VERSION 5.7 ;
BUSBITCHARS "[]" ;
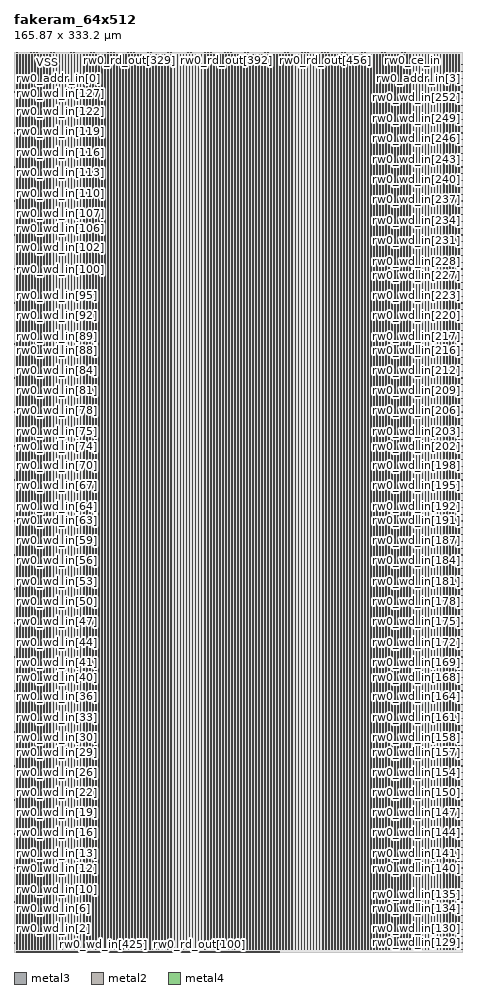
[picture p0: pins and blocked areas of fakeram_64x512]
MACRO fakeram_64x512
  FOREIGN fakeram_64x512 0 0 ;
  SYMMETRY X Y R90 ;
  SIZE 165.870 BY 333.200 ;
  CLASS BLOCK ;
  PIN rw0_wd_in[0]
    DIRECTION INPUT ;
    USE SIGNAL ;
    SHAPE ABUTMENT ;
    PORT
      LAYER metal3 ;
      RECT 0.000 0.805 0.210 0.875 ;
    END
  END rw0_wd_in[0]
  PIN rw0_wd_in[1]
    DIRECTION INPUT ;
    USE SIGNAL ;
    SHAPE ABUTMENT ;
    PORT
      LAYER metal3 ;
      RECT 0.000 3.325 0.210 3.395 ;
    END
  END rw0_wd_in[1]
  PIN rw0_wd_in[2]
    DIRECTION INPUT ;
    USE SIGNAL ;
    SHAPE ABUTMENT ;
    PORT
      LAYER metal3 ;
      RECT 0.000 5.845 0.210 5.915 ;
    END
  END rw0_wd_in[2]
  PIN rw0_wd_in[3]
    DIRECTION INPUT ;
    USE SIGNAL ;
    SHAPE ABUTMENT ;
    PORT
      LAYER metal3 ;
      RECT 0.000 8.365 0.210 8.435 ;
    END
  END rw0_wd_in[3]
  PIN rw0_wd_in[4]
    DIRECTION INPUT ;
    USE SIGNAL ;
    SHAPE ABUTMENT ;
    PORT
      LAYER metal3 ;
      RECT 0.000 10.885 0.210 10.955 ;
    END
  END rw0_wd_in[4]
  PIN rw0_wd_in[5]
    DIRECTION INPUT ;
    USE SIGNAL ;
    SHAPE ABUTMENT ;
    PORT
      LAYER metal3 ;
      RECT 0.000 13.405 0.210 13.475 ;
    END
  END rw0_wd_in[5]
  PIN rw0_wd_in[6]
    DIRECTION INPUT ;
    USE SIGNAL ;
    SHAPE ABUTMENT ;
    PORT
      LAYER metal3 ;
      RECT 0.000 15.925 0.210 15.995 ;
    END
  END rw0_wd_in[6]
  PIN rw0_wd_in[7]
    DIRECTION INPUT ;
    USE SIGNAL ;
    SHAPE ABUTMENT ;
    PORT
      LAYER metal3 ;
      RECT 0.000 18.445 0.210 18.515 ;
    END
  END rw0_wd_in[7]
  PIN rw0_wd_in[8]
    DIRECTION INPUT ;
    USE SIGNAL ;
    SHAPE ABUTMENT ;
    PORT
      LAYER metal3 ;
      RECT 0.000 20.965 0.210 21.035 ;
    END
  END rw0_wd_in[8]
  PIN rw0_wd_in[9]
    DIRECTION INPUT ;
    USE SIGNAL ;
    SHAPE ABUTMENT ;
    PORT
      LAYER metal3 ;
      RECT 0.000 23.485 0.210 23.555 ;
    END
  END rw0_wd_in[9]
  PIN rw0_wd_in[10]
    DIRECTION INPUT ;
    USE SIGNAL ;
    SHAPE ABUTMENT ;
    PORT
      LAYER metal3 ;
      RECT 0.000 26.005 0.210 26.075 ;
    END
  END rw0_wd_in[10]
  PIN rw0_wd_in[11]
    DIRECTION INPUT ;
    USE SIGNAL ;
    SHAPE ABUTMENT ;
    PORT
      LAYER metal3 ;
      RECT 0.000 28.525 0.210 28.595 ;
    END
  END rw0_wd_in[11]
  PIN rw0_wd_in[12]
    DIRECTION INPUT ;
    USE SIGNAL ;
    SHAPE ABUTMENT ;
    PORT
      LAYER metal3 ;
      RECT 0.000 31.045 0.210 31.115 ;
    END
  END rw0_wd_in[12]
  PIN rw0_wd_in[13]
    DIRECTION INPUT ;
    USE SIGNAL ;
    SHAPE ABUTMENT ;
    PORT
      LAYER metal3 ;
      RECT 0.000 33.565 0.210 33.635 ;
    END
  END rw0_wd_in[13]
  PIN rw0_wd_in[14]
    DIRECTION INPUT ;
    USE SIGNAL ;
    SHAPE ABUTMENT ;
    PORT
      LAYER metal3 ;
      RECT 0.000 36.085 0.210 36.155 ;
    END
  END rw0_wd_in[14]
  PIN rw0_wd_in[15]
    DIRECTION INPUT ;
    USE SIGNAL ;
    SHAPE ABUTMENT ;
    PORT
      LAYER metal3 ;
      RECT 0.000 38.605 0.210 38.675 ;
    END
  END rw0_wd_in[15]
  PIN rw0_wd_in[16]
    DIRECTION INPUT ;
    USE SIGNAL ;
    SHAPE ABUTMENT ;
    PORT
      LAYER metal3 ;
      RECT 0.000 41.125 0.210 41.195 ;
    END
  END rw0_wd_in[16]
  PIN rw0_wd_in[17]
    DIRECTION INPUT ;
    USE SIGNAL ;
    SHAPE ABUTMENT ;
    PORT
      LAYER metal3 ;
      RECT 0.000 43.645 0.210 43.715 ;
    END
  END rw0_wd_in[17]
  PIN rw0_wd_in[18]
    DIRECTION INPUT ;
    USE SIGNAL ;
    SHAPE ABUTMENT ;
    PORT
      LAYER metal3 ;
      RECT 0.000 46.165 0.210 46.235 ;
    END
  END rw0_wd_in[18]
  PIN rw0_wd_in[19]
    DIRECTION INPUT ;
    USE SIGNAL ;
    SHAPE ABUTMENT ;
    PORT
      LAYER metal3 ;
      RECT 0.000 48.685 0.210 48.755 ;
    END
  END rw0_wd_in[19]
  PIN rw0_wd_in[20]
    DIRECTION INPUT ;
    USE SIGNAL ;
    SHAPE ABUTMENT ;
    PORT
      LAYER metal3 ;
      RECT 0.000 51.205 0.210 51.275 ;
    END
  END rw0_wd_in[20]
  PIN rw0_wd_in[21]
    DIRECTION INPUT ;
    USE SIGNAL ;
    SHAPE ABUTMENT ;
    PORT
      LAYER metal3 ;
      RECT 0.000 53.725 0.210 53.795 ;
    END
  END rw0_wd_in[21]
  PIN rw0_wd_in[22]
    DIRECTION INPUT ;
    USE SIGNAL ;
    SHAPE ABUTMENT ;
    PORT
      LAYER metal3 ;
      RECT 0.000 56.245 0.210 56.315 ;
    END
  END rw0_wd_in[22]
  PIN rw0_wd_in[23]
    DIRECTION INPUT ;
    USE SIGNAL ;
    SHAPE ABUTMENT ;
    PORT
      LAYER metal3 ;
      RECT 0.000 58.765 0.210 58.835 ;
    END
  END rw0_wd_in[23]
  PIN rw0_wd_in[24]
    DIRECTION INPUT ;
    USE SIGNAL ;
    SHAPE ABUTMENT ;
    PORT
      LAYER metal3 ;
      RECT 0.000 61.285 0.210 61.355 ;
    END
  END rw0_wd_in[24]
  PIN rw0_wd_in[25]
    DIRECTION INPUT ;
    USE SIGNAL ;
    SHAPE ABUTMENT ;
    PORT
      LAYER metal3 ;
      RECT 0.000 63.805 0.210 63.875 ;
    END
  END rw0_wd_in[25]
  PIN rw0_wd_in[26]
    DIRECTION INPUT ;
    USE SIGNAL ;
    SHAPE ABUTMENT ;
    PORT
      LAYER metal3 ;
      RECT 0.000 66.325 0.210 66.395 ;
    END
  END rw0_wd_in[26]
  PIN rw0_wd_in[27]
    DIRECTION INPUT ;
    USE SIGNAL ;
    SHAPE ABUTMENT ;
    PORT
      LAYER metal3 ;
      RECT 0.000 68.845 0.210 68.915 ;
    END
  END rw0_wd_in[27]
  PIN rw0_wd_in[28]
    DIRECTION INPUT ;
    USE SIGNAL ;
    SHAPE ABUTMENT ;
    PORT
      LAYER metal3 ;
      RECT 0.000 71.365 0.210 71.435 ;
    END
  END rw0_wd_in[28]
  PIN rw0_wd_in[29]
    DIRECTION INPUT ;
    USE SIGNAL ;
    SHAPE ABUTMENT ;
    PORT
      LAYER metal3 ;
      RECT 0.000 73.885 0.210 73.955 ;
    END
  END rw0_wd_in[29]
  PIN rw0_wd_in[30]
    DIRECTION INPUT ;
    USE SIGNAL ;
    SHAPE ABUTMENT ;
    PORT
      LAYER metal3 ;
      RECT 0.000 76.405 0.210 76.475 ;
    END
  END rw0_wd_in[30]
  PIN rw0_wd_in[31]
    DIRECTION INPUT ;
    USE SIGNAL ;
    SHAPE ABUTMENT ;
    PORT
      LAYER metal3 ;
      RECT 0.000 78.925 0.210 78.995 ;
    END
  END rw0_wd_in[31]
  PIN rw0_wd_in[32]
    DIRECTION INPUT ;
    USE SIGNAL ;
    SHAPE ABUTMENT ;
    PORT
      LAYER metal3 ;
      RECT 0.000 81.445 0.210 81.515 ;
    END
  END rw0_wd_in[32]
  PIN rw0_wd_in[33]
    DIRECTION INPUT ;
    USE SIGNAL ;
    SHAPE ABUTMENT ;
    PORT
      LAYER metal3 ;
      RECT 0.000 83.965 0.210 84.035 ;
    END
  END rw0_wd_in[33]
  PIN rw0_wd_in[34]
    DIRECTION INPUT ;
    USE SIGNAL ;
    SHAPE ABUTMENT ;
    PORT
      LAYER metal3 ;
      RECT 0.000 86.485 0.210 86.555 ;
    END
  END rw0_wd_in[34]
  PIN rw0_wd_in[35]
    DIRECTION INPUT ;
    USE SIGNAL ;
    SHAPE ABUTMENT ;
    PORT
      LAYER metal3 ;
      RECT 0.000 89.005 0.210 89.075 ;
    END
  END rw0_wd_in[35]
  PIN rw0_wd_in[36]
    DIRECTION INPUT ;
    USE SIGNAL ;
    SHAPE ABUTMENT ;
    PORT
      LAYER metal3 ;
      RECT 0.000 91.525 0.210 91.595 ;
    END
  END rw0_wd_in[36]
  PIN rw0_wd_in[37]
    DIRECTION INPUT ;
    USE SIGNAL ;
    SHAPE ABUTMENT ;
    PORT
      LAYER metal3 ;
      RECT 0.000 94.045 0.210 94.115 ;
    END
  END rw0_wd_in[37]
  PIN rw0_wd_in[38]
    DIRECTION INPUT ;
    USE SIGNAL ;
    SHAPE ABUTMENT ;
    PORT
      LAYER metal3 ;
      RECT 0.000 96.565 0.210 96.635 ;
    END
  END rw0_wd_in[38]
  PIN rw0_wd_in[39]
    DIRECTION INPUT ;
    USE SIGNAL ;
    SHAPE ABUTMENT ;
    PORT
      LAYER metal3 ;
      RECT 0.000 99.085 0.210 99.155 ;
    END
  END rw0_wd_in[39]
  PIN rw0_wd_in[40]
    DIRECTION INPUT ;
    USE SIGNAL ;
    SHAPE ABUTMENT ;
    PORT
      LAYER metal3 ;
      RECT 0.000 101.605 0.210 101.675 ;
    END
  END rw0_wd_in[40]
  PIN rw0_wd_in[41]
    DIRECTION INPUT ;
    USE SIGNAL ;
    SHAPE ABUTMENT ;
    PORT
      LAYER metal3 ;
      RECT 0.000 104.125 0.210 104.195 ;
    END
  END rw0_wd_in[41]
  PIN rw0_wd_in[42]
    DIRECTION INPUT ;
    USE SIGNAL ;
    SHAPE ABUTMENT ;
    PORT
      LAYER metal3 ;
      RECT 0.000 106.645 0.210 106.715 ;
    END
  END rw0_wd_in[42]
  PIN rw0_wd_in[43]
    DIRECTION INPUT ;
    USE SIGNAL ;
    SHAPE ABUTMENT ;
    PORT
      LAYER metal3 ;
      RECT 0.000 109.165 0.210 109.235 ;
    END
  END rw0_wd_in[43]
  PIN rw0_wd_in[44]
    DIRECTION INPUT ;
    USE SIGNAL ;
    SHAPE ABUTMENT ;
    PORT
      LAYER metal3 ;
      RECT 0.000 111.685 0.210 111.755 ;
    END
  END rw0_wd_in[44]
  PIN rw0_wd_in[45]
    DIRECTION INPUT ;
    USE SIGNAL ;
    SHAPE ABUTMENT ;
    PORT
      LAYER metal3 ;
      RECT 0.000 114.205 0.210 114.275 ;
    END
  END rw0_wd_in[45]
  PIN rw0_wd_in[46]
    DIRECTION INPUT ;
    USE SIGNAL ;
    SHAPE ABUTMENT ;
    PORT
      LAYER metal3 ;
      RECT 0.000 116.725 0.210 116.795 ;
    END
  END rw0_wd_in[46]
  PIN rw0_wd_in[47]
    DIRECTION INPUT ;
    USE SIGNAL ;
    SHAPE ABUTMENT ;
    PORT
      LAYER metal3 ;
      RECT 0.000 119.245 0.210 119.315 ;
    END
  END rw0_wd_in[47]
  PIN rw0_wd_in[48]
    DIRECTION INPUT ;
    USE SIGNAL ;
    SHAPE ABUTMENT ;
    PORT
      LAYER metal3 ;
      RECT 0.000 121.765 0.210 121.835 ;
    END
  END rw0_wd_in[48]
  PIN rw0_wd_in[49]
    DIRECTION INPUT ;
    USE SIGNAL ;
    SHAPE ABUTMENT ;
    PORT
      LAYER metal3 ;
      RECT 0.000 124.285 0.210 124.355 ;
    END
  END rw0_wd_in[49]
  PIN rw0_wd_in[50]
    DIRECTION INPUT ;
    USE SIGNAL ;
    SHAPE ABUTMENT ;
    PORT
      LAYER metal3 ;
      RECT 0.000 126.805 0.210 126.875 ;
    END
  END rw0_wd_in[50]
  PIN rw0_wd_in[51]
    DIRECTION INPUT ;
    USE SIGNAL ;
    SHAPE ABUTMENT ;
    PORT
      LAYER metal3 ;
      RECT 0.000 129.325 0.210 129.395 ;
    END
  END rw0_wd_in[51]
  PIN rw0_wd_in[52]
    DIRECTION INPUT ;
    USE SIGNAL ;
    SHAPE ABUTMENT ;
    PORT
      LAYER metal3 ;
      RECT 0.000 131.845 0.210 131.915 ;
    END
  END rw0_wd_in[52]
  PIN rw0_wd_in[53]
    DIRECTION INPUT ;
    USE SIGNAL ;
    SHAPE ABUTMENT ;
    PORT
      LAYER metal3 ;
      RECT 0.000 134.365 0.210 134.435 ;
    END
  END rw0_wd_in[53]
  PIN rw0_wd_in[54]
    DIRECTION INPUT ;
    USE SIGNAL ;
    SHAPE ABUTMENT ;
    PORT
      LAYER metal3 ;
      RECT 0.000 136.885 0.210 136.955 ;
    END
  END rw0_wd_in[54]
  PIN rw0_wd_in[55]
    DIRECTION INPUT ;
    USE SIGNAL ;
    SHAPE ABUTMENT ;
    PORT
      LAYER metal3 ;
      RECT 0.000 139.405 0.210 139.475 ;
    END
  END rw0_wd_in[55]
  PIN rw0_wd_in[56]
    DIRECTION INPUT ;
    USE SIGNAL ;
    SHAPE ABUTMENT ;
    PORT
      LAYER metal3 ;
      RECT 0.000 141.925 0.210 141.995 ;
    END
  END rw0_wd_in[56]
  PIN rw0_wd_in[57]
    DIRECTION INPUT ;
    USE SIGNAL ;
    SHAPE ABUTMENT ;
    PORT
      LAYER metal3 ;
      RECT 0.000 144.445 0.210 144.515 ;
    END
  END rw0_wd_in[57]
  PIN rw0_wd_in[58]
    DIRECTION INPUT ;
    USE SIGNAL ;
    SHAPE ABUTMENT ;
    PORT
      LAYER metal3 ;
      RECT 0.000 146.965 0.210 147.035 ;
    END
  END rw0_wd_in[58]
  PIN rw0_wd_in[59]
    DIRECTION INPUT ;
    USE SIGNAL ;
    SHAPE ABUTMENT ;
    PORT
      LAYER metal3 ;
      RECT 0.000 149.485 0.210 149.555 ;
    END
  END rw0_wd_in[59]
  PIN rw0_wd_in[60]
    DIRECTION INPUT ;
    USE SIGNAL ;
    SHAPE ABUTMENT ;
    PORT
      LAYER metal3 ;
      RECT 0.000 152.005 0.210 152.075 ;
    END
  END rw0_wd_in[60]
  PIN rw0_wd_in[61]
    DIRECTION INPUT ;
    USE SIGNAL ;
    SHAPE ABUTMENT ;
    PORT
      LAYER metal3 ;
      RECT 0.000 154.525 0.210 154.595 ;
    END
  END rw0_wd_in[61]
  PIN rw0_wd_in[62]
    DIRECTION INPUT ;
    USE SIGNAL ;
    SHAPE ABUTMENT ;
    PORT
      LAYER metal3 ;
      RECT 0.000 157.045 0.210 157.115 ;
    END
  END rw0_wd_in[62]
  PIN rw0_wd_in[63]
    DIRECTION INPUT ;
    USE SIGNAL ;
    SHAPE ABUTMENT ;
    PORT
      LAYER metal3 ;
      RECT 0.000 159.565 0.210 159.635 ;
    END
  END rw0_wd_in[63]
  PIN rw0_wd_in[64]
    DIRECTION INPUT ;
    USE SIGNAL ;
    SHAPE ABUTMENT ;
    PORT
      LAYER metal3 ;
      RECT 0.000 162.085 0.210 162.155 ;
    END
  END rw0_wd_in[64]
  PIN rw0_wd_in[65]
    DIRECTION INPUT ;
    USE SIGNAL ;
    SHAPE ABUTMENT ;
    PORT
      LAYER metal3 ;
      RECT 0.000 164.605 0.210 164.675 ;
    END
  END rw0_wd_in[65]
  PIN rw0_wd_in[66]
    DIRECTION INPUT ;
    USE SIGNAL ;
    SHAPE ABUTMENT ;
    PORT
      LAYER metal3 ;
      RECT 0.000 167.125 0.210 167.195 ;
    END
  END rw0_wd_in[66]
  PIN rw0_wd_in[67]
    DIRECTION INPUT ;
    USE SIGNAL ;
    SHAPE ABUTMENT ;
    PORT
      LAYER metal3 ;
      RECT 0.000 169.645 0.210 169.715 ;
    END
  END rw0_wd_in[67]
  PIN rw0_wd_in[68]
    DIRECTION INPUT ;
    USE SIGNAL ;
    SHAPE ABUTMENT ;
    PORT
      LAYER metal3 ;
      RECT 0.000 172.165 0.210 172.235 ;
    END
  END rw0_wd_in[68]
  PIN rw0_wd_in[69]
    DIRECTION INPUT ;
    USE SIGNAL ;
    SHAPE ABUTMENT ;
    PORT
      LAYER metal3 ;
      RECT 0.000 174.685 0.210 174.755 ;
    END
  END rw0_wd_in[69]
  PIN rw0_wd_in[70]
    DIRECTION INPUT ;
    USE SIGNAL ;
    SHAPE ABUTMENT ;
    PORT
      LAYER metal3 ;
      RECT 0.000 177.205 0.210 177.275 ;
    END
  END rw0_wd_in[70]
  PIN rw0_wd_in[71]
    DIRECTION INPUT ;
    USE SIGNAL ;
    SHAPE ABUTMENT ;
    PORT
      LAYER metal3 ;
      RECT 0.000 179.725 0.210 179.795 ;
    END
  END rw0_wd_in[71]
  PIN rw0_wd_in[72]
    DIRECTION INPUT ;
    USE SIGNAL ;
    SHAPE ABUTMENT ;
    PORT
      LAYER metal3 ;
      RECT 0.000 182.245 0.210 182.315 ;
    END
  END rw0_wd_in[72]
  PIN rw0_wd_in[73]
    DIRECTION INPUT ;
    USE SIGNAL ;
    SHAPE ABUTMENT ;
    PORT
      LAYER metal3 ;
      RECT 0.000 184.765 0.210 184.835 ;
    END
  END rw0_wd_in[73]
  PIN rw0_wd_in[74]
    DIRECTION INPUT ;
    USE SIGNAL ;
    SHAPE ABUTMENT ;
    PORT
      LAYER metal3 ;
      RECT 0.000 187.285 0.210 187.355 ;
    END
  END rw0_wd_in[74]
  PIN rw0_wd_in[75]
    DIRECTION INPUT ;
    USE SIGNAL ;
    SHAPE ABUTMENT ;
    PORT
      LAYER metal3 ;
      RECT 0.000 189.805 0.210 189.875 ;
    END
  END rw0_wd_in[75]
  PIN rw0_wd_in[76]
    DIRECTION INPUT ;
    USE SIGNAL ;
    SHAPE ABUTMENT ;
    PORT
      LAYER metal3 ;
      RECT 0.000 192.325 0.210 192.395 ;
    END
  END rw0_wd_in[76]
  PIN rw0_wd_in[77]
    DIRECTION INPUT ;
    USE SIGNAL ;
    SHAPE ABUTMENT ;
    PORT
      LAYER metal3 ;
      RECT 0.000 194.845 0.210 194.915 ;
    END
  END rw0_wd_in[77]
  PIN rw0_wd_in[78]
    DIRECTION INPUT ;
    USE SIGNAL ;
    SHAPE ABUTMENT ;
    PORT
      LAYER metal3 ;
      RECT 0.000 197.365 0.210 197.435 ;
    END
  END rw0_wd_in[78]
  PIN rw0_wd_in[79]
    DIRECTION INPUT ;
    USE SIGNAL ;
    SHAPE ABUTMENT ;
    PORT
      LAYER metal3 ;
      RECT 0.000 199.885 0.210 199.955 ;
    END
  END rw0_wd_in[79]
  PIN rw0_wd_in[80]
    DIRECTION INPUT ;
    USE SIGNAL ;
    SHAPE ABUTMENT ;
    PORT
      LAYER metal3 ;
      RECT 0.000 202.405 0.210 202.475 ;
    END
  END rw0_wd_in[80]
  PIN rw0_wd_in[81]
    DIRECTION INPUT ;
    USE SIGNAL ;
    SHAPE ABUTMENT ;
    PORT
      LAYER metal3 ;
      RECT 0.000 204.925 0.210 204.995 ;
    END
  END rw0_wd_in[81]
  PIN rw0_wd_in[82]
    DIRECTION INPUT ;
    USE SIGNAL ;
    SHAPE ABUTMENT ;
    PORT
      LAYER metal3 ;
      RECT 0.000 207.445 0.210 207.515 ;
    END
  END rw0_wd_in[82]
  PIN rw0_wd_in[83]
    DIRECTION INPUT ;
    USE SIGNAL ;
    SHAPE ABUTMENT ;
    PORT
      LAYER metal3 ;
      RECT 0.000 209.965 0.210 210.035 ;
    END
  END rw0_wd_in[83]
  PIN rw0_wd_in[84]
    DIRECTION INPUT ;
    USE SIGNAL ;
    SHAPE ABUTMENT ;
    PORT
      LAYER metal3 ;
      RECT 0.000 212.485 0.210 212.555 ;
    END
  END rw0_wd_in[84]
  PIN rw0_wd_in[85]
    DIRECTION INPUT ;
    USE SIGNAL ;
    SHAPE ABUTMENT ;
    PORT
      LAYER metal3 ;
      RECT 0.000 215.005 0.210 215.075 ;
    END
  END rw0_wd_in[85]
  PIN rw0_wd_in[86]
    DIRECTION INPUT ;
    USE SIGNAL ;
    SHAPE ABUTMENT ;
    PORT
      LAYER metal3 ;
      RECT 0.000 217.525 0.210 217.595 ;
    END
  END rw0_wd_in[86]
  PIN rw0_wd_in[87]
    DIRECTION INPUT ;
    USE SIGNAL ;
    SHAPE ABUTMENT ;
    PORT
      LAYER metal3 ;
      RECT 0.000 220.045 0.210 220.115 ;
    END
  END rw0_wd_in[87]
  PIN rw0_wd_in[88]
    DIRECTION INPUT ;
    USE SIGNAL ;
    SHAPE ABUTMENT ;
    PORT
      LAYER metal3 ;
      RECT 0.000 222.565 0.210 222.635 ;
    END
  END rw0_wd_in[88]
  PIN rw0_wd_in[89]
    DIRECTION INPUT ;
    USE SIGNAL ;
    SHAPE ABUTMENT ;
    PORT
      LAYER metal3 ;
      RECT 0.000 225.085 0.210 225.155 ;
    END
  END rw0_wd_in[89]
  PIN rw0_wd_in[90]
    DIRECTION INPUT ;
    USE SIGNAL ;
    SHAPE ABUTMENT ;
    PORT
      LAYER metal3 ;
      RECT 0.000 227.605 0.210 227.675 ;
    END
  END rw0_wd_in[90]
  PIN rw0_wd_in[91]
    DIRECTION INPUT ;
    USE SIGNAL ;
    SHAPE ABUTMENT ;
    PORT
      LAYER metal3 ;
      RECT 0.000 230.125 0.210 230.195 ;
    END
  END rw0_wd_in[91]
  PIN rw0_wd_in[92]
    DIRECTION INPUT ;
    USE SIGNAL ;
    SHAPE ABUTMENT ;
    PORT
      LAYER metal3 ;
      RECT 0.000 232.645 0.210 232.715 ;
    END
  END rw0_wd_in[92]
  PIN rw0_wd_in[93]
    DIRECTION INPUT ;
    USE SIGNAL ;
    SHAPE ABUTMENT ;
    PORT
      LAYER metal3 ;
      RECT 0.000 235.165 0.210 235.235 ;
    END
  END rw0_wd_in[93]
  PIN rw0_wd_in[94]
    DIRECTION INPUT ;
    USE SIGNAL ;
    SHAPE ABUTMENT ;
    PORT
      LAYER metal3 ;
      RECT 0.000 237.685 0.210 237.755 ;
    END
  END rw0_wd_in[94]
  PIN rw0_wd_in[95]
    DIRECTION INPUT ;
    USE SIGNAL ;
    SHAPE ABUTMENT ;
    PORT
      LAYER metal3 ;
      RECT 0.000 240.205 0.210 240.275 ;
    END
  END rw0_wd_in[95]
  PIN rw0_wd_in[96]
    DIRECTION INPUT ;
    USE SIGNAL ;
    SHAPE ABUTMENT ;
    PORT
      LAYER metal3 ;
      RECT 0.000 242.725 0.210 242.795 ;
    END
  END rw0_wd_in[96]
  PIN rw0_wd_in[97]
    DIRECTION INPUT ;
    USE SIGNAL ;
    SHAPE ABUTMENT ;
    PORT
      LAYER metal3 ;
      RECT 0.000 245.245 0.210 245.315 ;
    END
  END rw0_wd_in[97]
  PIN rw0_wd_in[98]
    DIRECTION INPUT ;
    USE SIGNAL ;
    SHAPE ABUTMENT ;
    PORT
      LAYER metal3 ;
      RECT 0.000 247.765 0.210 247.835 ;
    END
  END rw0_wd_in[98]
  PIN rw0_wd_in[99]
    DIRECTION INPUT ;
    USE SIGNAL ;
    SHAPE ABUTMENT ;
    PORT
      LAYER metal3 ;
      RECT 0.000 250.285 0.210 250.355 ;
    END
  END rw0_wd_in[99]
  PIN rw0_wd_in[100]
    DIRECTION INPUT ;
    USE SIGNAL ;
    SHAPE ABUTMENT ;
    PORT
      LAYER metal3 ;
      RECT 0.000 252.805 0.210 252.875 ;
    END
  END rw0_wd_in[100]
  PIN rw0_wd_in[101]
    DIRECTION INPUT ;
    USE SIGNAL ;
    SHAPE ABUTMENT ;
    PORT
      LAYER metal3 ;
      RECT 0.000 255.325 0.210 255.395 ;
    END
  END rw0_wd_in[101]
  PIN rw0_wd_in[102]
    DIRECTION INPUT ;
    USE SIGNAL ;
    SHAPE ABUTMENT ;
    PORT
      LAYER metal3 ;
      RECT 0.000 257.845 0.210 257.915 ;
    END
  END rw0_wd_in[102]
  PIN rw0_wd_in[103]
    DIRECTION INPUT ;
    USE SIGNAL ;
    SHAPE ABUTMENT ;
    PORT
      LAYER metal3 ;
      RECT 0.000 260.365 0.210 260.435 ;
    END
  END rw0_wd_in[103]
  PIN rw0_wd_in[104]
    DIRECTION INPUT ;
    USE SIGNAL ;
    SHAPE ABUTMENT ;
    PORT
      LAYER metal3 ;
      RECT 0.000 262.885 0.210 262.955 ;
    END
  END rw0_wd_in[104]
  PIN rw0_wd_in[105]
    DIRECTION INPUT ;
    USE SIGNAL ;
    SHAPE ABUTMENT ;
    PORT
      LAYER metal3 ;
      RECT 0.000 265.405 0.210 265.475 ;
    END
  END rw0_wd_in[105]
  PIN rw0_wd_in[106]
    DIRECTION INPUT ;
    USE SIGNAL ;
    SHAPE ABUTMENT ;
    PORT
      LAYER metal3 ;
      RECT 0.000 267.925 0.210 267.995 ;
    END
  END rw0_wd_in[106]
  PIN rw0_wd_in[107]
    DIRECTION INPUT ;
    USE SIGNAL ;
    SHAPE ABUTMENT ;
    PORT
      LAYER metal3 ;
      RECT 0.000 270.445 0.210 270.515 ;
    END
  END rw0_wd_in[107]
  PIN rw0_wd_in[108]
    DIRECTION INPUT ;
    USE SIGNAL ;
    SHAPE ABUTMENT ;
    PORT
      LAYER metal3 ;
      RECT 0.000 272.965 0.210 273.035 ;
    END
  END rw0_wd_in[108]
  PIN rw0_wd_in[109]
    DIRECTION INPUT ;
    USE SIGNAL ;
    SHAPE ABUTMENT ;
    PORT
      LAYER metal3 ;
      RECT 0.000 275.485 0.210 275.555 ;
    END
  END rw0_wd_in[109]
  PIN rw0_wd_in[110]
    DIRECTION INPUT ;
    USE SIGNAL ;
    SHAPE ABUTMENT ;
    PORT
      LAYER metal3 ;
      RECT 0.000 278.005 0.210 278.075 ;
    END
  END rw0_wd_in[110]
  PIN rw0_wd_in[111]
    DIRECTION INPUT ;
    USE SIGNAL ;
    SHAPE ABUTMENT ;
    PORT
      LAYER metal3 ;
      RECT 0.000 280.525 0.210 280.595 ;
    END
  END rw0_wd_in[111]
  PIN rw0_wd_in[112]
    DIRECTION INPUT ;
    USE SIGNAL ;
    SHAPE ABUTMENT ;
    PORT
      LAYER metal3 ;
      RECT 0.000 283.045 0.210 283.115 ;
    END
  END rw0_wd_in[112]
  PIN rw0_wd_in[113]
    DIRECTION INPUT ;
    USE SIGNAL ;
    SHAPE ABUTMENT ;
    PORT
      LAYER metal3 ;
      RECT 0.000 285.565 0.210 285.635 ;
    END
  END rw0_wd_in[113]
  PIN rw0_wd_in[114]
    DIRECTION INPUT ;
    USE SIGNAL ;
    SHAPE ABUTMENT ;
    PORT
      LAYER metal3 ;
      RECT 0.000 288.085 0.210 288.155 ;
    END
  END rw0_wd_in[114]
  PIN rw0_wd_in[115]
    DIRECTION INPUT ;
    USE SIGNAL ;
    SHAPE ABUTMENT ;
    PORT
      LAYER metal3 ;
      RECT 0.000 290.605 0.210 290.675 ;
    END
  END rw0_wd_in[115]
  PIN rw0_wd_in[116]
    DIRECTION INPUT ;
    USE SIGNAL ;
    SHAPE ABUTMENT ;
    PORT
      LAYER metal3 ;
      RECT 0.000 293.125 0.210 293.195 ;
    END
  END rw0_wd_in[116]
  PIN rw0_wd_in[117]
    DIRECTION INPUT ;
    USE SIGNAL ;
    SHAPE ABUTMENT ;
    PORT
      LAYER metal3 ;
      RECT 0.000 295.645 0.210 295.715 ;
    END
  END rw0_wd_in[117]
  PIN rw0_wd_in[118]
    DIRECTION INPUT ;
    USE SIGNAL ;
    SHAPE ABUTMENT ;
    PORT
      LAYER metal3 ;
      RECT 0.000 298.165 0.210 298.235 ;
    END
  END rw0_wd_in[118]
  PIN rw0_wd_in[119]
    DIRECTION INPUT ;
    USE SIGNAL ;
    SHAPE ABUTMENT ;
    PORT
      LAYER metal3 ;
      RECT 0.000 300.685 0.210 300.755 ;
    END
  END rw0_wd_in[119]
  PIN rw0_wd_in[120]
    DIRECTION INPUT ;
    USE SIGNAL ;
    SHAPE ABUTMENT ;
    PORT
      LAYER metal3 ;
      RECT 0.000 303.205 0.210 303.275 ;
    END
  END rw0_wd_in[120]
  PIN rw0_wd_in[121]
    DIRECTION INPUT ;
    USE SIGNAL ;
    SHAPE ABUTMENT ;
    PORT
      LAYER metal3 ;
      RECT 0.000 305.725 0.210 305.795 ;
    END
  END rw0_wd_in[121]
  PIN rw0_wd_in[122]
    DIRECTION INPUT ;
    USE SIGNAL ;
    SHAPE ABUTMENT ;
    PORT
      LAYER metal3 ;
      RECT 0.000 308.245 0.210 308.315 ;
    END
  END rw0_wd_in[122]
  PIN rw0_wd_in[123]
    DIRECTION INPUT ;
    USE SIGNAL ;
    SHAPE ABUTMENT ;
    PORT
      LAYER metal3 ;
      RECT 0.000 310.765 0.210 310.835 ;
    END
  END rw0_wd_in[123]
  PIN rw0_wd_in[124]
    DIRECTION INPUT ;
    USE SIGNAL ;
    SHAPE ABUTMENT ;
    PORT
      LAYER metal3 ;
      RECT 0.000 313.285 0.210 313.355 ;
    END
  END rw0_wd_in[124]
  PIN rw0_wd_in[125]
    DIRECTION INPUT ;
    USE SIGNAL ;
    SHAPE ABUTMENT ;
    PORT
      LAYER metal3 ;
      RECT 0.000 315.805 0.210 315.875 ;
    END
  END rw0_wd_in[125]
  PIN rw0_wd_in[126]
    DIRECTION INPUT ;
    USE SIGNAL ;
    SHAPE ABUTMENT ;
    PORT
      LAYER metal3 ;
      RECT 0.000 318.325 0.210 318.395 ;
    END
  END rw0_wd_in[126]
  PIN rw0_wd_in[127]
    DIRECTION INPUT ;
    USE SIGNAL ;
    SHAPE ABUTMENT ;
    PORT
      LAYER metal3 ;
      RECT 0.000 320.845 0.210 320.915 ;
    END
  END rw0_wd_in[127]
  PIN rw0_wd_in[128]
    DIRECTION INPUT ;
    USE SIGNAL ;
    SHAPE ABUTMENT ;
    PORT
      LAYER metal3 ;
      RECT 165.660 0.805 165.870 0.875 ;
    END
  END rw0_wd_in[128]
  PIN rw0_wd_in[129]
    DIRECTION INPUT ;
    USE SIGNAL ;
    SHAPE ABUTMENT ;
    PORT
      LAYER metal3 ;
      RECT 165.660 3.325 165.870 3.395 ;
    END
  END rw0_wd_in[129]
  PIN rw0_wd_in[130]
    DIRECTION INPUT ;
    USE SIGNAL ;
    SHAPE ABUTMENT ;
    PORT
      LAYER metal3 ;
      RECT 165.660 5.845 165.870 5.915 ;
    END
  END rw0_wd_in[130]
  PIN rw0_wd_in[131]
    DIRECTION INPUT ;
    USE SIGNAL ;
    SHAPE ABUTMENT ;
    PORT
      LAYER metal3 ;
      RECT 165.660 8.365 165.870 8.435 ;
    END
  END rw0_wd_in[131]
  PIN rw0_wd_in[132]
    DIRECTION INPUT ;
    USE SIGNAL ;
    SHAPE ABUTMENT ;
    PORT
      LAYER metal3 ;
      RECT 165.660 10.885 165.870 10.955 ;
    END
  END rw0_wd_in[132]
  PIN rw0_wd_in[133]
    DIRECTION INPUT ;
    USE SIGNAL ;
    SHAPE ABUTMENT ;
    PORT
      LAYER metal3 ;
      RECT 165.660 13.405 165.870 13.475 ;
    END
  END rw0_wd_in[133]
  PIN rw0_wd_in[134]
    DIRECTION INPUT ;
    USE SIGNAL ;
    SHAPE ABUTMENT ;
    PORT
      LAYER metal3 ;
      RECT 165.660 15.925 165.870 15.995 ;
    END
  END rw0_wd_in[134]
  PIN rw0_wd_in[135]
    DIRECTION INPUT ;
    USE SIGNAL ;
    SHAPE ABUTMENT ;
    PORT
      LAYER metal3 ;
      RECT 165.660 18.445 165.870 18.515 ;
    END
  END rw0_wd_in[135]
  PIN rw0_wd_in[136]
    DIRECTION INPUT ;
    USE SIGNAL ;
    SHAPE ABUTMENT ;
    PORT
      LAYER metal3 ;
      RECT 165.660 20.965 165.870 21.035 ;
    END
  END rw0_wd_in[136]
  PIN rw0_wd_in[137]
    DIRECTION INPUT ;
    USE SIGNAL ;
    SHAPE ABUTMENT ;
    PORT
      LAYER metal3 ;
      RECT 165.660 23.485 165.870 23.555 ;
    END
  END rw0_wd_in[137]
  PIN rw0_wd_in[138]
    DIRECTION INPUT ;
    USE SIGNAL ;
    SHAPE ABUTMENT ;
    PORT
      LAYER metal3 ;
      RECT 165.660 26.005 165.870 26.075 ;
    END
  END rw0_wd_in[138]
  PIN rw0_wd_in[139]
    DIRECTION INPUT ;
    USE SIGNAL ;
    SHAPE ABUTMENT ;
    PORT
      LAYER metal3 ;
      RECT 165.660 28.525 165.870 28.595 ;
    END
  END rw0_wd_in[139]
  PIN rw0_wd_in[140]
    DIRECTION INPUT ;
    USE SIGNAL ;
    SHAPE ABUTMENT ;
    PORT
      LAYER metal3 ;
      RECT 165.660 31.045 165.870 31.115 ;
    END
  END rw0_wd_in[140]
  PIN rw0_wd_in[141]
    DIRECTION INPUT ;
    USE SIGNAL ;
    SHAPE ABUTMENT ;
    PORT
      LAYER metal3 ;
      RECT 165.660 33.565 165.870 33.635 ;
    END
  END rw0_wd_in[141]
  PIN rw0_wd_in[142]
    DIRECTION INPUT ;
    USE SIGNAL ;
    SHAPE ABUTMENT ;
    PORT
      LAYER metal3 ;
      RECT 165.660 36.085 165.870 36.155 ;
    END
  END rw0_wd_in[142]
  PIN rw0_wd_in[143]
    DIRECTION INPUT ;
    USE SIGNAL ;
    SHAPE ABUTMENT ;
    PORT
      LAYER metal3 ;
      RECT 165.660 38.605 165.870 38.675 ;
    END
  END rw0_wd_in[143]
  PIN rw0_wd_in[144]
    DIRECTION INPUT ;
    USE SIGNAL ;
    SHAPE ABUTMENT ;
    PORT
      LAYER metal3 ;
      RECT 165.660 41.125 165.870 41.195 ;
    END
  END rw0_wd_in[144]
  PIN rw0_wd_in[145]
    DIRECTION INPUT ;
    USE SIGNAL ;
    SHAPE ABUTMENT ;
    PORT
      LAYER metal3 ;
      RECT 165.660 43.645 165.870 43.715 ;
    END
  END rw0_wd_in[145]
  PIN rw0_wd_in[146]
    DIRECTION INPUT ;
    USE SIGNAL ;
    SHAPE ABUTMENT ;
    PORT
      LAYER metal3 ;
      RECT 165.660 46.165 165.870 46.235 ;
    END
  END rw0_wd_in[146]
  PIN rw0_wd_in[147]
    DIRECTION INPUT ;
    USE SIGNAL ;
    SHAPE ABUTMENT ;
    PORT
      LAYER metal3 ;
      RECT 165.660 48.685 165.870 48.755 ;
    END
  END rw0_wd_in[147]
  PIN rw0_wd_in[148]
    DIRECTION INPUT ;
    USE SIGNAL ;
    SHAPE ABUTMENT ;
    PORT
      LAYER metal3 ;
      RECT 165.660 51.205 165.870 51.275 ;
    END
  END rw0_wd_in[148]
  PIN rw0_wd_in[149]
    DIRECTION INPUT ;
    USE SIGNAL ;
    SHAPE ABUTMENT ;
    PORT
      LAYER metal3 ;
      RECT 165.660 53.725 165.870 53.795 ;
    END
  END rw0_wd_in[149]
  PIN rw0_wd_in[150]
    DIRECTION INPUT ;
    USE SIGNAL ;
    SHAPE ABUTMENT ;
    PORT
      LAYER metal3 ;
      RECT 165.660 56.245 165.870 56.315 ;
    END
  END rw0_wd_in[150]
  PIN rw0_wd_in[151]
    DIRECTION INPUT ;
    USE SIGNAL ;
    SHAPE ABUTMENT ;
    PORT
      LAYER metal3 ;
      RECT 165.660 58.765 165.870 58.835 ;
    END
  END rw0_wd_in[151]
  PIN rw0_wd_in[152]
    DIRECTION INPUT ;
    USE SIGNAL ;
    SHAPE ABUTMENT ;
    PORT
      LAYER metal3 ;
      RECT 165.660 61.285 165.870 61.355 ;
    END
  END rw0_wd_in[152]
  PIN rw0_wd_in[153]
    DIRECTION INPUT ;
    USE SIGNAL ;
    SHAPE ABUTMENT ;
    PORT
      LAYER metal3 ;
      RECT 165.660 63.805 165.870 63.875 ;
    END
  END rw0_wd_in[153]
  PIN rw0_wd_in[154]
    DIRECTION INPUT ;
    USE SIGNAL ;
    SHAPE ABUTMENT ;
    PORT
      LAYER metal3 ;
      RECT 165.660 66.325 165.870 66.395 ;
    END
  END rw0_wd_in[154]
  PIN rw0_wd_in[155]
    DIRECTION INPUT ;
    USE SIGNAL ;
    SHAPE ABUTMENT ;
    PORT
      LAYER metal3 ;
      RECT 165.660 68.845 165.870 68.915 ;
    END
  END rw0_wd_in[155]
  PIN rw0_wd_in[156]
    DIRECTION INPUT ;
    USE SIGNAL ;
    SHAPE ABUTMENT ;
    PORT
      LAYER metal3 ;
      RECT 165.660 71.365 165.870 71.435 ;
    END
  END rw0_wd_in[156]
  PIN rw0_wd_in[157]
    DIRECTION INPUT ;
    USE SIGNAL ;
    SHAPE ABUTMENT ;
    PORT
      LAYER metal3 ;
      RECT 165.660 73.885 165.870 73.955 ;
    END
  END rw0_wd_in[157]
  PIN rw0_wd_in[158]
    DIRECTION INPUT ;
    USE SIGNAL ;
    SHAPE ABUTMENT ;
    PORT
      LAYER metal3 ;
      RECT 165.660 76.405 165.870 76.475 ;
    END
  END rw0_wd_in[158]
  PIN rw0_wd_in[159]
    DIRECTION INPUT ;
    USE SIGNAL ;
    SHAPE ABUTMENT ;
    PORT
      LAYER metal3 ;
      RECT 165.660 78.925 165.870 78.995 ;
    END
  END rw0_wd_in[159]
  PIN rw0_wd_in[160]
    DIRECTION INPUT ;
    USE SIGNAL ;
    SHAPE ABUTMENT ;
    PORT
      LAYER metal3 ;
      RECT 165.660 81.445 165.870 81.515 ;
    END
  END rw0_wd_in[160]
  PIN rw0_wd_in[161]
    DIRECTION INPUT ;
    USE SIGNAL ;
    SHAPE ABUTMENT ;
    PORT
      LAYER metal3 ;
      RECT 165.660 83.965 165.870 84.035 ;
    END
  END rw0_wd_in[161]
  PIN rw0_wd_in[162]
    DIRECTION INPUT ;
    USE SIGNAL ;
    SHAPE ABUTMENT ;
    PORT
      LAYER metal3 ;
      RECT 165.660 86.485 165.870 86.555 ;
    END
  END rw0_wd_in[162]
  PIN rw0_wd_in[163]
    DIRECTION INPUT ;
    USE SIGNAL ;
    SHAPE ABUTMENT ;
    PORT
      LAYER metal3 ;
      RECT 165.660 89.005 165.870 89.075 ;
    END
  END rw0_wd_in[163]
  PIN rw0_wd_in[164]
    DIRECTION INPUT ;
    USE SIGNAL ;
    SHAPE ABUTMENT ;
    PORT
      LAYER metal3 ;
      RECT 165.660 91.525 165.870 91.595 ;
    END
  END rw0_wd_in[164]
  PIN rw0_wd_in[165]
    DIRECTION INPUT ;
    USE SIGNAL ;
    SHAPE ABUTMENT ;
    PORT
      LAYER metal3 ;
      RECT 165.660 94.045 165.870 94.115 ;
    END
  END rw0_wd_in[165]
  PIN rw0_wd_in[166]
    DIRECTION INPUT ;
    USE SIGNAL ;
    SHAPE ABUTMENT ;
    PORT
      LAYER metal3 ;
      RECT 165.660 96.565 165.870 96.635 ;
    END
  END rw0_wd_in[166]
  PIN rw0_wd_in[167]
    DIRECTION INPUT ;
    USE SIGNAL ;
    SHAPE ABUTMENT ;
    PORT
      LAYER metal3 ;
      RECT 165.660 99.085 165.870 99.155 ;
    END
  END rw0_wd_in[167]
  PIN rw0_wd_in[168]
    DIRECTION INPUT ;
    USE SIGNAL ;
    SHAPE ABUTMENT ;
    PORT
      LAYER metal3 ;
      RECT 165.660 101.605 165.870 101.675 ;
    END
  END rw0_wd_in[168]
  PIN rw0_wd_in[169]
    DIRECTION INPUT ;
    USE SIGNAL ;
    SHAPE ABUTMENT ;
    PORT
      LAYER metal3 ;
      RECT 165.660 104.125 165.870 104.195 ;
    END
  END rw0_wd_in[169]
  PIN rw0_wd_in[170]
    DIRECTION INPUT ;
    USE SIGNAL ;
    SHAPE ABUTMENT ;
    PORT
      LAYER metal3 ;
      RECT 165.660 106.645 165.870 106.715 ;
    END
  END rw0_wd_in[170]
  PIN rw0_wd_in[171]
    DIRECTION INPUT ;
    USE SIGNAL ;
    SHAPE ABUTMENT ;
    PORT
      LAYER metal3 ;
      RECT 165.660 109.165 165.870 109.235 ;
    END
  END rw0_wd_in[171]
  PIN rw0_wd_in[172]
    DIRECTION INPUT ;
    USE SIGNAL ;
    SHAPE ABUTMENT ;
    PORT
      LAYER metal3 ;
      RECT 165.660 111.685 165.870 111.755 ;
    END
  END rw0_wd_in[172]
  PIN rw0_wd_in[173]
    DIRECTION INPUT ;
    USE SIGNAL ;
    SHAPE ABUTMENT ;
    PORT
      LAYER metal3 ;
      RECT 165.660 114.205 165.870 114.275 ;
    END
  END rw0_wd_in[173]
  PIN rw0_wd_in[174]
    DIRECTION INPUT ;
    USE SIGNAL ;
    SHAPE ABUTMENT ;
    PORT
      LAYER metal3 ;
      RECT 165.660 116.725 165.870 116.795 ;
    END
  END rw0_wd_in[174]
  PIN rw0_wd_in[175]
    DIRECTION INPUT ;
    USE SIGNAL ;
    SHAPE ABUTMENT ;
    PORT
      LAYER metal3 ;
      RECT 165.660 119.245 165.870 119.315 ;
    END
  END rw0_wd_in[175]
  PIN rw0_wd_in[176]
    DIRECTION INPUT ;
    USE SIGNAL ;
    SHAPE ABUTMENT ;
    PORT
      LAYER metal3 ;
      RECT 165.660 121.765 165.870 121.835 ;
    END
  END rw0_wd_in[176]
  PIN rw0_wd_in[177]
    DIRECTION INPUT ;
    USE SIGNAL ;
    SHAPE ABUTMENT ;
    PORT
      LAYER metal3 ;
      RECT 165.660 124.285 165.870 124.355 ;
    END
  END rw0_wd_in[177]
  PIN rw0_wd_in[178]
    DIRECTION INPUT ;
    USE SIGNAL ;
    SHAPE ABUTMENT ;
    PORT
      LAYER metal3 ;
      RECT 165.660 126.805 165.870 126.875 ;
    END
  END rw0_wd_in[178]
  PIN rw0_wd_in[179]
    DIRECTION INPUT ;
    USE SIGNAL ;
    SHAPE ABUTMENT ;
    PORT
      LAYER metal3 ;
      RECT 165.660 129.325 165.870 129.395 ;
    END
  END rw0_wd_in[179]
  PIN rw0_wd_in[180]
    DIRECTION INPUT ;
    USE SIGNAL ;
    SHAPE ABUTMENT ;
    PORT
      LAYER metal3 ;
      RECT 165.660 131.845 165.870 131.915 ;
    END
  END rw0_wd_in[180]
  PIN rw0_wd_in[181]
    DIRECTION INPUT ;
    USE SIGNAL ;
    SHAPE ABUTMENT ;
    PORT
      LAYER metal3 ;
      RECT 165.660 134.365 165.870 134.435 ;
    END
  END rw0_wd_in[181]
  PIN rw0_wd_in[182]
    DIRECTION INPUT ;
    USE SIGNAL ;
    SHAPE ABUTMENT ;
    PORT
      LAYER metal3 ;
      RECT 165.660 136.885 165.870 136.955 ;
    END
  END rw0_wd_in[182]
  PIN rw0_wd_in[183]
    DIRECTION INPUT ;
    USE SIGNAL ;
    SHAPE ABUTMENT ;
    PORT
      LAYER metal3 ;
      RECT 165.660 139.405 165.870 139.475 ;
    END
  END rw0_wd_in[183]
  PIN rw0_wd_in[184]
    DIRECTION INPUT ;
    USE SIGNAL ;
    SHAPE ABUTMENT ;
    PORT
      LAYER metal3 ;
      RECT 165.660 141.925 165.870 141.995 ;
    END
  END rw0_wd_in[184]
  PIN rw0_wd_in[185]
    DIRECTION INPUT ;
    USE SIGNAL ;
    SHAPE ABUTMENT ;
    PORT
      LAYER metal3 ;
      RECT 165.660 144.445 165.870 144.515 ;
    END
  END rw0_wd_in[185]
  PIN rw0_wd_in[186]
    DIRECTION INPUT ;
    USE SIGNAL ;
    SHAPE ABUTMENT ;
    PORT
      LAYER metal3 ;
      RECT 165.660 146.965 165.870 147.035 ;
    END
  END rw0_wd_in[186]
  PIN rw0_wd_in[187]
    DIRECTION INPUT ;
    USE SIGNAL ;
    SHAPE ABUTMENT ;
    PORT
      LAYER metal3 ;
      RECT 165.660 149.485 165.870 149.555 ;
    END
  END rw0_wd_in[187]
  PIN rw0_wd_in[188]
    DIRECTION INPUT ;
    USE SIGNAL ;
    SHAPE ABUTMENT ;
    PORT
      LAYER metal3 ;
      RECT 165.660 152.005 165.870 152.075 ;
    END
  END rw0_wd_in[188]
  PIN rw0_wd_in[189]
    DIRECTION INPUT ;
    USE SIGNAL ;
    SHAPE ABUTMENT ;
    PORT
      LAYER metal3 ;
      RECT 165.660 154.525 165.870 154.595 ;
    END
  END rw0_wd_in[189]
  PIN rw0_wd_in[190]
    DIRECTION INPUT ;
    USE SIGNAL ;
    SHAPE ABUTMENT ;
    PORT
      LAYER metal3 ;
      RECT 165.660 157.045 165.870 157.115 ;
    END
  END rw0_wd_in[190]
  PIN rw0_wd_in[191]
    DIRECTION INPUT ;
    USE SIGNAL ;
    SHAPE ABUTMENT ;
    PORT
      LAYER metal3 ;
      RECT 165.660 159.565 165.870 159.635 ;
    END
  END rw0_wd_in[191]
  PIN rw0_wd_in[192]
    DIRECTION INPUT ;
    USE SIGNAL ;
    SHAPE ABUTMENT ;
    PORT
      LAYER metal3 ;
      RECT 165.660 162.085 165.870 162.155 ;
    END
  END rw0_wd_in[192]
  PIN rw0_wd_in[193]
    DIRECTION INPUT ;
    USE SIGNAL ;
    SHAPE ABUTMENT ;
    PORT
      LAYER metal3 ;
      RECT 165.660 164.605 165.870 164.675 ;
    END
  END rw0_wd_in[193]
  PIN rw0_wd_in[194]
    DIRECTION INPUT ;
    USE SIGNAL ;
    SHAPE ABUTMENT ;
    PORT
      LAYER metal3 ;
      RECT 165.660 167.125 165.870 167.195 ;
    END
  END rw0_wd_in[194]
  PIN rw0_wd_in[195]
    DIRECTION INPUT ;
    USE SIGNAL ;
    SHAPE ABUTMENT ;
    PORT
      LAYER metal3 ;
      RECT 165.660 169.645 165.870 169.715 ;
    END
  END rw0_wd_in[195]
  PIN rw0_wd_in[196]
    DIRECTION INPUT ;
    USE SIGNAL ;
    SHAPE ABUTMENT ;
    PORT
      LAYER metal3 ;
      RECT 165.660 172.165 165.870 172.235 ;
    END
  END rw0_wd_in[196]
  PIN rw0_wd_in[197]
    DIRECTION INPUT ;
    USE SIGNAL ;
    SHAPE ABUTMENT ;
    PORT
      LAYER metal3 ;
      RECT 165.660 174.685 165.870 174.755 ;
    END
  END rw0_wd_in[197]
  PIN rw0_wd_in[198]
    DIRECTION INPUT ;
    USE SIGNAL ;
    SHAPE ABUTMENT ;
    PORT
      LAYER metal3 ;
      RECT 165.660 177.205 165.870 177.275 ;
    END
  END rw0_wd_in[198]
  PIN rw0_wd_in[199]
    DIRECTION INPUT ;
    USE SIGNAL ;
    SHAPE ABUTMENT ;
    PORT
      LAYER metal3 ;
      RECT 165.660 179.725 165.870 179.795 ;
    END
  END rw0_wd_in[199]
  PIN rw0_wd_in[200]
    DIRECTION INPUT ;
    USE SIGNAL ;
    SHAPE ABUTMENT ;
    PORT
      LAYER metal3 ;
      RECT 165.660 182.245 165.870 182.315 ;
    END
  END rw0_wd_in[200]
  PIN rw0_wd_in[201]
    DIRECTION INPUT ;
    USE SIGNAL ;
    SHAPE ABUTMENT ;
    PORT
      LAYER metal3 ;
      RECT 165.660 184.765 165.870 184.835 ;
    END
  END rw0_wd_in[201]
  PIN rw0_wd_in[202]
    DIRECTION INPUT ;
    USE SIGNAL ;
    SHAPE ABUTMENT ;
    PORT
      LAYER metal3 ;
      RECT 165.660 187.285 165.870 187.355 ;
    END
  END rw0_wd_in[202]
  PIN rw0_wd_in[203]
    DIRECTION INPUT ;
    USE SIGNAL ;
    SHAPE ABUTMENT ;
    PORT
      LAYER metal3 ;
      RECT 165.660 189.805 165.870 189.875 ;
    END
  END rw0_wd_in[203]
  PIN rw0_wd_in[204]
    DIRECTION INPUT ;
    USE SIGNAL ;
    SHAPE ABUTMENT ;
    PORT
      LAYER metal3 ;
      RECT 165.660 192.325 165.870 192.395 ;
    END
  END rw0_wd_in[204]
  PIN rw0_wd_in[205]
    DIRECTION INPUT ;
    USE SIGNAL ;
    SHAPE ABUTMENT ;
    PORT
      LAYER metal3 ;
      RECT 165.660 194.845 165.870 194.915 ;
    END
  END rw0_wd_in[205]
  PIN rw0_wd_in[206]
    DIRECTION INPUT ;
    USE SIGNAL ;
    SHAPE ABUTMENT ;
    PORT
      LAYER metal3 ;
      RECT 165.660 197.365 165.870 197.435 ;
    END
  END rw0_wd_in[206]
  PIN rw0_wd_in[207]
    DIRECTION INPUT ;
    USE SIGNAL ;
    SHAPE ABUTMENT ;
    PORT
      LAYER metal3 ;
      RECT 165.660 199.885 165.870 199.955 ;
    END
  END rw0_wd_in[207]
  PIN rw0_wd_in[208]
    DIRECTION INPUT ;
    USE SIGNAL ;
    SHAPE ABUTMENT ;
    PORT
      LAYER metal3 ;
      RECT 165.660 202.405 165.870 202.475 ;
    END
  END rw0_wd_in[208]
  PIN rw0_wd_in[209]
    DIRECTION INPUT ;
    USE SIGNAL ;
    SHAPE ABUTMENT ;
    PORT
      LAYER metal3 ;
      RECT 165.660 204.925 165.870 204.995 ;
    END
  END rw0_wd_in[209]
  PIN rw0_wd_in[210]
    DIRECTION INPUT ;
    USE SIGNAL ;
    SHAPE ABUTMENT ;
    PORT
      LAYER metal3 ;
      RECT 165.660 207.445 165.870 207.515 ;
    END
  END rw0_wd_in[210]
  PIN rw0_wd_in[211]
    DIRECTION INPUT ;
    USE SIGNAL ;
    SHAPE ABUTMENT ;
    PORT
      LAYER metal3 ;
      RECT 165.660 209.965 165.870 210.035 ;
    END
  END rw0_wd_in[211]
  PIN rw0_wd_in[212]
    DIRECTION INPUT ;
    USE SIGNAL ;
    SHAPE ABUTMENT ;
    PORT
      LAYER metal3 ;
      RECT 165.660 212.485 165.870 212.555 ;
    END
  END rw0_wd_in[212]
  PIN rw0_wd_in[213]
    DIRECTION INPUT ;
    USE SIGNAL ;
    SHAPE ABUTMENT ;
    PORT
      LAYER metal3 ;
      RECT 165.660 215.005 165.870 215.075 ;
    END
  END rw0_wd_in[213]
  PIN rw0_wd_in[214]
    DIRECTION INPUT ;
    USE SIGNAL ;
    SHAPE ABUTMENT ;
    PORT
      LAYER metal3 ;
      RECT 165.660 217.525 165.870 217.595 ;
    END
  END rw0_wd_in[214]
  PIN rw0_wd_in[215]
    DIRECTION INPUT ;
    USE SIGNAL ;
    SHAPE ABUTMENT ;
    PORT
      LAYER metal3 ;
      RECT 165.660 220.045 165.870 220.115 ;
    END
  END rw0_wd_in[215]
  PIN rw0_wd_in[216]
    DIRECTION INPUT ;
    USE SIGNAL ;
    SHAPE ABUTMENT ;
    PORT
      LAYER metal3 ;
      RECT 165.660 222.565 165.870 222.635 ;
    END
  END rw0_wd_in[216]
  PIN rw0_wd_in[217]
    DIRECTION INPUT ;
    USE SIGNAL ;
    SHAPE ABUTMENT ;
    PORT
      LAYER metal3 ;
      RECT 165.660 225.085 165.870 225.155 ;
    END
  END rw0_wd_in[217]
  PIN rw0_wd_in[218]
    DIRECTION INPUT ;
    USE SIGNAL ;
    SHAPE ABUTMENT ;
    PORT
      LAYER metal3 ;
      RECT 165.660 227.605 165.870 227.675 ;
    END
  END rw0_wd_in[218]
  PIN rw0_wd_in[219]
    DIRECTION INPUT ;
    USE SIGNAL ;
    SHAPE ABUTMENT ;
    PORT
      LAYER metal3 ;
      RECT 165.660 230.125 165.870 230.195 ;
    END
  END rw0_wd_in[219]
  PIN rw0_wd_in[220]
    DIRECTION INPUT ;
    USE SIGNAL ;
    SHAPE ABUTMENT ;
    PORT
      LAYER metal3 ;
      RECT 165.660 232.645 165.870 232.715 ;
    END
  END rw0_wd_in[220]
  PIN rw0_wd_in[221]
    DIRECTION INPUT ;
    USE SIGNAL ;
    SHAPE ABUTMENT ;
    PORT
      LAYER metal3 ;
      RECT 165.660 235.165 165.870 235.235 ;
    END
  END rw0_wd_in[221]
  PIN rw0_wd_in[222]
    DIRECTION INPUT ;
    USE SIGNAL ;
    SHAPE ABUTMENT ;
    PORT
      LAYER metal3 ;
      RECT 165.660 237.685 165.870 237.755 ;
    END
  END rw0_wd_in[222]
  PIN rw0_wd_in[223]
    DIRECTION INPUT ;
    USE SIGNAL ;
    SHAPE ABUTMENT ;
    PORT
      LAYER metal3 ;
      RECT 165.660 240.205 165.870 240.275 ;
    END
  END rw0_wd_in[223]
  PIN rw0_wd_in[224]
    DIRECTION INPUT ;
    USE SIGNAL ;
    SHAPE ABUTMENT ;
    PORT
      LAYER metal3 ;
      RECT 165.660 242.725 165.870 242.795 ;
    END
  END rw0_wd_in[224]
  PIN rw0_wd_in[225]
    DIRECTION INPUT ;
    USE SIGNAL ;
    SHAPE ABUTMENT ;
    PORT
      LAYER metal3 ;
      RECT 165.660 245.245 165.870 245.315 ;
    END
  END rw0_wd_in[225]
  PIN rw0_wd_in[226]
    DIRECTION INPUT ;
    USE SIGNAL ;
    SHAPE ABUTMENT ;
    PORT
      LAYER metal3 ;
      RECT 165.660 247.765 165.870 247.835 ;
    END
  END rw0_wd_in[226]
  PIN rw0_wd_in[227]
    DIRECTION INPUT ;
    USE SIGNAL ;
    SHAPE ABUTMENT ;
    PORT
      LAYER metal3 ;
      RECT 165.660 250.285 165.870 250.355 ;
    END
  END rw0_wd_in[227]
  PIN rw0_wd_in[228]
    DIRECTION INPUT ;
    USE SIGNAL ;
    SHAPE ABUTMENT ;
    PORT
      LAYER metal3 ;
      RECT 165.660 252.805 165.870 252.875 ;
    END
  END rw0_wd_in[228]
  PIN rw0_wd_in[229]
    DIRECTION INPUT ;
    USE SIGNAL ;
    SHAPE ABUTMENT ;
    PORT
      LAYER metal3 ;
      RECT 165.660 255.325 165.870 255.395 ;
    END
  END rw0_wd_in[229]
  PIN rw0_wd_in[230]
    DIRECTION INPUT ;
    USE SIGNAL ;
    SHAPE ABUTMENT ;
    PORT
      LAYER metal3 ;
      RECT 165.660 257.845 165.870 257.915 ;
    END
  END rw0_wd_in[230]
  PIN rw0_wd_in[231]
    DIRECTION INPUT ;
    USE SIGNAL ;
    SHAPE ABUTMENT ;
    PORT
      LAYER metal3 ;
      RECT 165.660 260.365 165.870 260.435 ;
    END
  END rw0_wd_in[231]
  PIN rw0_wd_in[232]
    DIRECTION INPUT ;
    USE SIGNAL ;
    SHAPE ABUTMENT ;
    PORT
      LAYER metal3 ;
      RECT 165.660 262.885 165.870 262.955 ;
    END
  END rw0_wd_in[232]
  PIN rw0_wd_in[233]
    DIRECTION INPUT ;
    USE SIGNAL ;
    SHAPE ABUTMENT ;
    PORT
      LAYER metal3 ;
      RECT 165.660 265.405 165.870 265.475 ;
    END
  END rw0_wd_in[233]
  PIN rw0_wd_in[234]
    DIRECTION INPUT ;
    USE SIGNAL ;
    SHAPE ABUTMENT ;
    PORT
      LAYER metal3 ;
      RECT 165.660 267.925 165.870 267.995 ;
    END
  END rw0_wd_in[234]
  PIN rw0_wd_in[235]
    DIRECTION INPUT ;
    USE SIGNAL ;
    SHAPE ABUTMENT ;
    PORT
      LAYER metal3 ;
      RECT 165.660 270.445 165.870 270.515 ;
    END
  END rw0_wd_in[235]
  PIN rw0_wd_in[236]
    DIRECTION INPUT ;
    USE SIGNAL ;
    SHAPE ABUTMENT ;
    PORT
      LAYER metal3 ;
      RECT 165.660 272.965 165.870 273.035 ;
    END
  END rw0_wd_in[236]
  PIN rw0_wd_in[237]
    DIRECTION INPUT ;
    USE SIGNAL ;
    SHAPE ABUTMENT ;
    PORT
      LAYER metal3 ;
      RECT 165.660 275.485 165.870 275.555 ;
    END
  END rw0_wd_in[237]
  PIN rw0_wd_in[238]
    DIRECTION INPUT ;
    USE SIGNAL ;
    SHAPE ABUTMENT ;
    PORT
      LAYER metal3 ;
      RECT 165.660 278.005 165.870 278.075 ;
    END
  END rw0_wd_in[238]
  PIN rw0_wd_in[239]
    DIRECTION INPUT ;
    USE SIGNAL ;
    SHAPE ABUTMENT ;
    PORT
      LAYER metal3 ;
      RECT 165.660 280.525 165.870 280.595 ;
    END
  END rw0_wd_in[239]
  PIN rw0_wd_in[240]
    DIRECTION INPUT ;
    USE SIGNAL ;
    SHAPE ABUTMENT ;
    PORT
      LAYER metal3 ;
      RECT 165.660 283.045 165.870 283.115 ;
    END
  END rw0_wd_in[240]
  PIN rw0_wd_in[241]
    DIRECTION INPUT ;
    USE SIGNAL ;
    SHAPE ABUTMENT ;
    PORT
      LAYER metal3 ;
      RECT 165.660 285.565 165.870 285.635 ;
    END
  END rw0_wd_in[241]
  PIN rw0_wd_in[242]
    DIRECTION INPUT ;
    USE SIGNAL ;
    SHAPE ABUTMENT ;
    PORT
      LAYER metal3 ;
      RECT 165.660 288.085 165.870 288.155 ;
    END
  END rw0_wd_in[242]
  PIN rw0_wd_in[243]
    DIRECTION INPUT ;
    USE SIGNAL ;
    SHAPE ABUTMENT ;
    PORT
      LAYER metal3 ;
      RECT 165.660 290.605 165.870 290.675 ;
    END
  END rw0_wd_in[243]
  PIN rw0_wd_in[244]
    DIRECTION INPUT ;
    USE SIGNAL ;
    SHAPE ABUTMENT ;
    PORT
      LAYER metal3 ;
      RECT 165.660 293.125 165.870 293.195 ;
    END
  END rw0_wd_in[244]
  PIN rw0_wd_in[245]
    DIRECTION INPUT ;
    USE SIGNAL ;
    SHAPE ABUTMENT ;
    PORT
      LAYER metal3 ;
      RECT 165.660 295.645 165.870 295.715 ;
    END
  END rw0_wd_in[245]
  PIN rw0_wd_in[246]
    DIRECTION INPUT ;
    USE SIGNAL ;
    SHAPE ABUTMENT ;
    PORT
      LAYER metal3 ;
      RECT 165.660 298.165 165.870 298.235 ;
    END
  END rw0_wd_in[246]
  PIN rw0_wd_in[247]
    DIRECTION INPUT ;
    USE SIGNAL ;
    SHAPE ABUTMENT ;
    PORT
      LAYER metal3 ;
      RECT 165.660 300.685 165.870 300.755 ;
    END
  END rw0_wd_in[247]
  PIN rw0_wd_in[248]
    DIRECTION INPUT ;
    USE SIGNAL ;
    SHAPE ABUTMENT ;
    PORT
      LAYER metal3 ;
      RECT 165.660 303.205 165.870 303.275 ;
    END
  END rw0_wd_in[248]
  PIN rw0_wd_in[249]
    DIRECTION INPUT ;
    USE SIGNAL ;
    SHAPE ABUTMENT ;
    PORT
      LAYER metal3 ;
      RECT 165.660 305.725 165.870 305.795 ;
    END
  END rw0_wd_in[249]
  PIN rw0_wd_in[250]
    DIRECTION INPUT ;
    USE SIGNAL ;
    SHAPE ABUTMENT ;
    PORT
      LAYER metal3 ;
      RECT 165.660 308.245 165.870 308.315 ;
    END
  END rw0_wd_in[250]
  PIN rw0_wd_in[251]
    DIRECTION INPUT ;
    USE SIGNAL ;
    SHAPE ABUTMENT ;
    PORT
      LAYER metal3 ;
      RECT 165.660 310.765 165.870 310.835 ;
    END
  END rw0_wd_in[251]
  PIN rw0_wd_in[252]
    DIRECTION INPUT ;
    USE SIGNAL ;
    SHAPE ABUTMENT ;
    PORT
      LAYER metal3 ;
      RECT 165.660 313.285 165.870 313.355 ;
    END
  END rw0_wd_in[252]
  PIN rw0_wd_in[253]
    DIRECTION INPUT ;
    USE SIGNAL ;
    SHAPE ABUTMENT ;
    PORT
      LAYER metal3 ;
      RECT 165.660 315.805 165.870 315.875 ;
    END
  END rw0_wd_in[253]
  PIN rw0_wd_in[254]
    DIRECTION INPUT ;
    USE SIGNAL ;
    SHAPE ABUTMENT ;
    PORT
      LAYER metal3 ;
      RECT 165.660 318.325 165.870 318.395 ;
    END
  END rw0_wd_in[254]
  PIN rw0_wd_in[255]
    DIRECTION INPUT ;
    USE SIGNAL ;
    SHAPE ABUTMENT ;
    PORT
      LAYER metal3 ;
      RECT 165.660 320.845 165.870 320.915 ;
    END
  END rw0_wd_in[255]
  PIN rw0_wd_in[256]
    DIRECTION INPUT ;
    USE SIGNAL ;
    SHAPE ABUTMENT ;
    PORT
      LAYER metal2 ;
      RECT 1.105 0.000 1.175 0.210 ;
    END
  END rw0_wd_in[256]
  PIN rw0_wd_in[257]
    DIRECTION INPUT ;
    USE SIGNAL ;
    SHAPE ABUTMENT ;
    PORT
      LAYER metal2 ;
      RECT 1.295 0.000 1.365 0.210 ;
    END
  END rw0_wd_in[257]
  PIN rw0_wd_in[258]
    DIRECTION INPUT ;
    USE SIGNAL ;
    SHAPE ABUTMENT ;
    PORT
      LAYER metal2 ;
      RECT 1.485 0.000 1.555 0.210 ;
    END
  END rw0_wd_in[258]
  PIN rw0_wd_in[259]
    DIRECTION INPUT ;
    USE SIGNAL ;
    SHAPE ABUTMENT ;
    PORT
      LAYER metal2 ;
      RECT 1.675 0.000 1.745 0.210 ;
    END
  END rw0_wd_in[259]
  PIN rw0_wd_in[260]
    DIRECTION INPUT ;
    USE SIGNAL ;
    SHAPE ABUTMENT ;
    PORT
      LAYER metal2 ;
      RECT 1.865 0.000 1.935 0.210 ;
    END
  END rw0_wd_in[260]
  PIN rw0_wd_in[261]
    DIRECTION INPUT ;
    USE SIGNAL ;
    SHAPE ABUTMENT ;
    PORT
      LAYER metal2 ;
      RECT 2.055 0.000 2.125 0.210 ;
    END
  END rw0_wd_in[261]
  PIN rw0_wd_in[262]
    DIRECTION INPUT ;
    USE SIGNAL ;
    SHAPE ABUTMENT ;
    PORT
      LAYER metal2 ;
      RECT 2.245 0.000 2.315 0.210 ;
    END
  END rw0_wd_in[262]
  PIN rw0_wd_in[263]
    DIRECTION INPUT ;
    USE SIGNAL ;
    SHAPE ABUTMENT ;
    PORT
      LAYER metal2 ;
      RECT 2.435 0.000 2.505 0.210 ;
    END
  END rw0_wd_in[263]
  PIN rw0_wd_in[264]
    DIRECTION INPUT ;
    USE SIGNAL ;
    SHAPE ABUTMENT ;
    PORT
      LAYER metal2 ;
      RECT 2.625 0.000 2.695 0.210 ;
    END
  END rw0_wd_in[264]
  PIN rw0_wd_in[265]
    DIRECTION INPUT ;
    USE SIGNAL ;
    SHAPE ABUTMENT ;
    PORT
      LAYER metal2 ;
      RECT 2.815 0.000 2.885 0.210 ;
    END
  END rw0_wd_in[265]
  PIN rw0_wd_in[266]
    DIRECTION INPUT ;
    USE SIGNAL ;
    SHAPE ABUTMENT ;
    PORT
      LAYER metal2 ;
      RECT 3.005 0.000 3.075 0.210 ;
    END
  END rw0_wd_in[266]
  PIN rw0_wd_in[267]
    DIRECTION INPUT ;
    USE SIGNAL ;
    SHAPE ABUTMENT ;
    PORT
      LAYER metal2 ;
      RECT 3.195 0.000 3.265 0.210 ;
    END
  END rw0_wd_in[267]
  PIN rw0_wd_in[268]
    DIRECTION INPUT ;
    USE SIGNAL ;
    SHAPE ABUTMENT ;
    PORT
      LAYER metal2 ;
      RECT 3.385 0.000 3.455 0.210 ;
    END
  END rw0_wd_in[268]
  PIN rw0_wd_in[269]
    DIRECTION INPUT ;
    USE SIGNAL ;
    SHAPE ABUTMENT ;
    PORT
      LAYER metal2 ;
      RECT 3.575 0.000 3.645 0.210 ;
    END
  END rw0_wd_in[269]
  PIN rw0_wd_in[270]
    DIRECTION INPUT ;
    USE SIGNAL ;
    SHAPE ABUTMENT ;
    PORT
      LAYER metal2 ;
      RECT 3.765 0.000 3.835 0.210 ;
    END
  END rw0_wd_in[270]
  PIN rw0_wd_in[271]
    DIRECTION INPUT ;
    USE SIGNAL ;
    SHAPE ABUTMENT ;
    PORT
      LAYER metal2 ;
      RECT 3.955 0.000 4.025 0.210 ;
    END
  END rw0_wd_in[271]
  PIN rw0_wd_in[272]
    DIRECTION INPUT ;
    USE SIGNAL ;
    SHAPE ABUTMENT ;
    PORT
      LAYER metal2 ;
      RECT 4.145 0.000 4.215 0.210 ;
    END
  END rw0_wd_in[272]
  PIN rw0_wd_in[273]
    DIRECTION INPUT ;
    USE SIGNAL ;
    SHAPE ABUTMENT ;
    PORT
      LAYER metal2 ;
      RECT 4.335 0.000 4.405 0.210 ;
    END
  END rw0_wd_in[273]
  PIN rw0_wd_in[274]
    DIRECTION INPUT ;
    USE SIGNAL ;
    SHAPE ABUTMENT ;
    PORT
      LAYER metal2 ;
      RECT 4.525 0.000 4.595 0.210 ;
    END
  END rw0_wd_in[274]
  PIN rw0_wd_in[275]
    DIRECTION INPUT ;
    USE SIGNAL ;
    SHAPE ABUTMENT ;
    PORT
      LAYER metal2 ;
      RECT 4.715 0.000 4.785 0.210 ;
    END
  END rw0_wd_in[275]
  PIN rw0_wd_in[276]
    DIRECTION INPUT ;
    USE SIGNAL ;
    SHAPE ABUTMENT ;
    PORT
      LAYER metal2 ;
      RECT 4.905 0.000 4.975 0.210 ;
    END
  END rw0_wd_in[276]
  PIN rw0_wd_in[277]
    DIRECTION INPUT ;
    USE SIGNAL ;
    SHAPE ABUTMENT ;
    PORT
      LAYER metal2 ;
      RECT 5.095 0.000 5.165 0.210 ;
    END
  END rw0_wd_in[277]
  PIN rw0_wd_in[278]
    DIRECTION INPUT ;
    USE SIGNAL ;
    SHAPE ABUTMENT ;
    PORT
      LAYER metal2 ;
      RECT 5.285 0.000 5.355 0.210 ;
    END
  END rw0_wd_in[278]
  PIN rw0_wd_in[279]
    DIRECTION INPUT ;
    USE SIGNAL ;
    SHAPE ABUTMENT ;
    PORT
      LAYER metal2 ;
      RECT 5.475 0.000 5.545 0.210 ;
    END
  END rw0_wd_in[279]
  PIN rw0_wd_in[280]
    DIRECTION INPUT ;
    USE SIGNAL ;
    SHAPE ABUTMENT ;
    PORT
      LAYER metal2 ;
      RECT 5.665 0.000 5.735 0.210 ;
    END
  END rw0_wd_in[280]
  PIN rw0_wd_in[281]
    DIRECTION INPUT ;
    USE SIGNAL ;
    SHAPE ABUTMENT ;
    PORT
      LAYER metal2 ;
      RECT 5.855 0.000 5.925 0.210 ;
    END
  END rw0_wd_in[281]
  PIN rw0_wd_in[282]
    DIRECTION INPUT ;
    USE SIGNAL ;
    SHAPE ABUTMENT ;
    PORT
      LAYER metal2 ;
      RECT 6.045 0.000 6.115 0.210 ;
    END
  END rw0_wd_in[282]
  PIN rw0_wd_in[283]
    DIRECTION INPUT ;
    USE SIGNAL ;
    SHAPE ABUTMENT ;
    PORT
      LAYER metal2 ;
      RECT 6.235 0.000 6.305 0.210 ;
    END
  END rw0_wd_in[283]
  PIN rw0_wd_in[284]
    DIRECTION INPUT ;
    USE SIGNAL ;
    SHAPE ABUTMENT ;
    PORT
      LAYER metal2 ;
      RECT 6.425 0.000 6.495 0.210 ;
    END
  END rw0_wd_in[284]
  PIN rw0_wd_in[285]
    DIRECTION INPUT ;
    USE SIGNAL ;
    SHAPE ABUTMENT ;
    PORT
      LAYER metal2 ;
      RECT 6.615 0.000 6.685 0.210 ;
    END
  END rw0_wd_in[285]
  PIN rw0_wd_in[286]
    DIRECTION INPUT ;
    USE SIGNAL ;
    SHAPE ABUTMENT ;
    PORT
      LAYER metal2 ;
      RECT 6.805 0.000 6.875 0.210 ;
    END
  END rw0_wd_in[286]
  PIN rw0_wd_in[287]
    DIRECTION INPUT ;
    USE SIGNAL ;
    SHAPE ABUTMENT ;
    PORT
      LAYER metal2 ;
      RECT 6.995 0.000 7.065 0.210 ;
    END
  END rw0_wd_in[287]
  PIN rw0_wd_in[288]
    DIRECTION INPUT ;
    USE SIGNAL ;
    SHAPE ABUTMENT ;
    PORT
      LAYER metal2 ;
      RECT 7.185 0.000 7.255 0.210 ;
    END
  END rw0_wd_in[288]
  PIN rw0_wd_in[289]
    DIRECTION INPUT ;
    USE SIGNAL ;
    SHAPE ABUTMENT ;
    PORT
      LAYER metal2 ;
      RECT 7.375 0.000 7.445 0.210 ;
    END
  END rw0_wd_in[289]
  PIN rw0_wd_in[290]
    DIRECTION INPUT ;
    USE SIGNAL ;
    SHAPE ABUTMENT ;
    PORT
      LAYER metal2 ;
      RECT 7.565 0.000 7.635 0.210 ;
    END
  END rw0_wd_in[290]
  PIN rw0_wd_in[291]
    DIRECTION INPUT ;
    USE SIGNAL ;
    SHAPE ABUTMENT ;
    PORT
      LAYER metal2 ;
      RECT 7.755 0.000 7.825 0.210 ;
    END
  END rw0_wd_in[291]
  PIN rw0_wd_in[292]
    DIRECTION INPUT ;
    USE SIGNAL ;
    SHAPE ABUTMENT ;
    PORT
      LAYER metal2 ;
      RECT 7.945 0.000 8.015 0.210 ;
    END
  END rw0_wd_in[292]
  PIN rw0_wd_in[293]
    DIRECTION INPUT ;
    USE SIGNAL ;
    SHAPE ABUTMENT ;
    PORT
      LAYER metal2 ;
      RECT 8.135 0.000 8.205 0.210 ;
    END
  END rw0_wd_in[293]
  PIN rw0_wd_in[294]
    DIRECTION INPUT ;
    USE SIGNAL ;
    SHAPE ABUTMENT ;
    PORT
      LAYER metal2 ;
      RECT 8.325 0.000 8.395 0.210 ;
    END
  END rw0_wd_in[294]
  PIN rw0_wd_in[295]
    DIRECTION INPUT ;
    USE SIGNAL ;
    SHAPE ABUTMENT ;
    PORT
      LAYER metal2 ;
      RECT 8.515 0.000 8.585 0.210 ;
    END
  END rw0_wd_in[295]
  PIN rw0_wd_in[296]
    DIRECTION INPUT ;
    USE SIGNAL ;
    SHAPE ABUTMENT ;
    PORT
      LAYER metal2 ;
      RECT 8.705 0.000 8.775 0.210 ;
    END
  END rw0_wd_in[296]
  PIN rw0_wd_in[297]
    DIRECTION INPUT ;
    USE SIGNAL ;
    SHAPE ABUTMENT ;
    PORT
      LAYER metal2 ;
      RECT 8.895 0.000 8.965 0.210 ;
    END
  END rw0_wd_in[297]
  PIN rw0_wd_in[298]
    DIRECTION INPUT ;
    USE SIGNAL ;
    SHAPE ABUTMENT ;
    PORT
      LAYER metal2 ;
      RECT 9.085 0.000 9.155 0.210 ;
    END
  END rw0_wd_in[298]
  PIN rw0_wd_in[299]
    DIRECTION INPUT ;
    USE SIGNAL ;
    SHAPE ABUTMENT ;
    PORT
      LAYER metal2 ;
      RECT 9.275 0.000 9.345 0.210 ;
    END
  END rw0_wd_in[299]
  PIN rw0_wd_in[300]
    DIRECTION INPUT ;
    USE SIGNAL ;
    SHAPE ABUTMENT ;
    PORT
      LAYER metal2 ;
      RECT 9.465 0.000 9.535 0.210 ;
    END
  END rw0_wd_in[300]
  PIN rw0_wd_in[301]
    DIRECTION INPUT ;
    USE SIGNAL ;
    SHAPE ABUTMENT ;
    PORT
      LAYER metal2 ;
      RECT 9.655 0.000 9.725 0.210 ;
    END
  END rw0_wd_in[301]
  PIN rw0_wd_in[302]
    DIRECTION INPUT ;
    USE SIGNAL ;
    SHAPE ABUTMENT ;
    PORT
      LAYER metal2 ;
      RECT 9.845 0.000 9.915 0.210 ;
    END
  END rw0_wd_in[302]
  PIN rw0_wd_in[303]
    DIRECTION INPUT ;
    USE SIGNAL ;
    SHAPE ABUTMENT ;
    PORT
      LAYER metal2 ;
      RECT 10.035 0.000 10.105 0.210 ;
    END
  END rw0_wd_in[303]
  PIN rw0_wd_in[304]
    DIRECTION INPUT ;
    USE SIGNAL ;
    SHAPE ABUTMENT ;
    PORT
      LAYER metal2 ;
      RECT 10.225 0.000 10.295 0.210 ;
    END
  END rw0_wd_in[304]
  PIN rw0_wd_in[305]
    DIRECTION INPUT ;
    USE SIGNAL ;
    SHAPE ABUTMENT ;
    PORT
      LAYER metal2 ;
      RECT 10.415 0.000 10.485 0.210 ;
    END
  END rw0_wd_in[305]
  PIN rw0_wd_in[306]
    DIRECTION INPUT ;
    USE SIGNAL ;
    SHAPE ABUTMENT ;
    PORT
      LAYER metal2 ;
      RECT 10.605 0.000 10.675 0.210 ;
    END
  END rw0_wd_in[306]
  PIN rw0_wd_in[307]
    DIRECTION INPUT ;
    USE SIGNAL ;
    SHAPE ABUTMENT ;
    PORT
      LAYER metal2 ;
      RECT 10.795 0.000 10.865 0.210 ;
    END
  END rw0_wd_in[307]
  PIN rw0_wd_in[308]
    DIRECTION INPUT ;
    USE SIGNAL ;
    SHAPE ABUTMENT ;
    PORT
      LAYER metal2 ;
      RECT 10.985 0.000 11.055 0.210 ;
    END
  END rw0_wd_in[308]
  PIN rw0_wd_in[309]
    DIRECTION INPUT ;
    USE SIGNAL ;
    SHAPE ABUTMENT ;
    PORT
      LAYER metal2 ;
      RECT 11.175 0.000 11.245 0.210 ;
    END
  END rw0_wd_in[309]
  PIN rw0_wd_in[310]
    DIRECTION INPUT ;
    USE SIGNAL ;
    SHAPE ABUTMENT ;
    PORT
      LAYER metal2 ;
      RECT 11.365 0.000 11.435 0.210 ;
    END
  END rw0_wd_in[310]
  PIN rw0_wd_in[311]
    DIRECTION INPUT ;
    USE SIGNAL ;
    SHAPE ABUTMENT ;
    PORT
      LAYER metal2 ;
      RECT 11.555 0.000 11.625 0.210 ;
    END
  END rw0_wd_in[311]
  PIN rw0_wd_in[312]
    DIRECTION INPUT ;
    USE SIGNAL ;
    SHAPE ABUTMENT ;
    PORT
      LAYER metal2 ;
      RECT 11.745 0.000 11.815 0.210 ;
    END
  END rw0_wd_in[312]
  PIN rw0_wd_in[313]
    DIRECTION INPUT ;
    USE SIGNAL ;
    SHAPE ABUTMENT ;
    PORT
      LAYER metal2 ;
      RECT 11.935 0.000 12.005 0.210 ;
    END
  END rw0_wd_in[313]
  PIN rw0_wd_in[314]
    DIRECTION INPUT ;
    USE SIGNAL ;
    SHAPE ABUTMENT ;
    PORT
      LAYER metal2 ;
      RECT 12.125 0.000 12.195 0.210 ;
    END
  END rw0_wd_in[314]
  PIN rw0_wd_in[315]
    DIRECTION INPUT ;
    USE SIGNAL ;
    SHAPE ABUTMENT ;
    PORT
      LAYER metal2 ;
      RECT 12.315 0.000 12.385 0.210 ;
    END
  END rw0_wd_in[315]
  PIN rw0_wd_in[316]
    DIRECTION INPUT ;
    USE SIGNAL ;
    SHAPE ABUTMENT ;
    PORT
      LAYER metal2 ;
      RECT 12.505 0.000 12.575 0.210 ;
    END
  END rw0_wd_in[316]
  PIN rw0_wd_in[317]
    DIRECTION INPUT ;
    USE SIGNAL ;
    SHAPE ABUTMENT ;
    PORT
      LAYER metal2 ;
      RECT 12.695 0.000 12.765 0.210 ;
    END
  END rw0_wd_in[317]
  PIN rw0_wd_in[318]
    DIRECTION INPUT ;
    USE SIGNAL ;
    SHAPE ABUTMENT ;
    PORT
      LAYER metal2 ;
      RECT 12.885 0.000 12.955 0.210 ;
    END
  END rw0_wd_in[318]
  PIN rw0_wd_in[319]
    DIRECTION INPUT ;
    USE SIGNAL ;
    SHAPE ABUTMENT ;
    PORT
      LAYER metal2 ;
      RECT 13.075 0.000 13.145 0.210 ;
    END
  END rw0_wd_in[319]
  PIN rw0_wd_in[320]
    DIRECTION INPUT ;
    USE SIGNAL ;
    SHAPE ABUTMENT ;
    PORT
      LAYER metal2 ;
      RECT 13.265 0.000 13.335 0.210 ;
    END
  END rw0_wd_in[320]
  PIN rw0_wd_in[321]
    DIRECTION INPUT ;
    USE SIGNAL ;
    SHAPE ABUTMENT ;
    PORT
      LAYER metal2 ;
      RECT 13.455 0.000 13.525 0.210 ;
    END
  END rw0_wd_in[321]
  PIN rw0_wd_in[322]
    DIRECTION INPUT ;
    USE SIGNAL ;
    SHAPE ABUTMENT ;
    PORT
      LAYER metal2 ;
      RECT 13.645 0.000 13.715 0.210 ;
    END
  END rw0_wd_in[322]
  PIN rw0_wd_in[323]
    DIRECTION INPUT ;
    USE SIGNAL ;
    SHAPE ABUTMENT ;
    PORT
      LAYER metal2 ;
      RECT 13.835 0.000 13.905 0.210 ;
    END
  END rw0_wd_in[323]
  PIN rw0_wd_in[324]
    DIRECTION INPUT ;
    USE SIGNAL ;
    SHAPE ABUTMENT ;
    PORT
      LAYER metal2 ;
      RECT 14.025 0.000 14.095 0.210 ;
    END
  END rw0_wd_in[324]
  PIN rw0_wd_in[325]
    DIRECTION INPUT ;
    USE SIGNAL ;
    SHAPE ABUTMENT ;
    PORT
      LAYER metal2 ;
      RECT 14.215 0.000 14.285 0.210 ;
    END
  END rw0_wd_in[325]
  PIN rw0_wd_in[326]
    DIRECTION INPUT ;
    USE SIGNAL ;
    SHAPE ABUTMENT ;
    PORT
      LAYER metal2 ;
      RECT 14.405 0.000 14.475 0.210 ;
    END
  END rw0_wd_in[326]
  PIN rw0_wd_in[327]
    DIRECTION INPUT ;
    USE SIGNAL ;
    SHAPE ABUTMENT ;
    PORT
      LAYER metal2 ;
      RECT 14.595 0.000 14.665 0.210 ;
    END
  END rw0_wd_in[327]
  PIN rw0_wd_in[328]
    DIRECTION INPUT ;
    USE SIGNAL ;
    SHAPE ABUTMENT ;
    PORT
      LAYER metal2 ;
      RECT 14.785 0.000 14.855 0.210 ;
    END
  END rw0_wd_in[328]
  PIN rw0_wd_in[329]
    DIRECTION INPUT ;
    USE SIGNAL ;
    SHAPE ABUTMENT ;
    PORT
      LAYER metal2 ;
      RECT 14.975 0.000 15.045 0.210 ;
    END
  END rw0_wd_in[329]
  PIN rw0_wd_in[330]
    DIRECTION INPUT ;
    USE SIGNAL ;
    SHAPE ABUTMENT ;
    PORT
      LAYER metal2 ;
      RECT 15.165 0.000 15.235 0.210 ;
    END
  END rw0_wd_in[330]
  PIN rw0_wd_in[331]
    DIRECTION INPUT ;
    USE SIGNAL ;
    SHAPE ABUTMENT ;
    PORT
      LAYER metal2 ;
      RECT 15.355 0.000 15.425 0.210 ;
    END
  END rw0_wd_in[331]
  PIN rw0_wd_in[332]
    DIRECTION INPUT ;
    USE SIGNAL ;
    SHAPE ABUTMENT ;
    PORT
      LAYER metal2 ;
      RECT 15.545 0.000 15.615 0.210 ;
    END
  END rw0_wd_in[332]
  PIN rw0_wd_in[333]
    DIRECTION INPUT ;
    USE SIGNAL ;
    SHAPE ABUTMENT ;
    PORT
      LAYER metal2 ;
      RECT 15.735 0.000 15.805 0.210 ;
    END
  END rw0_wd_in[333]
  PIN rw0_wd_in[334]
    DIRECTION INPUT ;
    USE SIGNAL ;
    SHAPE ABUTMENT ;
    PORT
      LAYER metal2 ;
      RECT 15.925 0.000 15.995 0.210 ;
    END
  END rw0_wd_in[334]
  PIN rw0_wd_in[335]
    DIRECTION INPUT ;
    USE SIGNAL ;
    SHAPE ABUTMENT ;
    PORT
      LAYER metal2 ;
      RECT 16.115 0.000 16.185 0.210 ;
    END
  END rw0_wd_in[335]
  PIN rw0_wd_in[336]
    DIRECTION INPUT ;
    USE SIGNAL ;
    SHAPE ABUTMENT ;
    PORT
      LAYER metal2 ;
      RECT 16.305 0.000 16.375 0.210 ;
    END
  END rw0_wd_in[336]
  PIN rw0_wd_in[337]
    DIRECTION INPUT ;
    USE SIGNAL ;
    SHAPE ABUTMENT ;
    PORT
      LAYER metal2 ;
      RECT 16.495 0.000 16.565 0.210 ;
    END
  END rw0_wd_in[337]
  PIN rw0_wd_in[338]
    DIRECTION INPUT ;
    USE SIGNAL ;
    SHAPE ABUTMENT ;
    PORT
      LAYER metal2 ;
      RECT 16.685 0.000 16.755 0.210 ;
    END
  END rw0_wd_in[338]
  PIN rw0_wd_in[339]
    DIRECTION INPUT ;
    USE SIGNAL ;
    SHAPE ABUTMENT ;
    PORT
      LAYER metal2 ;
      RECT 16.875 0.000 16.945 0.210 ;
    END
  END rw0_wd_in[339]
  PIN rw0_wd_in[340]
    DIRECTION INPUT ;
    USE SIGNAL ;
    SHAPE ABUTMENT ;
    PORT
      LAYER metal2 ;
      RECT 17.065 0.000 17.135 0.210 ;
    END
  END rw0_wd_in[340]
  PIN rw0_wd_in[341]
    DIRECTION INPUT ;
    USE SIGNAL ;
    SHAPE ABUTMENT ;
    PORT
      LAYER metal2 ;
      RECT 17.255 0.000 17.325 0.210 ;
    END
  END rw0_wd_in[341]
  PIN rw0_wd_in[342]
    DIRECTION INPUT ;
    USE SIGNAL ;
    SHAPE ABUTMENT ;
    PORT
      LAYER metal2 ;
      RECT 17.445 0.000 17.515 0.210 ;
    END
  END rw0_wd_in[342]
  PIN rw0_wd_in[343]
    DIRECTION INPUT ;
    USE SIGNAL ;
    SHAPE ABUTMENT ;
    PORT
      LAYER metal2 ;
      RECT 17.635 0.000 17.705 0.210 ;
    END
  END rw0_wd_in[343]
  PIN rw0_wd_in[344]
    DIRECTION INPUT ;
    USE SIGNAL ;
    SHAPE ABUTMENT ;
    PORT
      LAYER metal2 ;
      RECT 17.825 0.000 17.895 0.210 ;
    END
  END rw0_wd_in[344]
  PIN rw0_wd_in[345]
    DIRECTION INPUT ;
    USE SIGNAL ;
    SHAPE ABUTMENT ;
    PORT
      LAYER metal2 ;
      RECT 18.015 0.000 18.085 0.210 ;
    END
  END rw0_wd_in[345]
  PIN rw0_wd_in[346]
    DIRECTION INPUT ;
    USE SIGNAL ;
    SHAPE ABUTMENT ;
    PORT
      LAYER metal2 ;
      RECT 18.205 0.000 18.275 0.210 ;
    END
  END rw0_wd_in[346]
  PIN rw0_wd_in[347]
    DIRECTION INPUT ;
    USE SIGNAL ;
    SHAPE ABUTMENT ;
    PORT
      LAYER metal2 ;
      RECT 18.395 0.000 18.465 0.210 ;
    END
  END rw0_wd_in[347]
  PIN rw0_wd_in[348]
    DIRECTION INPUT ;
    USE SIGNAL ;
    SHAPE ABUTMENT ;
    PORT
      LAYER metal2 ;
      RECT 18.585 0.000 18.655 0.210 ;
    END
  END rw0_wd_in[348]
  PIN rw0_wd_in[349]
    DIRECTION INPUT ;
    USE SIGNAL ;
    SHAPE ABUTMENT ;
    PORT
      LAYER metal2 ;
      RECT 18.775 0.000 18.845 0.210 ;
    END
  END rw0_wd_in[349]
  PIN rw0_wd_in[350]
    DIRECTION INPUT ;
    USE SIGNAL ;
    SHAPE ABUTMENT ;
    PORT
      LAYER metal2 ;
      RECT 18.965 0.000 19.035 0.210 ;
    END
  END rw0_wd_in[350]
  PIN rw0_wd_in[351]
    DIRECTION INPUT ;
    USE SIGNAL ;
    SHAPE ABUTMENT ;
    PORT
      LAYER metal2 ;
      RECT 19.155 0.000 19.225 0.210 ;
    END
  END rw0_wd_in[351]
  PIN rw0_wd_in[352]
    DIRECTION INPUT ;
    USE SIGNAL ;
    SHAPE ABUTMENT ;
    PORT
      LAYER metal2 ;
      RECT 19.345 0.000 19.415 0.210 ;
    END
  END rw0_wd_in[352]
  PIN rw0_wd_in[353]
    DIRECTION INPUT ;
    USE SIGNAL ;
    SHAPE ABUTMENT ;
    PORT
      LAYER metal2 ;
      RECT 19.535 0.000 19.605 0.210 ;
    END
  END rw0_wd_in[353]
  PIN rw0_wd_in[354]
    DIRECTION INPUT ;
    USE SIGNAL ;
    SHAPE ABUTMENT ;
    PORT
      LAYER metal2 ;
      RECT 19.725 0.000 19.795 0.210 ;
    END
  END rw0_wd_in[354]
  PIN rw0_wd_in[355]
    DIRECTION INPUT ;
    USE SIGNAL ;
    SHAPE ABUTMENT ;
    PORT
      LAYER metal2 ;
      RECT 19.915 0.000 19.985 0.210 ;
    END
  END rw0_wd_in[355]
  PIN rw0_wd_in[356]
    DIRECTION INPUT ;
    USE SIGNAL ;
    SHAPE ABUTMENT ;
    PORT
      LAYER metal2 ;
      RECT 20.105 0.000 20.175 0.210 ;
    END
  END rw0_wd_in[356]
  PIN rw0_wd_in[357]
    DIRECTION INPUT ;
    USE SIGNAL ;
    SHAPE ABUTMENT ;
    PORT
      LAYER metal2 ;
      RECT 20.295 0.000 20.365 0.210 ;
    END
  END rw0_wd_in[357]
  PIN rw0_wd_in[358]
    DIRECTION INPUT ;
    USE SIGNAL ;
    SHAPE ABUTMENT ;
    PORT
      LAYER metal2 ;
      RECT 20.485 0.000 20.555 0.210 ;
    END
  END rw0_wd_in[358]
  PIN rw0_wd_in[359]
    DIRECTION INPUT ;
    USE SIGNAL ;
    SHAPE ABUTMENT ;
    PORT
      LAYER metal2 ;
      RECT 20.675 0.000 20.745 0.210 ;
    END
  END rw0_wd_in[359]
  PIN rw0_wd_in[360]
    DIRECTION INPUT ;
    USE SIGNAL ;
    SHAPE ABUTMENT ;
    PORT
      LAYER metal2 ;
      RECT 20.865 0.000 20.935 0.210 ;
    END
  END rw0_wd_in[360]
  PIN rw0_wd_in[361]
    DIRECTION INPUT ;
    USE SIGNAL ;
    SHAPE ABUTMENT ;
    PORT
      LAYER metal2 ;
      RECT 21.055 0.000 21.125 0.210 ;
    END
  END rw0_wd_in[361]
  PIN rw0_wd_in[362]
    DIRECTION INPUT ;
    USE SIGNAL ;
    SHAPE ABUTMENT ;
    PORT
      LAYER metal2 ;
      RECT 21.245 0.000 21.315 0.210 ;
    END
  END rw0_wd_in[362]
  PIN rw0_wd_in[363]
    DIRECTION INPUT ;
    USE SIGNAL ;
    SHAPE ABUTMENT ;
    PORT
      LAYER metal2 ;
      RECT 21.435 0.000 21.505 0.210 ;
    END
  END rw0_wd_in[363]
  PIN rw0_wd_in[364]
    DIRECTION INPUT ;
    USE SIGNAL ;
    SHAPE ABUTMENT ;
    PORT
      LAYER metal2 ;
      RECT 21.625 0.000 21.695 0.210 ;
    END
  END rw0_wd_in[364]
  PIN rw0_wd_in[365]
    DIRECTION INPUT ;
    USE SIGNAL ;
    SHAPE ABUTMENT ;
    PORT
      LAYER metal2 ;
      RECT 21.815 0.000 21.885 0.210 ;
    END
  END rw0_wd_in[365]
  PIN rw0_wd_in[366]
    DIRECTION INPUT ;
    USE SIGNAL ;
    SHAPE ABUTMENT ;
    PORT
      LAYER metal2 ;
      RECT 22.005 0.000 22.075 0.210 ;
    END
  END rw0_wd_in[366]
  PIN rw0_wd_in[367]
    DIRECTION INPUT ;
    USE SIGNAL ;
    SHAPE ABUTMENT ;
    PORT
      LAYER metal2 ;
      RECT 22.195 0.000 22.265 0.210 ;
    END
  END rw0_wd_in[367]
  PIN rw0_wd_in[368]
    DIRECTION INPUT ;
    USE SIGNAL ;
    SHAPE ABUTMENT ;
    PORT
      LAYER metal2 ;
      RECT 22.385 0.000 22.455 0.210 ;
    END
  END rw0_wd_in[368]
  PIN rw0_wd_in[369]
    DIRECTION INPUT ;
    USE SIGNAL ;
    SHAPE ABUTMENT ;
    PORT
      LAYER metal2 ;
      RECT 22.575 0.000 22.645 0.210 ;
    END
  END rw0_wd_in[369]
  PIN rw0_wd_in[370]
    DIRECTION INPUT ;
    USE SIGNAL ;
    SHAPE ABUTMENT ;
    PORT
      LAYER metal2 ;
      RECT 22.765 0.000 22.835 0.210 ;
    END
  END rw0_wd_in[370]
  PIN rw0_wd_in[371]
    DIRECTION INPUT ;
    USE SIGNAL ;
    SHAPE ABUTMENT ;
    PORT
      LAYER metal2 ;
      RECT 22.955 0.000 23.025 0.210 ;
    END
  END rw0_wd_in[371]
  PIN rw0_wd_in[372]
    DIRECTION INPUT ;
    USE SIGNAL ;
    SHAPE ABUTMENT ;
    PORT
      LAYER metal2 ;
      RECT 23.145 0.000 23.215 0.210 ;
    END
  END rw0_wd_in[372]
  PIN rw0_wd_in[373]
    DIRECTION INPUT ;
    USE SIGNAL ;
    SHAPE ABUTMENT ;
    PORT
      LAYER metal2 ;
      RECT 23.335 0.000 23.405 0.210 ;
    END
  END rw0_wd_in[373]
  PIN rw0_wd_in[374]
    DIRECTION INPUT ;
    USE SIGNAL ;
    SHAPE ABUTMENT ;
    PORT
      LAYER metal2 ;
      RECT 23.525 0.000 23.595 0.210 ;
    END
  END rw0_wd_in[374]
  PIN rw0_wd_in[375]
    DIRECTION INPUT ;
    USE SIGNAL ;
    SHAPE ABUTMENT ;
    PORT
      LAYER metal2 ;
      RECT 23.715 0.000 23.785 0.210 ;
    END
  END rw0_wd_in[375]
  PIN rw0_wd_in[376]
    DIRECTION INPUT ;
    USE SIGNAL ;
    SHAPE ABUTMENT ;
    PORT
      LAYER metal2 ;
      RECT 23.905 0.000 23.975 0.210 ;
    END
  END rw0_wd_in[376]
  PIN rw0_wd_in[377]
    DIRECTION INPUT ;
    USE SIGNAL ;
    SHAPE ABUTMENT ;
    PORT
      LAYER metal2 ;
      RECT 24.095 0.000 24.165 0.210 ;
    END
  END rw0_wd_in[377]
  PIN rw0_wd_in[378]
    DIRECTION INPUT ;
    USE SIGNAL ;
    SHAPE ABUTMENT ;
    PORT
      LAYER metal2 ;
      RECT 24.285 0.000 24.355 0.210 ;
    END
  END rw0_wd_in[378]
  PIN rw0_wd_in[379]
    DIRECTION INPUT ;
    USE SIGNAL ;
    SHAPE ABUTMENT ;
    PORT
      LAYER metal2 ;
      RECT 24.475 0.000 24.545 0.210 ;
    END
  END rw0_wd_in[379]
  PIN rw0_wd_in[380]
    DIRECTION INPUT ;
    USE SIGNAL ;
    SHAPE ABUTMENT ;
    PORT
      LAYER metal2 ;
      RECT 24.665 0.000 24.735 0.210 ;
    END
  END rw0_wd_in[380]
  PIN rw0_wd_in[381]
    DIRECTION INPUT ;
    USE SIGNAL ;
    SHAPE ABUTMENT ;
    PORT
      LAYER metal2 ;
      RECT 24.855 0.000 24.925 0.210 ;
    END
  END rw0_wd_in[381]
  PIN rw0_wd_in[382]
    DIRECTION INPUT ;
    USE SIGNAL ;
    SHAPE ABUTMENT ;
    PORT
      LAYER metal2 ;
      RECT 25.045 0.000 25.115 0.210 ;
    END
  END rw0_wd_in[382]
  PIN rw0_wd_in[383]
    DIRECTION INPUT ;
    USE SIGNAL ;
    SHAPE ABUTMENT ;
    PORT
      LAYER metal2 ;
      RECT 25.235 0.000 25.305 0.210 ;
    END
  END rw0_wd_in[383]
  PIN rw0_wd_in[384]
    DIRECTION INPUT ;
    USE SIGNAL ;
    SHAPE ABUTMENT ;
    PORT
      LAYER metal2 ;
      RECT 25.425 0.000 25.495 0.210 ;
    END
  END rw0_wd_in[384]
  PIN rw0_wd_in[385]
    DIRECTION INPUT ;
    USE SIGNAL ;
    SHAPE ABUTMENT ;
    PORT
      LAYER metal2 ;
      RECT 25.615 0.000 25.685 0.210 ;
    END
  END rw0_wd_in[385]
  PIN rw0_wd_in[386]
    DIRECTION INPUT ;
    USE SIGNAL ;
    SHAPE ABUTMENT ;
    PORT
      LAYER metal2 ;
      RECT 25.805 0.000 25.875 0.210 ;
    END
  END rw0_wd_in[386]
  PIN rw0_wd_in[387]
    DIRECTION INPUT ;
    USE SIGNAL ;
    SHAPE ABUTMENT ;
    PORT
      LAYER metal2 ;
      RECT 25.995 0.000 26.065 0.210 ;
    END
  END rw0_wd_in[387]
  PIN rw0_wd_in[388]
    DIRECTION INPUT ;
    USE SIGNAL ;
    SHAPE ABUTMENT ;
    PORT
      LAYER metal2 ;
      RECT 26.185 0.000 26.255 0.210 ;
    END
  END rw0_wd_in[388]
  PIN rw0_wd_in[389]
    DIRECTION INPUT ;
    USE SIGNAL ;
    SHAPE ABUTMENT ;
    PORT
      LAYER metal2 ;
      RECT 26.375 0.000 26.445 0.210 ;
    END
  END rw0_wd_in[389]
  PIN rw0_wd_in[390]
    DIRECTION INPUT ;
    USE SIGNAL ;
    SHAPE ABUTMENT ;
    PORT
      LAYER metal2 ;
      RECT 26.565 0.000 26.635 0.210 ;
    END
  END rw0_wd_in[390]
  PIN rw0_wd_in[391]
    DIRECTION INPUT ;
    USE SIGNAL ;
    SHAPE ABUTMENT ;
    PORT
      LAYER metal2 ;
      RECT 26.755 0.000 26.825 0.210 ;
    END
  END rw0_wd_in[391]
  PIN rw0_wd_in[392]
    DIRECTION INPUT ;
    USE SIGNAL ;
    SHAPE ABUTMENT ;
    PORT
      LAYER metal2 ;
      RECT 26.945 0.000 27.015 0.210 ;
    END
  END rw0_wd_in[392]
  PIN rw0_wd_in[393]
    DIRECTION INPUT ;
    USE SIGNAL ;
    SHAPE ABUTMENT ;
    PORT
      LAYER metal2 ;
      RECT 27.135 0.000 27.205 0.210 ;
    END
  END rw0_wd_in[393]
  PIN rw0_wd_in[394]
    DIRECTION INPUT ;
    USE SIGNAL ;
    SHAPE ABUTMENT ;
    PORT
      LAYER metal2 ;
      RECT 27.325 0.000 27.395 0.210 ;
    END
  END rw0_wd_in[394]
  PIN rw0_wd_in[395]
    DIRECTION INPUT ;
    USE SIGNAL ;
    SHAPE ABUTMENT ;
    PORT
      LAYER metal2 ;
      RECT 27.515 0.000 27.585 0.210 ;
    END
  END rw0_wd_in[395]
  PIN rw0_wd_in[396]
    DIRECTION INPUT ;
    USE SIGNAL ;
    SHAPE ABUTMENT ;
    PORT
      LAYER metal2 ;
      RECT 27.705 0.000 27.775 0.210 ;
    END
  END rw0_wd_in[396]
  PIN rw0_wd_in[397]
    DIRECTION INPUT ;
    USE SIGNAL ;
    SHAPE ABUTMENT ;
    PORT
      LAYER metal2 ;
      RECT 27.895 0.000 27.965 0.210 ;
    END
  END rw0_wd_in[397]
  PIN rw0_wd_in[398]
    DIRECTION INPUT ;
    USE SIGNAL ;
    SHAPE ABUTMENT ;
    PORT
      LAYER metal2 ;
      RECT 28.085 0.000 28.155 0.210 ;
    END
  END rw0_wd_in[398]
  PIN rw0_wd_in[399]
    DIRECTION INPUT ;
    USE SIGNAL ;
    SHAPE ABUTMENT ;
    PORT
      LAYER metal2 ;
      RECT 28.275 0.000 28.345 0.210 ;
    END
  END rw0_wd_in[399]
  PIN rw0_wd_in[400]
    DIRECTION INPUT ;
    USE SIGNAL ;
    SHAPE ABUTMENT ;
    PORT
      LAYER metal2 ;
      RECT 28.465 0.000 28.535 0.210 ;
    END
  END rw0_wd_in[400]
  PIN rw0_wd_in[401]
    DIRECTION INPUT ;
    USE SIGNAL ;
    SHAPE ABUTMENT ;
    PORT
      LAYER metal2 ;
      RECT 28.655 0.000 28.725 0.210 ;
    END
  END rw0_wd_in[401]
  PIN rw0_wd_in[402]
    DIRECTION INPUT ;
    USE SIGNAL ;
    SHAPE ABUTMENT ;
    PORT
      LAYER metal2 ;
      RECT 28.845 0.000 28.915 0.210 ;
    END
  END rw0_wd_in[402]
  PIN rw0_wd_in[403]
    DIRECTION INPUT ;
    USE SIGNAL ;
    SHAPE ABUTMENT ;
    PORT
      LAYER metal2 ;
      RECT 29.035 0.000 29.105 0.210 ;
    END
  END rw0_wd_in[403]
  PIN rw0_wd_in[404]
    DIRECTION INPUT ;
    USE SIGNAL ;
    SHAPE ABUTMENT ;
    PORT
      LAYER metal2 ;
      RECT 29.225 0.000 29.295 0.210 ;
    END
  END rw0_wd_in[404]
  PIN rw0_wd_in[405]
    DIRECTION INPUT ;
    USE SIGNAL ;
    SHAPE ABUTMENT ;
    PORT
      LAYER metal2 ;
      RECT 29.415 0.000 29.485 0.210 ;
    END
  END rw0_wd_in[405]
  PIN rw0_wd_in[406]
    DIRECTION INPUT ;
    USE SIGNAL ;
    SHAPE ABUTMENT ;
    PORT
      LAYER metal2 ;
      RECT 29.605 0.000 29.675 0.210 ;
    END
  END rw0_wd_in[406]
  PIN rw0_wd_in[407]
    DIRECTION INPUT ;
    USE SIGNAL ;
    SHAPE ABUTMENT ;
    PORT
      LAYER metal2 ;
      RECT 29.795 0.000 29.865 0.210 ;
    END
  END rw0_wd_in[407]
  PIN rw0_wd_in[408]
    DIRECTION INPUT ;
    USE SIGNAL ;
    SHAPE ABUTMENT ;
    PORT
      LAYER metal2 ;
      RECT 29.985 0.000 30.055 0.210 ;
    END
  END rw0_wd_in[408]
  PIN rw0_wd_in[409]
    DIRECTION INPUT ;
    USE SIGNAL ;
    SHAPE ABUTMENT ;
    PORT
      LAYER metal2 ;
      RECT 30.175 0.000 30.245 0.210 ;
    END
  END rw0_wd_in[409]
  PIN rw0_wd_in[410]
    DIRECTION INPUT ;
    USE SIGNAL ;
    SHAPE ABUTMENT ;
    PORT
      LAYER metal2 ;
      RECT 30.365 0.000 30.435 0.210 ;
    END
  END rw0_wd_in[410]
  PIN rw0_wd_in[411]
    DIRECTION INPUT ;
    USE SIGNAL ;
    SHAPE ABUTMENT ;
    PORT
      LAYER metal2 ;
      RECT 30.555 0.000 30.625 0.210 ;
    END
  END rw0_wd_in[411]
  PIN rw0_wd_in[412]
    DIRECTION INPUT ;
    USE SIGNAL ;
    SHAPE ABUTMENT ;
    PORT
      LAYER metal2 ;
      RECT 30.745 0.000 30.815 0.210 ;
    END
  END rw0_wd_in[412]
  PIN rw0_wd_in[413]
    DIRECTION INPUT ;
    USE SIGNAL ;
    SHAPE ABUTMENT ;
    PORT
      LAYER metal2 ;
      RECT 30.935 0.000 31.005 0.210 ;
    END
  END rw0_wd_in[413]
  PIN rw0_wd_in[414]
    DIRECTION INPUT ;
    USE SIGNAL ;
    SHAPE ABUTMENT ;
    PORT
      LAYER metal2 ;
      RECT 31.125 0.000 31.195 0.210 ;
    END
  END rw0_wd_in[414]
  PIN rw0_wd_in[415]
    DIRECTION INPUT ;
    USE SIGNAL ;
    SHAPE ABUTMENT ;
    PORT
      LAYER metal2 ;
      RECT 31.315 0.000 31.385 0.210 ;
    END
  END rw0_wd_in[415]
  PIN rw0_wd_in[416]
    DIRECTION INPUT ;
    USE SIGNAL ;
    SHAPE ABUTMENT ;
    PORT
      LAYER metal2 ;
      RECT 31.505 0.000 31.575 0.210 ;
    END
  END rw0_wd_in[416]
  PIN rw0_wd_in[417]
    DIRECTION INPUT ;
    USE SIGNAL ;
    SHAPE ABUTMENT ;
    PORT
      LAYER metal2 ;
      RECT 31.695 0.000 31.765 0.210 ;
    END
  END rw0_wd_in[417]
  PIN rw0_wd_in[418]
    DIRECTION INPUT ;
    USE SIGNAL ;
    SHAPE ABUTMENT ;
    PORT
      LAYER metal2 ;
      RECT 31.885 0.000 31.955 0.210 ;
    END
  END rw0_wd_in[418]
  PIN rw0_wd_in[419]
    DIRECTION INPUT ;
    USE SIGNAL ;
    SHAPE ABUTMENT ;
    PORT
      LAYER metal2 ;
      RECT 32.075 0.000 32.145 0.210 ;
    END
  END rw0_wd_in[419]
  PIN rw0_wd_in[420]
    DIRECTION INPUT ;
    USE SIGNAL ;
    SHAPE ABUTMENT ;
    PORT
      LAYER metal2 ;
      RECT 32.265 0.000 32.335 0.210 ;
    END
  END rw0_wd_in[420]
  PIN rw0_wd_in[421]
    DIRECTION INPUT ;
    USE SIGNAL ;
    SHAPE ABUTMENT ;
    PORT
      LAYER metal2 ;
      RECT 32.455 0.000 32.525 0.210 ;
    END
  END rw0_wd_in[421]
  PIN rw0_wd_in[422]
    DIRECTION INPUT ;
    USE SIGNAL ;
    SHAPE ABUTMENT ;
    PORT
      LAYER metal2 ;
      RECT 32.645 0.000 32.715 0.210 ;
    END
  END rw0_wd_in[422]
  PIN rw0_wd_in[423]
    DIRECTION INPUT ;
    USE SIGNAL ;
    SHAPE ABUTMENT ;
    PORT
      LAYER metal2 ;
      RECT 32.835 0.000 32.905 0.210 ;
    END
  END rw0_wd_in[423]
  PIN rw0_wd_in[424]
    DIRECTION INPUT ;
    USE SIGNAL ;
    SHAPE ABUTMENT ;
    PORT
      LAYER metal2 ;
      RECT 33.025 0.000 33.095 0.210 ;
    END
  END rw0_wd_in[424]
  PIN rw0_wd_in[425]
    DIRECTION INPUT ;
    USE SIGNAL ;
    SHAPE ABUTMENT ;
    PORT
      LAYER metal2 ;
      RECT 33.215 0.000 33.285 0.210 ;
    END
  END rw0_wd_in[425]
  PIN rw0_wd_in[426]
    DIRECTION INPUT ;
    USE SIGNAL ;
    SHAPE ABUTMENT ;
    PORT
      LAYER metal2 ;
      RECT 33.405 0.000 33.475 0.210 ;
    END
  END rw0_wd_in[426]
  PIN rw0_wd_in[427]
    DIRECTION INPUT ;
    USE SIGNAL ;
    SHAPE ABUTMENT ;
    PORT
      LAYER metal2 ;
      RECT 33.595 0.000 33.665 0.210 ;
    END
  END rw0_wd_in[427]
  PIN rw0_wd_in[428]
    DIRECTION INPUT ;
    USE SIGNAL ;
    SHAPE ABUTMENT ;
    PORT
      LAYER metal2 ;
      RECT 33.785 0.000 33.855 0.210 ;
    END
  END rw0_wd_in[428]
  PIN rw0_wd_in[429]
    DIRECTION INPUT ;
    USE SIGNAL ;
    SHAPE ABUTMENT ;
    PORT
      LAYER metal2 ;
      RECT 33.975 0.000 34.045 0.210 ;
    END
  END rw0_wd_in[429]
  PIN rw0_wd_in[430]
    DIRECTION INPUT ;
    USE SIGNAL ;
    SHAPE ABUTMENT ;
    PORT
      LAYER metal2 ;
      RECT 34.165 0.000 34.235 0.210 ;
    END
  END rw0_wd_in[430]
  PIN rw0_wd_in[431]
    DIRECTION INPUT ;
    USE SIGNAL ;
    SHAPE ABUTMENT ;
    PORT
      LAYER metal2 ;
      RECT 34.355 0.000 34.425 0.210 ;
    END
  END rw0_wd_in[431]
  PIN rw0_wd_in[432]
    DIRECTION INPUT ;
    USE SIGNAL ;
    SHAPE ABUTMENT ;
    PORT
      LAYER metal2 ;
      RECT 34.545 0.000 34.615 0.210 ;
    END
  END rw0_wd_in[432]
  PIN rw0_wd_in[433]
    DIRECTION INPUT ;
    USE SIGNAL ;
    SHAPE ABUTMENT ;
    PORT
      LAYER metal2 ;
      RECT 34.735 0.000 34.805 0.210 ;
    END
  END rw0_wd_in[433]
  PIN rw0_wd_in[434]
    DIRECTION INPUT ;
    USE SIGNAL ;
    SHAPE ABUTMENT ;
    PORT
      LAYER metal2 ;
      RECT 34.925 0.000 34.995 0.210 ;
    END
  END rw0_wd_in[434]
  PIN rw0_wd_in[435]
    DIRECTION INPUT ;
    USE SIGNAL ;
    SHAPE ABUTMENT ;
    PORT
      LAYER metal2 ;
      RECT 35.115 0.000 35.185 0.210 ;
    END
  END rw0_wd_in[435]
  PIN rw0_wd_in[436]
    DIRECTION INPUT ;
    USE SIGNAL ;
    SHAPE ABUTMENT ;
    PORT
      LAYER metal2 ;
      RECT 35.305 0.000 35.375 0.210 ;
    END
  END rw0_wd_in[436]
  PIN rw0_wd_in[437]
    DIRECTION INPUT ;
    USE SIGNAL ;
    SHAPE ABUTMENT ;
    PORT
      LAYER metal2 ;
      RECT 35.495 0.000 35.565 0.210 ;
    END
  END rw0_wd_in[437]
  PIN rw0_wd_in[438]
    DIRECTION INPUT ;
    USE SIGNAL ;
    SHAPE ABUTMENT ;
    PORT
      LAYER metal2 ;
      RECT 35.685 0.000 35.755 0.210 ;
    END
  END rw0_wd_in[438]
  PIN rw0_wd_in[439]
    DIRECTION INPUT ;
    USE SIGNAL ;
    SHAPE ABUTMENT ;
    PORT
      LAYER metal2 ;
      RECT 35.875 0.000 35.945 0.210 ;
    END
  END rw0_wd_in[439]
  PIN rw0_wd_in[440]
    DIRECTION INPUT ;
    USE SIGNAL ;
    SHAPE ABUTMENT ;
    PORT
      LAYER metal2 ;
      RECT 36.065 0.000 36.135 0.210 ;
    END
  END rw0_wd_in[440]
  PIN rw0_wd_in[441]
    DIRECTION INPUT ;
    USE SIGNAL ;
    SHAPE ABUTMENT ;
    PORT
      LAYER metal2 ;
      RECT 36.255 0.000 36.325 0.210 ;
    END
  END rw0_wd_in[441]
  PIN rw0_wd_in[442]
    DIRECTION INPUT ;
    USE SIGNAL ;
    SHAPE ABUTMENT ;
    PORT
      LAYER metal2 ;
      RECT 36.445 0.000 36.515 0.210 ;
    END
  END rw0_wd_in[442]
  PIN rw0_wd_in[443]
    DIRECTION INPUT ;
    USE SIGNAL ;
    SHAPE ABUTMENT ;
    PORT
      LAYER metal2 ;
      RECT 36.635 0.000 36.705 0.210 ;
    END
  END rw0_wd_in[443]
  PIN rw0_wd_in[444]
    DIRECTION INPUT ;
    USE SIGNAL ;
    SHAPE ABUTMENT ;
    PORT
      LAYER metal2 ;
      RECT 36.825 0.000 36.895 0.210 ;
    END
  END rw0_wd_in[444]
  PIN rw0_wd_in[445]
    DIRECTION INPUT ;
    USE SIGNAL ;
    SHAPE ABUTMENT ;
    PORT
      LAYER metal2 ;
      RECT 37.015 0.000 37.085 0.210 ;
    END
  END rw0_wd_in[445]
  PIN rw0_wd_in[446]
    DIRECTION INPUT ;
    USE SIGNAL ;
    SHAPE ABUTMENT ;
    PORT
      LAYER metal2 ;
      RECT 37.205 0.000 37.275 0.210 ;
    END
  END rw0_wd_in[446]
  PIN rw0_wd_in[447]
    DIRECTION INPUT ;
    USE SIGNAL ;
    SHAPE ABUTMENT ;
    PORT
      LAYER metal2 ;
      RECT 37.395 0.000 37.465 0.210 ;
    END
  END rw0_wd_in[447]
  PIN rw0_wd_in[448]
    DIRECTION INPUT ;
    USE SIGNAL ;
    SHAPE ABUTMENT ;
    PORT
      LAYER metal2 ;
      RECT 37.585 0.000 37.655 0.210 ;
    END
  END rw0_wd_in[448]
  PIN rw0_wd_in[449]
    DIRECTION INPUT ;
    USE SIGNAL ;
    SHAPE ABUTMENT ;
    PORT
      LAYER metal2 ;
      RECT 37.775 0.000 37.845 0.210 ;
    END
  END rw0_wd_in[449]
  PIN rw0_wd_in[450]
    DIRECTION INPUT ;
    USE SIGNAL ;
    SHAPE ABUTMENT ;
    PORT
      LAYER metal2 ;
      RECT 37.965 0.000 38.035 0.210 ;
    END
  END rw0_wd_in[450]
  PIN rw0_wd_in[451]
    DIRECTION INPUT ;
    USE SIGNAL ;
    SHAPE ABUTMENT ;
    PORT
      LAYER metal2 ;
      RECT 38.155 0.000 38.225 0.210 ;
    END
  END rw0_wd_in[451]
  PIN rw0_wd_in[452]
    DIRECTION INPUT ;
    USE SIGNAL ;
    SHAPE ABUTMENT ;
    PORT
      LAYER metal2 ;
      RECT 38.345 0.000 38.415 0.210 ;
    END
  END rw0_wd_in[452]
  PIN rw0_wd_in[453]
    DIRECTION INPUT ;
    USE SIGNAL ;
    SHAPE ABUTMENT ;
    PORT
      LAYER metal2 ;
      RECT 38.535 0.000 38.605 0.210 ;
    END
  END rw0_wd_in[453]
  PIN rw0_wd_in[454]
    DIRECTION INPUT ;
    USE SIGNAL ;
    SHAPE ABUTMENT ;
    PORT
      LAYER metal2 ;
      RECT 38.725 0.000 38.795 0.210 ;
    END
  END rw0_wd_in[454]
  PIN rw0_wd_in[455]
    DIRECTION INPUT ;
    USE SIGNAL ;
    SHAPE ABUTMENT ;
    PORT
      LAYER metal2 ;
      RECT 38.915 0.000 38.985 0.210 ;
    END
  END rw0_wd_in[455]
  PIN rw0_wd_in[456]
    DIRECTION INPUT ;
    USE SIGNAL ;
    SHAPE ABUTMENT ;
    PORT
      LAYER metal2 ;
      RECT 39.105 0.000 39.175 0.210 ;
    END
  END rw0_wd_in[456]
  PIN rw0_wd_in[457]
    DIRECTION INPUT ;
    USE SIGNAL ;
    SHAPE ABUTMENT ;
    PORT
      LAYER metal2 ;
      RECT 39.295 0.000 39.365 0.210 ;
    END
  END rw0_wd_in[457]
  PIN rw0_wd_in[458]
    DIRECTION INPUT ;
    USE SIGNAL ;
    SHAPE ABUTMENT ;
    PORT
      LAYER metal2 ;
      RECT 39.485 0.000 39.555 0.210 ;
    END
  END rw0_wd_in[458]
  PIN rw0_wd_in[459]
    DIRECTION INPUT ;
    USE SIGNAL ;
    SHAPE ABUTMENT ;
    PORT
      LAYER metal2 ;
      RECT 39.675 0.000 39.745 0.210 ;
    END
  END rw0_wd_in[459]
  PIN rw0_wd_in[460]
    DIRECTION INPUT ;
    USE SIGNAL ;
    SHAPE ABUTMENT ;
    PORT
      LAYER metal2 ;
      RECT 39.865 0.000 39.935 0.210 ;
    END
  END rw0_wd_in[460]
  PIN rw0_wd_in[461]
    DIRECTION INPUT ;
    USE SIGNAL ;
    SHAPE ABUTMENT ;
    PORT
      LAYER metal2 ;
      RECT 40.055 0.000 40.125 0.210 ;
    END
  END rw0_wd_in[461]
  PIN rw0_wd_in[462]
    DIRECTION INPUT ;
    USE SIGNAL ;
    SHAPE ABUTMENT ;
    PORT
      LAYER metal2 ;
      RECT 40.245 0.000 40.315 0.210 ;
    END
  END rw0_wd_in[462]
  PIN rw0_wd_in[463]
    DIRECTION INPUT ;
    USE SIGNAL ;
    SHAPE ABUTMENT ;
    PORT
      LAYER metal2 ;
      RECT 40.435 0.000 40.505 0.210 ;
    END
  END rw0_wd_in[463]
  PIN rw0_wd_in[464]
    DIRECTION INPUT ;
    USE SIGNAL ;
    SHAPE ABUTMENT ;
    PORT
      LAYER metal2 ;
      RECT 40.625 0.000 40.695 0.210 ;
    END
  END rw0_wd_in[464]
  PIN rw0_wd_in[465]
    DIRECTION INPUT ;
    USE SIGNAL ;
    SHAPE ABUTMENT ;
    PORT
      LAYER metal2 ;
      RECT 40.815 0.000 40.885 0.210 ;
    END
  END rw0_wd_in[465]
  PIN rw0_wd_in[466]
    DIRECTION INPUT ;
    USE SIGNAL ;
    SHAPE ABUTMENT ;
    PORT
      LAYER metal2 ;
      RECT 41.005 0.000 41.075 0.210 ;
    END
  END rw0_wd_in[466]
  PIN rw0_wd_in[467]
    DIRECTION INPUT ;
    USE SIGNAL ;
    SHAPE ABUTMENT ;
    PORT
      LAYER metal2 ;
      RECT 41.195 0.000 41.265 0.210 ;
    END
  END rw0_wd_in[467]
  PIN rw0_wd_in[468]
    DIRECTION INPUT ;
    USE SIGNAL ;
    SHAPE ABUTMENT ;
    PORT
      LAYER metal2 ;
      RECT 41.385 0.000 41.455 0.210 ;
    END
  END rw0_wd_in[468]
  PIN rw0_wd_in[469]
    DIRECTION INPUT ;
    USE SIGNAL ;
    SHAPE ABUTMENT ;
    PORT
      LAYER metal2 ;
      RECT 41.575 0.000 41.645 0.210 ;
    END
  END rw0_wd_in[469]
  PIN rw0_wd_in[470]
    DIRECTION INPUT ;
    USE SIGNAL ;
    SHAPE ABUTMENT ;
    PORT
      LAYER metal2 ;
      RECT 41.765 0.000 41.835 0.210 ;
    END
  END rw0_wd_in[470]
  PIN rw0_wd_in[471]
    DIRECTION INPUT ;
    USE SIGNAL ;
    SHAPE ABUTMENT ;
    PORT
      LAYER metal2 ;
      RECT 41.955 0.000 42.025 0.210 ;
    END
  END rw0_wd_in[471]
  PIN rw0_wd_in[472]
    DIRECTION INPUT ;
    USE SIGNAL ;
    SHAPE ABUTMENT ;
    PORT
      LAYER metal2 ;
      RECT 42.145 0.000 42.215 0.210 ;
    END
  END rw0_wd_in[472]
  PIN rw0_wd_in[473]
    DIRECTION INPUT ;
    USE SIGNAL ;
    SHAPE ABUTMENT ;
    PORT
      LAYER metal2 ;
      RECT 42.335 0.000 42.405 0.210 ;
    END
  END rw0_wd_in[473]
  PIN rw0_wd_in[474]
    DIRECTION INPUT ;
    USE SIGNAL ;
    SHAPE ABUTMENT ;
    PORT
      LAYER metal2 ;
      RECT 42.525 0.000 42.595 0.210 ;
    END
  END rw0_wd_in[474]
  PIN rw0_wd_in[475]
    DIRECTION INPUT ;
    USE SIGNAL ;
    SHAPE ABUTMENT ;
    PORT
      LAYER metal2 ;
      RECT 42.715 0.000 42.785 0.210 ;
    END
  END rw0_wd_in[475]
  PIN rw0_wd_in[476]
    DIRECTION INPUT ;
    USE SIGNAL ;
    SHAPE ABUTMENT ;
    PORT
      LAYER metal2 ;
      RECT 42.905 0.000 42.975 0.210 ;
    END
  END rw0_wd_in[476]
  PIN rw0_wd_in[477]
    DIRECTION INPUT ;
    USE SIGNAL ;
    SHAPE ABUTMENT ;
    PORT
      LAYER metal2 ;
      RECT 43.095 0.000 43.165 0.210 ;
    END
  END rw0_wd_in[477]
  PIN rw0_wd_in[478]
    DIRECTION INPUT ;
    USE SIGNAL ;
    SHAPE ABUTMENT ;
    PORT
      LAYER metal2 ;
      RECT 43.285 0.000 43.355 0.210 ;
    END
  END rw0_wd_in[478]
  PIN rw0_wd_in[479]
    DIRECTION INPUT ;
    USE SIGNAL ;
    SHAPE ABUTMENT ;
    PORT
      LAYER metal2 ;
      RECT 43.475 0.000 43.545 0.210 ;
    END
  END rw0_wd_in[479]
  PIN rw0_wd_in[480]
    DIRECTION INPUT ;
    USE SIGNAL ;
    SHAPE ABUTMENT ;
    PORT
      LAYER metal2 ;
      RECT 43.665 0.000 43.735 0.210 ;
    END
  END rw0_wd_in[480]
  PIN rw0_wd_in[481]
    DIRECTION INPUT ;
    USE SIGNAL ;
    SHAPE ABUTMENT ;
    PORT
      LAYER metal2 ;
      RECT 43.855 0.000 43.925 0.210 ;
    END
  END rw0_wd_in[481]
  PIN rw0_wd_in[482]
    DIRECTION INPUT ;
    USE SIGNAL ;
    SHAPE ABUTMENT ;
    PORT
      LAYER metal2 ;
      RECT 44.045 0.000 44.115 0.210 ;
    END
  END rw0_wd_in[482]
  PIN rw0_wd_in[483]
    DIRECTION INPUT ;
    USE SIGNAL ;
    SHAPE ABUTMENT ;
    PORT
      LAYER metal2 ;
      RECT 44.235 0.000 44.305 0.210 ;
    END
  END rw0_wd_in[483]
  PIN rw0_wd_in[484]
    DIRECTION INPUT ;
    USE SIGNAL ;
    SHAPE ABUTMENT ;
    PORT
      LAYER metal2 ;
      RECT 44.425 0.000 44.495 0.210 ;
    END
  END rw0_wd_in[484]
  PIN rw0_wd_in[485]
    DIRECTION INPUT ;
    USE SIGNAL ;
    SHAPE ABUTMENT ;
    PORT
      LAYER metal2 ;
      RECT 44.615 0.000 44.685 0.210 ;
    END
  END rw0_wd_in[485]
  PIN rw0_wd_in[486]
    DIRECTION INPUT ;
    USE SIGNAL ;
    SHAPE ABUTMENT ;
    PORT
      LAYER metal2 ;
      RECT 44.805 0.000 44.875 0.210 ;
    END
  END rw0_wd_in[486]
  PIN rw0_wd_in[487]
    DIRECTION INPUT ;
    USE SIGNAL ;
    SHAPE ABUTMENT ;
    PORT
      LAYER metal2 ;
      RECT 44.995 0.000 45.065 0.210 ;
    END
  END rw0_wd_in[487]
  PIN rw0_wd_in[488]
    DIRECTION INPUT ;
    USE SIGNAL ;
    SHAPE ABUTMENT ;
    PORT
      LAYER metal2 ;
      RECT 45.185 0.000 45.255 0.210 ;
    END
  END rw0_wd_in[488]
  PIN rw0_wd_in[489]
    DIRECTION INPUT ;
    USE SIGNAL ;
    SHAPE ABUTMENT ;
    PORT
      LAYER metal2 ;
      RECT 45.375 0.000 45.445 0.210 ;
    END
  END rw0_wd_in[489]
  PIN rw0_wd_in[490]
    DIRECTION INPUT ;
    USE SIGNAL ;
    SHAPE ABUTMENT ;
    PORT
      LAYER metal2 ;
      RECT 45.565 0.000 45.635 0.210 ;
    END
  END rw0_wd_in[490]
  PIN rw0_wd_in[491]
    DIRECTION INPUT ;
    USE SIGNAL ;
    SHAPE ABUTMENT ;
    PORT
      LAYER metal2 ;
      RECT 45.755 0.000 45.825 0.210 ;
    END
  END rw0_wd_in[491]
  PIN rw0_wd_in[492]
    DIRECTION INPUT ;
    USE SIGNAL ;
    SHAPE ABUTMENT ;
    PORT
      LAYER metal2 ;
      RECT 45.945 0.000 46.015 0.210 ;
    END
  END rw0_wd_in[492]
  PIN rw0_wd_in[493]
    DIRECTION INPUT ;
    USE SIGNAL ;
    SHAPE ABUTMENT ;
    PORT
      LAYER metal2 ;
      RECT 46.135 0.000 46.205 0.210 ;
    END
  END rw0_wd_in[493]
  PIN rw0_wd_in[494]
    DIRECTION INPUT ;
    USE SIGNAL ;
    SHAPE ABUTMENT ;
    PORT
      LAYER metal2 ;
      RECT 46.325 0.000 46.395 0.210 ;
    END
  END rw0_wd_in[494]
  PIN rw0_wd_in[495]
    DIRECTION INPUT ;
    USE SIGNAL ;
    SHAPE ABUTMENT ;
    PORT
      LAYER metal2 ;
      RECT 46.515 0.000 46.585 0.210 ;
    END
  END rw0_wd_in[495]
  PIN rw0_wd_in[496]
    DIRECTION INPUT ;
    USE SIGNAL ;
    SHAPE ABUTMENT ;
    PORT
      LAYER metal2 ;
      RECT 46.705 0.000 46.775 0.210 ;
    END
  END rw0_wd_in[496]
  PIN rw0_wd_in[497]
    DIRECTION INPUT ;
    USE SIGNAL ;
    SHAPE ABUTMENT ;
    PORT
      LAYER metal2 ;
      RECT 46.895 0.000 46.965 0.210 ;
    END
  END rw0_wd_in[497]
  PIN rw0_wd_in[498]
    DIRECTION INPUT ;
    USE SIGNAL ;
    SHAPE ABUTMENT ;
    PORT
      LAYER metal2 ;
      RECT 47.085 0.000 47.155 0.210 ;
    END
  END rw0_wd_in[498]
  PIN rw0_wd_in[499]
    DIRECTION INPUT ;
    USE SIGNAL ;
    SHAPE ABUTMENT ;
    PORT
      LAYER metal2 ;
      RECT 47.275 0.000 47.345 0.210 ;
    END
  END rw0_wd_in[499]
  PIN rw0_wd_in[500]
    DIRECTION INPUT ;
    USE SIGNAL ;
    SHAPE ABUTMENT ;
    PORT
      LAYER metal2 ;
      RECT 47.465 0.000 47.535 0.210 ;
    END
  END rw0_wd_in[500]
  PIN rw0_wd_in[501]
    DIRECTION INPUT ;
    USE SIGNAL ;
    SHAPE ABUTMENT ;
    PORT
      LAYER metal2 ;
      RECT 47.655 0.000 47.725 0.210 ;
    END
  END rw0_wd_in[501]
  PIN rw0_wd_in[502]
    DIRECTION INPUT ;
    USE SIGNAL ;
    SHAPE ABUTMENT ;
    PORT
      LAYER metal2 ;
      RECT 47.845 0.000 47.915 0.210 ;
    END
  END rw0_wd_in[502]
  PIN rw0_wd_in[503]
    DIRECTION INPUT ;
    USE SIGNAL ;
    SHAPE ABUTMENT ;
    PORT
      LAYER metal2 ;
      RECT 48.035 0.000 48.105 0.210 ;
    END
  END rw0_wd_in[503]
  PIN rw0_wd_in[504]
    DIRECTION INPUT ;
    USE SIGNAL ;
    SHAPE ABUTMENT ;
    PORT
      LAYER metal2 ;
      RECT 48.225 0.000 48.295 0.210 ;
    END
  END rw0_wd_in[504]
  PIN rw0_wd_in[505]
    DIRECTION INPUT ;
    USE SIGNAL ;
    SHAPE ABUTMENT ;
    PORT
      LAYER metal2 ;
      RECT 48.415 0.000 48.485 0.210 ;
    END
  END rw0_wd_in[505]
  PIN rw0_wd_in[506]
    DIRECTION INPUT ;
    USE SIGNAL ;
    SHAPE ABUTMENT ;
    PORT
      LAYER metal2 ;
      RECT 48.605 0.000 48.675 0.210 ;
    END
  END rw0_wd_in[506]
  PIN rw0_wd_in[507]
    DIRECTION INPUT ;
    USE SIGNAL ;
    SHAPE ABUTMENT ;
    PORT
      LAYER metal2 ;
      RECT 48.795 0.000 48.865 0.210 ;
    END
  END rw0_wd_in[507]
  PIN rw0_wd_in[508]
    DIRECTION INPUT ;
    USE SIGNAL ;
    SHAPE ABUTMENT ;
    PORT
      LAYER metal2 ;
      RECT 48.985 0.000 49.055 0.210 ;
    END
  END rw0_wd_in[508]
  PIN rw0_wd_in[509]
    DIRECTION INPUT ;
    USE SIGNAL ;
    SHAPE ABUTMENT ;
    PORT
      LAYER metal2 ;
      RECT 49.175 0.000 49.245 0.210 ;
    END
  END rw0_wd_in[509]
  PIN rw0_wd_in[510]
    DIRECTION INPUT ;
    USE SIGNAL ;
    SHAPE ABUTMENT ;
    PORT
      LAYER metal2 ;
      RECT 49.365 0.000 49.435 0.210 ;
    END
  END rw0_wd_in[510]
  PIN rw0_wd_in[511]
    DIRECTION INPUT ;
    USE SIGNAL ;
    SHAPE ABUTMENT ;
    PORT
      LAYER metal2 ;
      RECT 49.555 0.000 49.625 0.210 ;
    END
  END rw0_wd_in[511]
  PIN rw0_rd_out[0]
    DIRECTION OUTPUT ;
    USE SIGNAL ;
    SHAPE ABUTMENT ;
    PORT
      LAYER metal2 ;
      RECT 49.745 0.000 49.815 0.210 ;
    END
  END rw0_rd_out[0]
  PIN rw0_rd_out[1]
    DIRECTION OUTPUT ;
    USE SIGNAL ;
    SHAPE ABUTMENT ;
    PORT
      LAYER metal2 ;
      RECT 49.935 0.000 50.005 0.210 ;
    END
  END rw0_rd_out[1]
  PIN rw0_rd_out[2]
    DIRECTION OUTPUT ;
    USE SIGNAL ;
    SHAPE ABUTMENT ;
    PORT
      LAYER metal2 ;
      RECT 50.125 0.000 50.195 0.210 ;
    END
  END rw0_rd_out[2]
  PIN rw0_rd_out[3]
    DIRECTION OUTPUT ;
    USE SIGNAL ;
    SHAPE ABUTMENT ;
    PORT
      LAYER metal2 ;
      RECT 50.315 0.000 50.385 0.210 ;
    END
  END rw0_rd_out[3]
  PIN rw0_rd_out[4]
    DIRECTION OUTPUT ;
    USE SIGNAL ;
    SHAPE ABUTMENT ;
    PORT
      LAYER metal2 ;
      RECT 50.505 0.000 50.575 0.210 ;
    END
  END rw0_rd_out[4]
  PIN rw0_rd_out[5]
    DIRECTION OUTPUT ;
    USE SIGNAL ;
    SHAPE ABUTMENT ;
    PORT
      LAYER metal2 ;
      RECT 50.695 0.000 50.765 0.210 ;
    END
  END rw0_rd_out[5]
  PIN rw0_rd_out[6]
    DIRECTION OUTPUT ;
    USE SIGNAL ;
    SHAPE ABUTMENT ;
    PORT
      LAYER metal2 ;
      RECT 50.885 0.000 50.955 0.210 ;
    END
  END rw0_rd_out[6]
  PIN rw0_rd_out[7]
    DIRECTION OUTPUT ;
    USE SIGNAL ;
    SHAPE ABUTMENT ;
    PORT
      LAYER metal2 ;
      RECT 51.075 0.000 51.145 0.210 ;
    END
  END rw0_rd_out[7]
  PIN rw0_rd_out[8]
    DIRECTION OUTPUT ;
    USE SIGNAL ;
    SHAPE ABUTMENT ;
    PORT
      LAYER metal2 ;
      RECT 51.265 0.000 51.335 0.210 ;
    END
  END rw0_rd_out[8]
  PIN rw0_rd_out[9]
    DIRECTION OUTPUT ;
    USE SIGNAL ;
    SHAPE ABUTMENT ;
    PORT
      LAYER metal2 ;
      RECT 51.455 0.000 51.525 0.210 ;
    END
  END rw0_rd_out[9]
  PIN rw0_rd_out[10]
    DIRECTION OUTPUT ;
    USE SIGNAL ;
    SHAPE ABUTMENT ;
    PORT
      LAYER metal2 ;
      RECT 51.645 0.000 51.715 0.210 ;
    END
  END rw0_rd_out[10]
  PIN rw0_rd_out[11]
    DIRECTION OUTPUT ;
    USE SIGNAL ;
    SHAPE ABUTMENT ;
    PORT
      LAYER metal2 ;
      RECT 51.835 0.000 51.905 0.210 ;
    END
  END rw0_rd_out[11]
  PIN rw0_rd_out[12]
    DIRECTION OUTPUT ;
    USE SIGNAL ;
    SHAPE ABUTMENT ;
    PORT
      LAYER metal2 ;
      RECT 52.025 0.000 52.095 0.210 ;
    END
  END rw0_rd_out[12]
  PIN rw0_rd_out[13]
    DIRECTION OUTPUT ;
    USE SIGNAL ;
    SHAPE ABUTMENT ;
    PORT
      LAYER metal2 ;
      RECT 52.215 0.000 52.285 0.210 ;
    END
  END rw0_rd_out[13]
  PIN rw0_rd_out[14]
    DIRECTION OUTPUT ;
    USE SIGNAL ;
    SHAPE ABUTMENT ;
    PORT
      LAYER metal2 ;
      RECT 52.405 0.000 52.475 0.210 ;
    END
  END rw0_rd_out[14]
  PIN rw0_rd_out[15]
    DIRECTION OUTPUT ;
    USE SIGNAL ;
    SHAPE ABUTMENT ;
    PORT
      LAYER metal2 ;
      RECT 52.595 0.000 52.665 0.210 ;
    END
  END rw0_rd_out[15]
  PIN rw0_rd_out[16]
    DIRECTION OUTPUT ;
    USE SIGNAL ;
    SHAPE ABUTMENT ;
    PORT
      LAYER metal2 ;
      RECT 52.785 0.000 52.855 0.210 ;
    END
  END rw0_rd_out[16]
  PIN rw0_rd_out[17]
    DIRECTION OUTPUT ;
    USE SIGNAL ;
    SHAPE ABUTMENT ;
    PORT
      LAYER metal2 ;
      RECT 52.975 0.000 53.045 0.210 ;
    END
  END rw0_rd_out[17]
  PIN rw0_rd_out[18]
    DIRECTION OUTPUT ;
    USE SIGNAL ;
    SHAPE ABUTMENT ;
    PORT
      LAYER metal2 ;
      RECT 53.165 0.000 53.235 0.210 ;
    END
  END rw0_rd_out[18]
  PIN rw0_rd_out[19]
    DIRECTION OUTPUT ;
    USE SIGNAL ;
    SHAPE ABUTMENT ;
    PORT
      LAYER metal2 ;
      RECT 53.355 0.000 53.425 0.210 ;
    END
  END rw0_rd_out[19]
  PIN rw0_rd_out[20]
    DIRECTION OUTPUT ;
    USE SIGNAL ;
    SHAPE ABUTMENT ;
    PORT
      LAYER metal2 ;
      RECT 53.545 0.000 53.615 0.210 ;
    END
  END rw0_rd_out[20]
  PIN rw0_rd_out[21]
    DIRECTION OUTPUT ;
    USE SIGNAL ;
    SHAPE ABUTMENT ;
    PORT
      LAYER metal2 ;
      RECT 53.735 0.000 53.805 0.210 ;
    END
  END rw0_rd_out[21]
  PIN rw0_rd_out[22]
    DIRECTION OUTPUT ;
    USE SIGNAL ;
    SHAPE ABUTMENT ;
    PORT
      LAYER metal2 ;
      RECT 53.925 0.000 53.995 0.210 ;
    END
  END rw0_rd_out[22]
  PIN rw0_rd_out[23]
    DIRECTION OUTPUT ;
    USE SIGNAL ;
    SHAPE ABUTMENT ;
    PORT
      LAYER metal2 ;
      RECT 54.115 0.000 54.185 0.210 ;
    END
  END rw0_rd_out[23]
  PIN rw0_rd_out[24]
    DIRECTION OUTPUT ;
    USE SIGNAL ;
    SHAPE ABUTMENT ;
    PORT
      LAYER metal2 ;
      RECT 54.305 0.000 54.375 0.210 ;
    END
  END rw0_rd_out[24]
  PIN rw0_rd_out[25]
    DIRECTION OUTPUT ;
    USE SIGNAL ;
    SHAPE ABUTMENT ;
    PORT
      LAYER metal2 ;
      RECT 54.495 0.000 54.565 0.210 ;
    END
  END rw0_rd_out[25]
  PIN rw0_rd_out[26]
    DIRECTION OUTPUT ;
    USE SIGNAL ;
    SHAPE ABUTMENT ;
    PORT
      LAYER metal2 ;
      RECT 54.685 0.000 54.755 0.210 ;
    END
  END rw0_rd_out[26]
  PIN rw0_rd_out[27]
    DIRECTION OUTPUT ;
    USE SIGNAL ;
    SHAPE ABUTMENT ;
    PORT
      LAYER metal2 ;
      RECT 54.875 0.000 54.945 0.210 ;
    END
  END rw0_rd_out[27]
  PIN rw0_rd_out[28]
    DIRECTION OUTPUT ;
    USE SIGNAL ;
    SHAPE ABUTMENT ;
    PORT
      LAYER metal2 ;
      RECT 55.065 0.000 55.135 0.210 ;
    END
  END rw0_rd_out[28]
  PIN rw0_rd_out[29]
    DIRECTION OUTPUT ;
    USE SIGNAL ;
    SHAPE ABUTMENT ;
    PORT
      LAYER metal2 ;
      RECT 55.255 0.000 55.325 0.210 ;
    END
  END rw0_rd_out[29]
  PIN rw0_rd_out[30]
    DIRECTION OUTPUT ;
    USE SIGNAL ;
    SHAPE ABUTMENT ;
    PORT
      LAYER metal2 ;
      RECT 55.445 0.000 55.515 0.210 ;
    END
  END rw0_rd_out[30]
  PIN rw0_rd_out[31]
    DIRECTION OUTPUT ;
    USE SIGNAL ;
    SHAPE ABUTMENT ;
    PORT
      LAYER metal2 ;
      RECT 55.635 0.000 55.705 0.210 ;
    END
  END rw0_rd_out[31]
  PIN rw0_rd_out[32]
    DIRECTION OUTPUT ;
    USE SIGNAL ;
    SHAPE ABUTMENT ;
    PORT
      LAYER metal2 ;
      RECT 55.825 0.000 55.895 0.210 ;
    END
  END rw0_rd_out[32]
  PIN rw0_rd_out[33]
    DIRECTION OUTPUT ;
    USE SIGNAL ;
    SHAPE ABUTMENT ;
    PORT
      LAYER metal2 ;
      RECT 56.015 0.000 56.085 0.210 ;
    END
  END rw0_rd_out[33]
  PIN rw0_rd_out[34]
    DIRECTION OUTPUT ;
    USE SIGNAL ;
    SHAPE ABUTMENT ;
    PORT
      LAYER metal2 ;
      RECT 56.205 0.000 56.275 0.210 ;
    END
  END rw0_rd_out[34]
  PIN rw0_rd_out[35]
    DIRECTION OUTPUT ;
    USE SIGNAL ;
    SHAPE ABUTMENT ;
    PORT
      LAYER metal2 ;
      RECT 56.395 0.000 56.465 0.210 ;
    END
  END rw0_rd_out[35]
  PIN rw0_rd_out[36]
    DIRECTION OUTPUT ;
    USE SIGNAL ;
    SHAPE ABUTMENT ;
    PORT
      LAYER metal2 ;
      RECT 56.585 0.000 56.655 0.210 ;
    END
  END rw0_rd_out[36]
  PIN rw0_rd_out[37]
    DIRECTION OUTPUT ;
    USE SIGNAL ;
    SHAPE ABUTMENT ;
    PORT
      LAYER metal2 ;
      RECT 56.775 0.000 56.845 0.210 ;
    END
  END rw0_rd_out[37]
  PIN rw0_rd_out[38]
    DIRECTION OUTPUT ;
    USE SIGNAL ;
    SHAPE ABUTMENT ;
    PORT
      LAYER metal2 ;
      RECT 56.965 0.000 57.035 0.210 ;
    END
  END rw0_rd_out[38]
  PIN rw0_rd_out[39]
    DIRECTION OUTPUT ;
    USE SIGNAL ;
    SHAPE ABUTMENT ;
    PORT
      LAYER metal2 ;
      RECT 57.155 0.000 57.225 0.210 ;
    END
  END rw0_rd_out[39]
  PIN rw0_rd_out[40]
    DIRECTION OUTPUT ;
    USE SIGNAL ;
    SHAPE ABUTMENT ;
    PORT
      LAYER metal2 ;
      RECT 57.345 0.000 57.415 0.210 ;
    END
  END rw0_rd_out[40]
  PIN rw0_rd_out[41]
    DIRECTION OUTPUT ;
    USE SIGNAL ;
    SHAPE ABUTMENT ;
    PORT
      LAYER metal2 ;
      RECT 57.535 0.000 57.605 0.210 ;
    END
  END rw0_rd_out[41]
  PIN rw0_rd_out[42]
    DIRECTION OUTPUT ;
    USE SIGNAL ;
    SHAPE ABUTMENT ;
    PORT
      LAYER metal2 ;
      RECT 57.725 0.000 57.795 0.210 ;
    END
  END rw0_rd_out[42]
  PIN rw0_rd_out[43]
    DIRECTION OUTPUT ;
    USE SIGNAL ;
    SHAPE ABUTMENT ;
    PORT
      LAYER metal2 ;
      RECT 57.915 0.000 57.985 0.210 ;
    END
  END rw0_rd_out[43]
  PIN rw0_rd_out[44]
    DIRECTION OUTPUT ;
    USE SIGNAL ;
    SHAPE ABUTMENT ;
    PORT
      LAYER metal2 ;
      RECT 58.105 0.000 58.175 0.210 ;
    END
  END rw0_rd_out[44]
  PIN rw0_rd_out[45]
    DIRECTION OUTPUT ;
    USE SIGNAL ;
    SHAPE ABUTMENT ;
    PORT
      LAYER metal2 ;
      RECT 58.295 0.000 58.365 0.210 ;
    END
  END rw0_rd_out[45]
  PIN rw0_rd_out[46]
    DIRECTION OUTPUT ;
    USE SIGNAL ;
    SHAPE ABUTMENT ;
    PORT
      LAYER metal2 ;
      RECT 58.485 0.000 58.555 0.210 ;
    END
  END rw0_rd_out[46]
  PIN rw0_rd_out[47]
    DIRECTION OUTPUT ;
    USE SIGNAL ;
    SHAPE ABUTMENT ;
    PORT
      LAYER metal2 ;
      RECT 58.675 0.000 58.745 0.210 ;
    END
  END rw0_rd_out[47]
  PIN rw0_rd_out[48]
    DIRECTION OUTPUT ;
    USE SIGNAL ;
    SHAPE ABUTMENT ;
    PORT
      LAYER metal2 ;
      RECT 58.865 0.000 58.935 0.210 ;
    END
  END rw0_rd_out[48]
  PIN rw0_rd_out[49]
    DIRECTION OUTPUT ;
    USE SIGNAL ;
    SHAPE ABUTMENT ;
    PORT
      LAYER metal2 ;
      RECT 59.055 0.000 59.125 0.210 ;
    END
  END rw0_rd_out[49]
  PIN rw0_rd_out[50]
    DIRECTION OUTPUT ;
    USE SIGNAL ;
    SHAPE ABUTMENT ;
    PORT
      LAYER metal2 ;
      RECT 59.245 0.000 59.315 0.210 ;
    END
  END rw0_rd_out[50]
  PIN rw0_rd_out[51]
    DIRECTION OUTPUT ;
    USE SIGNAL ;
    SHAPE ABUTMENT ;
    PORT
      LAYER metal2 ;
      RECT 59.435 0.000 59.505 0.210 ;
    END
  END rw0_rd_out[51]
  PIN rw0_rd_out[52]
    DIRECTION OUTPUT ;
    USE SIGNAL ;
    SHAPE ABUTMENT ;
    PORT
      LAYER metal2 ;
      RECT 59.625 0.000 59.695 0.210 ;
    END
  END rw0_rd_out[52]
  PIN rw0_rd_out[53]
    DIRECTION OUTPUT ;
    USE SIGNAL ;
    SHAPE ABUTMENT ;
    PORT
      LAYER metal2 ;
      RECT 59.815 0.000 59.885 0.210 ;
    END
  END rw0_rd_out[53]
  PIN rw0_rd_out[54]
    DIRECTION OUTPUT ;
    USE SIGNAL ;
    SHAPE ABUTMENT ;
    PORT
      LAYER metal2 ;
      RECT 60.005 0.000 60.075 0.210 ;
    END
  END rw0_rd_out[54]
  PIN rw0_rd_out[55]
    DIRECTION OUTPUT ;
    USE SIGNAL ;
    SHAPE ABUTMENT ;
    PORT
      LAYER metal2 ;
      RECT 60.195 0.000 60.265 0.210 ;
    END
  END rw0_rd_out[55]
  PIN rw0_rd_out[56]
    DIRECTION OUTPUT ;
    USE SIGNAL ;
    SHAPE ABUTMENT ;
    PORT
      LAYER metal2 ;
      RECT 60.385 0.000 60.455 0.210 ;
    END
  END rw0_rd_out[56]
  PIN rw0_rd_out[57]
    DIRECTION OUTPUT ;
    USE SIGNAL ;
    SHAPE ABUTMENT ;
    PORT
      LAYER metal2 ;
      RECT 60.575 0.000 60.645 0.210 ;
    END
  END rw0_rd_out[57]
  PIN rw0_rd_out[58]
    DIRECTION OUTPUT ;
    USE SIGNAL ;
    SHAPE ABUTMENT ;
    PORT
      LAYER metal2 ;
      RECT 60.765 0.000 60.835 0.210 ;
    END
  END rw0_rd_out[58]
  PIN rw0_rd_out[59]
    DIRECTION OUTPUT ;
    USE SIGNAL ;
    SHAPE ABUTMENT ;
    PORT
      LAYER metal2 ;
      RECT 60.955 0.000 61.025 0.210 ;
    END
  END rw0_rd_out[59]
  PIN rw0_rd_out[60]
    DIRECTION OUTPUT ;
    USE SIGNAL ;
    SHAPE ABUTMENT ;
    PORT
      LAYER metal2 ;
      RECT 61.145 0.000 61.215 0.210 ;
    END
  END rw0_rd_out[60]
  PIN rw0_rd_out[61]
    DIRECTION OUTPUT ;
    USE SIGNAL ;
    SHAPE ABUTMENT ;
    PORT
      LAYER metal2 ;
      RECT 61.335 0.000 61.405 0.210 ;
    END
  END rw0_rd_out[61]
  PIN rw0_rd_out[62]
    DIRECTION OUTPUT ;
    USE SIGNAL ;
    SHAPE ABUTMENT ;
    PORT
      LAYER metal2 ;
      RECT 61.525 0.000 61.595 0.210 ;
    END
  END rw0_rd_out[62]
  PIN rw0_rd_out[63]
    DIRECTION OUTPUT ;
    USE SIGNAL ;
    SHAPE ABUTMENT ;
    PORT
      LAYER metal2 ;
      RECT 61.715 0.000 61.785 0.210 ;
    END
  END rw0_rd_out[63]
  PIN rw0_rd_out[64]
    DIRECTION OUTPUT ;
    USE SIGNAL ;
    SHAPE ABUTMENT ;
    PORT
      LAYER metal2 ;
      RECT 61.905 0.000 61.975 0.210 ;
    END
  END rw0_rd_out[64]
  PIN rw0_rd_out[65]
    DIRECTION OUTPUT ;
    USE SIGNAL ;
    SHAPE ABUTMENT ;
    PORT
      LAYER metal2 ;
      RECT 62.095 0.000 62.165 0.210 ;
    END
  END rw0_rd_out[65]
  PIN rw0_rd_out[66]
    DIRECTION OUTPUT ;
    USE SIGNAL ;
    SHAPE ABUTMENT ;
    PORT
      LAYER metal2 ;
      RECT 62.285 0.000 62.355 0.210 ;
    END
  END rw0_rd_out[66]
  PIN rw0_rd_out[67]
    DIRECTION OUTPUT ;
    USE SIGNAL ;
    SHAPE ABUTMENT ;
    PORT
      LAYER metal2 ;
      RECT 62.475 0.000 62.545 0.210 ;
    END
  END rw0_rd_out[67]
  PIN rw0_rd_out[68]
    DIRECTION OUTPUT ;
    USE SIGNAL ;
    SHAPE ABUTMENT ;
    PORT
      LAYER metal2 ;
      RECT 62.665 0.000 62.735 0.210 ;
    END
  END rw0_rd_out[68]
  PIN rw0_rd_out[69]
    DIRECTION OUTPUT ;
    USE SIGNAL ;
    SHAPE ABUTMENT ;
    PORT
      LAYER metal2 ;
      RECT 62.855 0.000 62.925 0.210 ;
    END
  END rw0_rd_out[69]
  PIN rw0_rd_out[70]
    DIRECTION OUTPUT ;
    USE SIGNAL ;
    SHAPE ABUTMENT ;
    PORT
      LAYER metal2 ;
      RECT 63.045 0.000 63.115 0.210 ;
    END
  END rw0_rd_out[70]
  PIN rw0_rd_out[71]
    DIRECTION OUTPUT ;
    USE SIGNAL ;
    SHAPE ABUTMENT ;
    PORT
      LAYER metal2 ;
      RECT 63.235 0.000 63.305 0.210 ;
    END
  END rw0_rd_out[71]
  PIN rw0_rd_out[72]
    DIRECTION OUTPUT ;
    USE SIGNAL ;
    SHAPE ABUTMENT ;
    PORT
      LAYER metal2 ;
      RECT 63.425 0.000 63.495 0.210 ;
    END
  END rw0_rd_out[72]
  PIN rw0_rd_out[73]
    DIRECTION OUTPUT ;
    USE SIGNAL ;
    SHAPE ABUTMENT ;
    PORT
      LAYER metal2 ;
      RECT 63.615 0.000 63.685 0.210 ;
    END
  END rw0_rd_out[73]
  PIN rw0_rd_out[74]
    DIRECTION OUTPUT ;
    USE SIGNAL ;
    SHAPE ABUTMENT ;
    PORT
      LAYER metal2 ;
      RECT 63.805 0.000 63.875 0.210 ;
    END
  END rw0_rd_out[74]
  PIN rw0_rd_out[75]
    DIRECTION OUTPUT ;
    USE SIGNAL ;
    SHAPE ABUTMENT ;
    PORT
      LAYER metal2 ;
      RECT 63.995 0.000 64.065 0.210 ;
    END
  END rw0_rd_out[75]
  PIN rw0_rd_out[76]
    DIRECTION OUTPUT ;
    USE SIGNAL ;
    SHAPE ABUTMENT ;
    PORT
      LAYER metal2 ;
      RECT 64.185 0.000 64.255 0.210 ;
    END
  END rw0_rd_out[76]
  PIN rw0_rd_out[77]
    DIRECTION OUTPUT ;
    USE SIGNAL ;
    SHAPE ABUTMENT ;
    PORT
      LAYER metal2 ;
      RECT 64.375 0.000 64.445 0.210 ;
    END
  END rw0_rd_out[77]
  PIN rw0_rd_out[78]
    DIRECTION OUTPUT ;
    USE SIGNAL ;
    SHAPE ABUTMENT ;
    PORT
      LAYER metal2 ;
      RECT 64.565 0.000 64.635 0.210 ;
    END
  END rw0_rd_out[78]
  PIN rw0_rd_out[79]
    DIRECTION OUTPUT ;
    USE SIGNAL ;
    SHAPE ABUTMENT ;
    PORT
      LAYER metal2 ;
      RECT 64.755 0.000 64.825 0.210 ;
    END
  END rw0_rd_out[79]
  PIN rw0_rd_out[80]
    DIRECTION OUTPUT ;
    USE SIGNAL ;
    SHAPE ABUTMENT ;
    PORT
      LAYER metal2 ;
      RECT 64.945 0.000 65.015 0.210 ;
    END
  END rw0_rd_out[80]
  PIN rw0_rd_out[81]
    DIRECTION OUTPUT ;
    USE SIGNAL ;
    SHAPE ABUTMENT ;
    PORT
      LAYER metal2 ;
      RECT 65.135 0.000 65.205 0.210 ;
    END
  END rw0_rd_out[81]
  PIN rw0_rd_out[82]
    DIRECTION OUTPUT ;
    USE SIGNAL ;
    SHAPE ABUTMENT ;
    PORT
      LAYER metal2 ;
      RECT 65.325 0.000 65.395 0.210 ;
    END
  END rw0_rd_out[82]
  PIN rw0_rd_out[83]
    DIRECTION OUTPUT ;
    USE SIGNAL ;
    SHAPE ABUTMENT ;
    PORT
      LAYER metal2 ;
      RECT 65.515 0.000 65.585 0.210 ;
    END
  END rw0_rd_out[83]
  PIN rw0_rd_out[84]
    DIRECTION OUTPUT ;
    USE SIGNAL ;
    SHAPE ABUTMENT ;
    PORT
      LAYER metal2 ;
      RECT 65.705 0.000 65.775 0.210 ;
    END
  END rw0_rd_out[84]
  PIN rw0_rd_out[85]
    DIRECTION OUTPUT ;
    USE SIGNAL ;
    SHAPE ABUTMENT ;
    PORT
      LAYER metal2 ;
      RECT 65.895 0.000 65.965 0.210 ;
    END
  END rw0_rd_out[85]
  PIN rw0_rd_out[86]
    DIRECTION OUTPUT ;
    USE SIGNAL ;
    SHAPE ABUTMENT ;
    PORT
      LAYER metal2 ;
      RECT 66.085 0.000 66.155 0.210 ;
    END
  END rw0_rd_out[86]
  PIN rw0_rd_out[87]
    DIRECTION OUTPUT ;
    USE SIGNAL ;
    SHAPE ABUTMENT ;
    PORT
      LAYER metal2 ;
      RECT 66.275 0.000 66.345 0.210 ;
    END
  END rw0_rd_out[87]
  PIN rw0_rd_out[88]
    DIRECTION OUTPUT ;
    USE SIGNAL ;
    SHAPE ABUTMENT ;
    PORT
      LAYER metal2 ;
      RECT 66.465 0.000 66.535 0.210 ;
    END
  END rw0_rd_out[88]
  PIN rw0_rd_out[89]
    DIRECTION OUTPUT ;
    USE SIGNAL ;
    SHAPE ABUTMENT ;
    PORT
      LAYER metal2 ;
      RECT 66.655 0.000 66.725 0.210 ;
    END
  END rw0_rd_out[89]
  PIN rw0_rd_out[90]
    DIRECTION OUTPUT ;
    USE SIGNAL ;
    SHAPE ABUTMENT ;
    PORT
      LAYER metal2 ;
      RECT 66.845 0.000 66.915 0.210 ;
    END
  END rw0_rd_out[90]
  PIN rw0_rd_out[91]
    DIRECTION OUTPUT ;
    USE SIGNAL ;
    SHAPE ABUTMENT ;
    PORT
      LAYER metal2 ;
      RECT 67.035 0.000 67.105 0.210 ;
    END
  END rw0_rd_out[91]
  PIN rw0_rd_out[92]
    DIRECTION OUTPUT ;
    USE SIGNAL ;
    SHAPE ABUTMENT ;
    PORT
      LAYER metal2 ;
      RECT 67.225 0.000 67.295 0.210 ;
    END
  END rw0_rd_out[92]
  PIN rw0_rd_out[93]
    DIRECTION OUTPUT ;
    USE SIGNAL ;
    SHAPE ABUTMENT ;
    PORT
      LAYER metal2 ;
      RECT 67.415 0.000 67.485 0.210 ;
    END
  END rw0_rd_out[93]
  PIN rw0_rd_out[94]
    DIRECTION OUTPUT ;
    USE SIGNAL ;
    SHAPE ABUTMENT ;
    PORT
      LAYER metal2 ;
      RECT 67.605 0.000 67.675 0.210 ;
    END
  END rw0_rd_out[94]
  PIN rw0_rd_out[95]
    DIRECTION OUTPUT ;
    USE SIGNAL ;
    SHAPE ABUTMENT ;
    PORT
      LAYER metal2 ;
      RECT 67.795 0.000 67.865 0.210 ;
    END
  END rw0_rd_out[95]
  PIN rw0_rd_out[96]
    DIRECTION OUTPUT ;
    USE SIGNAL ;
    SHAPE ABUTMENT ;
    PORT
      LAYER metal2 ;
      RECT 67.985 0.000 68.055 0.210 ;
    END
  END rw0_rd_out[96]
  PIN rw0_rd_out[97]
    DIRECTION OUTPUT ;
    USE SIGNAL ;
    SHAPE ABUTMENT ;
    PORT
      LAYER metal2 ;
      RECT 68.175 0.000 68.245 0.210 ;
    END
  END rw0_rd_out[97]
  PIN rw0_rd_out[98]
    DIRECTION OUTPUT ;
    USE SIGNAL ;
    SHAPE ABUTMENT ;
    PORT
      LAYER metal2 ;
      RECT 68.365 0.000 68.435 0.210 ;
    END
  END rw0_rd_out[98]
  PIN rw0_rd_out[99]
    DIRECTION OUTPUT ;
    USE SIGNAL ;
    SHAPE ABUTMENT ;
    PORT
      LAYER metal2 ;
      RECT 68.555 0.000 68.625 0.210 ;
    END
  END rw0_rd_out[99]
  PIN rw0_rd_out[100]
    DIRECTION OUTPUT ;
    USE SIGNAL ;
    SHAPE ABUTMENT ;
    PORT
      LAYER metal2 ;
      RECT 68.745 0.000 68.815 0.210 ;
    END
  END rw0_rd_out[100]
  PIN rw0_rd_out[101]
    DIRECTION OUTPUT ;
    USE SIGNAL ;
    SHAPE ABUTMENT ;
    PORT
      LAYER metal2 ;
      RECT 68.935 0.000 69.005 0.210 ;
    END
  END rw0_rd_out[101]
  PIN rw0_rd_out[102]
    DIRECTION OUTPUT ;
    USE SIGNAL ;
    SHAPE ABUTMENT ;
    PORT
      LAYER metal2 ;
      RECT 69.125 0.000 69.195 0.210 ;
    END
  END rw0_rd_out[102]
  PIN rw0_rd_out[103]
    DIRECTION OUTPUT ;
    USE SIGNAL ;
    SHAPE ABUTMENT ;
    PORT
      LAYER metal2 ;
      RECT 69.315 0.000 69.385 0.210 ;
    END
  END rw0_rd_out[103]
  PIN rw0_rd_out[104]
    DIRECTION OUTPUT ;
    USE SIGNAL ;
    SHAPE ABUTMENT ;
    PORT
      LAYER metal2 ;
      RECT 69.505 0.000 69.575 0.210 ;
    END
  END rw0_rd_out[104]
  PIN rw0_rd_out[105]
    DIRECTION OUTPUT ;
    USE SIGNAL ;
    SHAPE ABUTMENT ;
    PORT
      LAYER metal2 ;
      RECT 69.695 0.000 69.765 0.210 ;
    END
  END rw0_rd_out[105]
  PIN rw0_rd_out[106]
    DIRECTION OUTPUT ;
    USE SIGNAL ;
    SHAPE ABUTMENT ;
    PORT
      LAYER metal2 ;
      RECT 69.885 0.000 69.955 0.210 ;
    END
  END rw0_rd_out[106]
  PIN rw0_rd_out[107]
    DIRECTION OUTPUT ;
    USE SIGNAL ;
    SHAPE ABUTMENT ;
    PORT
      LAYER metal2 ;
      RECT 70.075 0.000 70.145 0.210 ;
    END
  END rw0_rd_out[107]
  PIN rw0_rd_out[108]
    DIRECTION OUTPUT ;
    USE SIGNAL ;
    SHAPE ABUTMENT ;
    PORT
      LAYER metal2 ;
      RECT 70.265 0.000 70.335 0.210 ;
    END
  END rw0_rd_out[108]
  PIN rw0_rd_out[109]
    DIRECTION OUTPUT ;
    USE SIGNAL ;
    SHAPE ABUTMENT ;
    PORT
      LAYER metal2 ;
      RECT 70.455 0.000 70.525 0.210 ;
    END
  END rw0_rd_out[109]
  PIN rw0_rd_out[110]
    DIRECTION OUTPUT ;
    USE SIGNAL ;
    SHAPE ABUTMENT ;
    PORT
      LAYER metal2 ;
      RECT 70.645 0.000 70.715 0.210 ;
    END
  END rw0_rd_out[110]
  PIN rw0_rd_out[111]
    DIRECTION OUTPUT ;
    USE SIGNAL ;
    SHAPE ABUTMENT ;
    PORT
      LAYER metal2 ;
      RECT 70.835 0.000 70.905 0.210 ;
    END
  END rw0_rd_out[111]
  PIN rw0_rd_out[112]
    DIRECTION OUTPUT ;
    USE SIGNAL ;
    SHAPE ABUTMENT ;
    PORT
      LAYER metal2 ;
      RECT 71.025 0.000 71.095 0.210 ;
    END
  END rw0_rd_out[112]
  PIN rw0_rd_out[113]
    DIRECTION OUTPUT ;
    USE SIGNAL ;
    SHAPE ABUTMENT ;
    PORT
      LAYER metal2 ;
      RECT 71.215 0.000 71.285 0.210 ;
    END
  END rw0_rd_out[113]
  PIN rw0_rd_out[114]
    DIRECTION OUTPUT ;
    USE SIGNAL ;
    SHAPE ABUTMENT ;
    PORT
      LAYER metal2 ;
      RECT 71.405 0.000 71.475 0.210 ;
    END
  END rw0_rd_out[114]
  PIN rw0_rd_out[115]
    DIRECTION OUTPUT ;
    USE SIGNAL ;
    SHAPE ABUTMENT ;
    PORT
      LAYER metal2 ;
      RECT 71.595 0.000 71.665 0.210 ;
    END
  END rw0_rd_out[115]
  PIN rw0_rd_out[116]
    DIRECTION OUTPUT ;
    USE SIGNAL ;
    SHAPE ABUTMENT ;
    PORT
      LAYER metal2 ;
      RECT 71.785 0.000 71.855 0.210 ;
    END
  END rw0_rd_out[116]
  PIN rw0_rd_out[117]
    DIRECTION OUTPUT ;
    USE SIGNAL ;
    SHAPE ABUTMENT ;
    PORT
      LAYER metal2 ;
      RECT 71.975 0.000 72.045 0.210 ;
    END
  END rw0_rd_out[117]
  PIN rw0_rd_out[118]
    DIRECTION OUTPUT ;
    USE SIGNAL ;
    SHAPE ABUTMENT ;
    PORT
      LAYER metal2 ;
      RECT 72.165 0.000 72.235 0.210 ;
    END
  END rw0_rd_out[118]
  PIN rw0_rd_out[119]
    DIRECTION OUTPUT ;
    USE SIGNAL ;
    SHAPE ABUTMENT ;
    PORT
      LAYER metal2 ;
      RECT 72.355 0.000 72.425 0.210 ;
    END
  END rw0_rd_out[119]
  PIN rw0_rd_out[120]
    DIRECTION OUTPUT ;
    USE SIGNAL ;
    SHAPE ABUTMENT ;
    PORT
      LAYER metal2 ;
      RECT 72.545 0.000 72.615 0.210 ;
    END
  END rw0_rd_out[120]
  PIN rw0_rd_out[121]
    DIRECTION OUTPUT ;
    USE SIGNAL ;
    SHAPE ABUTMENT ;
    PORT
      LAYER metal2 ;
      RECT 72.735 0.000 72.805 0.210 ;
    END
  END rw0_rd_out[121]
  PIN rw0_rd_out[122]
    DIRECTION OUTPUT ;
    USE SIGNAL ;
    SHAPE ABUTMENT ;
    PORT
      LAYER metal2 ;
      RECT 72.925 0.000 72.995 0.210 ;
    END
  END rw0_rd_out[122]
  PIN rw0_rd_out[123]
    DIRECTION OUTPUT ;
    USE SIGNAL ;
    SHAPE ABUTMENT ;
    PORT
      LAYER metal2 ;
      RECT 73.115 0.000 73.185 0.210 ;
    END
  END rw0_rd_out[123]
  PIN rw0_rd_out[124]
    DIRECTION OUTPUT ;
    USE SIGNAL ;
    SHAPE ABUTMENT ;
    PORT
      LAYER metal2 ;
      RECT 73.305 0.000 73.375 0.210 ;
    END
  END rw0_rd_out[124]
  PIN rw0_rd_out[125]
    DIRECTION OUTPUT ;
    USE SIGNAL ;
    SHAPE ABUTMENT ;
    PORT
      LAYER metal2 ;
      RECT 73.495 0.000 73.565 0.210 ;
    END
  END rw0_rd_out[125]
  PIN rw0_rd_out[126]
    DIRECTION OUTPUT ;
    USE SIGNAL ;
    SHAPE ABUTMENT ;
    PORT
      LAYER metal2 ;
      RECT 73.685 0.000 73.755 0.210 ;
    END
  END rw0_rd_out[126]
  PIN rw0_rd_out[127]
    DIRECTION OUTPUT ;
    USE SIGNAL ;
    SHAPE ABUTMENT ;
    PORT
      LAYER metal2 ;
      RECT 73.875 0.000 73.945 0.210 ;
    END
  END rw0_rd_out[127]
  PIN rw0_rd_out[128]
    DIRECTION OUTPUT ;
    USE SIGNAL ;
    SHAPE ABUTMENT ;
    PORT
      LAYER metal2 ;
      RECT 74.065 0.000 74.135 0.210 ;
    END
  END rw0_rd_out[128]
  PIN rw0_rd_out[129]
    DIRECTION OUTPUT ;
    USE SIGNAL ;
    SHAPE ABUTMENT ;
    PORT
      LAYER metal2 ;
      RECT 74.255 0.000 74.325 0.210 ;
    END
  END rw0_rd_out[129]
  PIN rw0_rd_out[130]
    DIRECTION OUTPUT ;
    USE SIGNAL ;
    SHAPE ABUTMENT ;
    PORT
      LAYER metal2 ;
      RECT 74.445 0.000 74.515 0.210 ;
    END
  END rw0_rd_out[130]
  PIN rw0_rd_out[131]
    DIRECTION OUTPUT ;
    USE SIGNAL ;
    SHAPE ABUTMENT ;
    PORT
      LAYER metal2 ;
      RECT 74.635 0.000 74.705 0.210 ;
    END
  END rw0_rd_out[131]
  PIN rw0_rd_out[132]
    DIRECTION OUTPUT ;
    USE SIGNAL ;
    SHAPE ABUTMENT ;
    PORT
      LAYER metal2 ;
      RECT 74.825 0.000 74.895 0.210 ;
    END
  END rw0_rd_out[132]
  PIN rw0_rd_out[133]
    DIRECTION OUTPUT ;
    USE SIGNAL ;
    SHAPE ABUTMENT ;
    PORT
      LAYER metal2 ;
      RECT 75.015 0.000 75.085 0.210 ;
    END
  END rw0_rd_out[133]
  PIN rw0_rd_out[134]
    DIRECTION OUTPUT ;
    USE SIGNAL ;
    SHAPE ABUTMENT ;
    PORT
      LAYER metal2 ;
      RECT 75.205 0.000 75.275 0.210 ;
    END
  END rw0_rd_out[134]
  PIN rw0_rd_out[135]
    DIRECTION OUTPUT ;
    USE SIGNAL ;
    SHAPE ABUTMENT ;
    PORT
      LAYER metal2 ;
      RECT 75.395 0.000 75.465 0.210 ;
    END
  END rw0_rd_out[135]
  PIN rw0_rd_out[136]
    DIRECTION OUTPUT ;
    USE SIGNAL ;
    SHAPE ABUTMENT ;
    PORT
      LAYER metal2 ;
      RECT 75.585 0.000 75.655 0.210 ;
    END
  END rw0_rd_out[136]
  PIN rw0_rd_out[137]
    DIRECTION OUTPUT ;
    USE SIGNAL ;
    SHAPE ABUTMENT ;
    PORT
      LAYER metal2 ;
      RECT 75.775 0.000 75.845 0.210 ;
    END
  END rw0_rd_out[137]
  PIN rw0_rd_out[138]
    DIRECTION OUTPUT ;
    USE SIGNAL ;
    SHAPE ABUTMENT ;
    PORT
      LAYER metal2 ;
      RECT 75.965 0.000 76.035 0.210 ;
    END
  END rw0_rd_out[138]
  PIN rw0_rd_out[139]
    DIRECTION OUTPUT ;
    USE SIGNAL ;
    SHAPE ABUTMENT ;
    PORT
      LAYER metal2 ;
      RECT 76.155 0.000 76.225 0.210 ;
    END
  END rw0_rd_out[139]
  PIN rw0_rd_out[140]
    DIRECTION OUTPUT ;
    USE SIGNAL ;
    SHAPE ABUTMENT ;
    PORT
      LAYER metal2 ;
      RECT 76.345 0.000 76.415 0.210 ;
    END
  END rw0_rd_out[140]
  PIN rw0_rd_out[141]
    DIRECTION OUTPUT ;
    USE SIGNAL ;
    SHAPE ABUTMENT ;
    PORT
      LAYER metal2 ;
      RECT 76.535 0.000 76.605 0.210 ;
    END
  END rw0_rd_out[141]
  PIN rw0_rd_out[142]
    DIRECTION OUTPUT ;
    USE SIGNAL ;
    SHAPE ABUTMENT ;
    PORT
      LAYER metal2 ;
      RECT 76.725 0.000 76.795 0.210 ;
    END
  END rw0_rd_out[142]
  PIN rw0_rd_out[143]
    DIRECTION OUTPUT ;
    USE SIGNAL ;
    SHAPE ABUTMENT ;
    PORT
      LAYER metal2 ;
      RECT 76.915 0.000 76.985 0.210 ;
    END
  END rw0_rd_out[143]
  PIN rw0_rd_out[144]
    DIRECTION OUTPUT ;
    USE SIGNAL ;
    SHAPE ABUTMENT ;
    PORT
      LAYER metal2 ;
      RECT 77.105 0.000 77.175 0.210 ;
    END
  END rw0_rd_out[144]
  PIN rw0_rd_out[145]
    DIRECTION OUTPUT ;
    USE SIGNAL ;
    SHAPE ABUTMENT ;
    PORT
      LAYER metal2 ;
      RECT 77.295 0.000 77.365 0.210 ;
    END
  END rw0_rd_out[145]
  PIN rw0_rd_out[146]
    DIRECTION OUTPUT ;
    USE SIGNAL ;
    SHAPE ABUTMENT ;
    PORT
      LAYER metal2 ;
      RECT 77.485 0.000 77.555 0.210 ;
    END
  END rw0_rd_out[146]
  PIN rw0_rd_out[147]
    DIRECTION OUTPUT ;
    USE SIGNAL ;
    SHAPE ABUTMENT ;
    PORT
      LAYER metal2 ;
      RECT 77.675 0.000 77.745 0.210 ;
    END
  END rw0_rd_out[147]
  PIN rw0_rd_out[148]
    DIRECTION OUTPUT ;
    USE SIGNAL ;
    SHAPE ABUTMENT ;
    PORT
      LAYER metal2 ;
      RECT 77.865 0.000 77.935 0.210 ;
    END
  END rw0_rd_out[148]
  PIN rw0_rd_out[149]
    DIRECTION OUTPUT ;
    USE SIGNAL ;
    SHAPE ABUTMENT ;
    PORT
      LAYER metal2 ;
      RECT 78.055 0.000 78.125 0.210 ;
    END
  END rw0_rd_out[149]
  PIN rw0_rd_out[150]
    DIRECTION OUTPUT ;
    USE SIGNAL ;
    SHAPE ABUTMENT ;
    PORT
      LAYER metal2 ;
      RECT 78.245 0.000 78.315 0.210 ;
    END
  END rw0_rd_out[150]
  PIN rw0_rd_out[151]
    DIRECTION OUTPUT ;
    USE SIGNAL ;
    SHAPE ABUTMENT ;
    PORT
      LAYER metal2 ;
      RECT 78.435 0.000 78.505 0.210 ;
    END
  END rw0_rd_out[151]
  PIN rw0_rd_out[152]
    DIRECTION OUTPUT ;
    USE SIGNAL ;
    SHAPE ABUTMENT ;
    PORT
      LAYER metal2 ;
      RECT 78.625 0.000 78.695 0.210 ;
    END
  END rw0_rd_out[152]
  PIN rw0_rd_out[153]
    DIRECTION OUTPUT ;
    USE SIGNAL ;
    SHAPE ABUTMENT ;
    PORT
      LAYER metal2 ;
      RECT 78.815 0.000 78.885 0.210 ;
    END
  END rw0_rd_out[153]
  PIN rw0_rd_out[154]
    DIRECTION OUTPUT ;
    USE SIGNAL ;
    SHAPE ABUTMENT ;
    PORT
      LAYER metal2 ;
      RECT 79.005 0.000 79.075 0.210 ;
    END
  END rw0_rd_out[154]
  PIN rw0_rd_out[155]
    DIRECTION OUTPUT ;
    USE SIGNAL ;
    SHAPE ABUTMENT ;
    PORT
      LAYER metal2 ;
      RECT 79.195 0.000 79.265 0.210 ;
    END
  END rw0_rd_out[155]
  PIN rw0_rd_out[156]
    DIRECTION OUTPUT ;
    USE SIGNAL ;
    SHAPE ABUTMENT ;
    PORT
      LAYER metal2 ;
      RECT 79.385 0.000 79.455 0.210 ;
    END
  END rw0_rd_out[156]
  PIN rw0_rd_out[157]
    DIRECTION OUTPUT ;
    USE SIGNAL ;
    SHAPE ABUTMENT ;
    PORT
      LAYER metal2 ;
      RECT 79.575 0.000 79.645 0.210 ;
    END
  END rw0_rd_out[157]
  PIN rw0_rd_out[158]
    DIRECTION OUTPUT ;
    USE SIGNAL ;
    SHAPE ABUTMENT ;
    PORT
      LAYER metal2 ;
      RECT 79.765 0.000 79.835 0.210 ;
    END
  END rw0_rd_out[158]
  PIN rw0_rd_out[159]
    DIRECTION OUTPUT ;
    USE SIGNAL ;
    SHAPE ABUTMENT ;
    PORT
      LAYER metal2 ;
      RECT 79.955 0.000 80.025 0.210 ;
    END
  END rw0_rd_out[159]
  PIN rw0_rd_out[160]
    DIRECTION OUTPUT ;
    USE SIGNAL ;
    SHAPE ABUTMENT ;
    PORT
      LAYER metal2 ;
      RECT 80.145 0.000 80.215 0.210 ;
    END
  END rw0_rd_out[160]
  PIN rw0_rd_out[161]
    DIRECTION OUTPUT ;
    USE SIGNAL ;
    SHAPE ABUTMENT ;
    PORT
      LAYER metal2 ;
      RECT 80.335 0.000 80.405 0.210 ;
    END
  END rw0_rd_out[161]
  PIN rw0_rd_out[162]
    DIRECTION OUTPUT ;
    USE SIGNAL ;
    SHAPE ABUTMENT ;
    PORT
      LAYER metal2 ;
      RECT 80.525 0.000 80.595 0.210 ;
    END
  END rw0_rd_out[162]
  PIN rw0_rd_out[163]
    DIRECTION OUTPUT ;
    USE SIGNAL ;
    SHAPE ABUTMENT ;
    PORT
      LAYER metal2 ;
      RECT 80.715 0.000 80.785 0.210 ;
    END
  END rw0_rd_out[163]
  PIN rw0_rd_out[164]
    DIRECTION OUTPUT ;
    USE SIGNAL ;
    SHAPE ABUTMENT ;
    PORT
      LAYER metal2 ;
      RECT 80.905 0.000 80.975 0.210 ;
    END
  END rw0_rd_out[164]
  PIN rw0_rd_out[165]
    DIRECTION OUTPUT ;
    USE SIGNAL ;
    SHAPE ABUTMENT ;
    PORT
      LAYER metal2 ;
      RECT 81.095 0.000 81.165 0.210 ;
    END
  END rw0_rd_out[165]
  PIN rw0_rd_out[166]
    DIRECTION OUTPUT ;
    USE SIGNAL ;
    SHAPE ABUTMENT ;
    PORT
      LAYER metal2 ;
      RECT 81.285 0.000 81.355 0.210 ;
    END
  END rw0_rd_out[166]
  PIN rw0_rd_out[167]
    DIRECTION OUTPUT ;
    USE SIGNAL ;
    SHAPE ABUTMENT ;
    PORT
      LAYER metal2 ;
      RECT 81.475 0.000 81.545 0.210 ;
    END
  END rw0_rd_out[167]
  PIN rw0_rd_out[168]
    DIRECTION OUTPUT ;
    USE SIGNAL ;
    SHAPE ABUTMENT ;
    PORT
      LAYER metal2 ;
      RECT 81.665 0.000 81.735 0.210 ;
    END
  END rw0_rd_out[168]
  PIN rw0_rd_out[169]
    DIRECTION OUTPUT ;
    USE SIGNAL ;
    SHAPE ABUTMENT ;
    PORT
      LAYER metal2 ;
      RECT 81.855 0.000 81.925 0.210 ;
    END
  END rw0_rd_out[169]
  PIN rw0_rd_out[170]
    DIRECTION OUTPUT ;
    USE SIGNAL ;
    SHAPE ABUTMENT ;
    PORT
      LAYER metal2 ;
      RECT 82.045 0.000 82.115 0.210 ;
    END
  END rw0_rd_out[170]
  PIN rw0_rd_out[171]
    DIRECTION OUTPUT ;
    USE SIGNAL ;
    SHAPE ABUTMENT ;
    PORT
      LAYER metal2 ;
      RECT 82.235 0.000 82.305 0.210 ;
    END
  END rw0_rd_out[171]
  PIN rw0_rd_out[172]
    DIRECTION OUTPUT ;
    USE SIGNAL ;
    SHAPE ABUTMENT ;
    PORT
      LAYER metal2 ;
      RECT 82.425 0.000 82.495 0.210 ;
    END
  END rw0_rd_out[172]
  PIN rw0_rd_out[173]
    DIRECTION OUTPUT ;
    USE SIGNAL ;
    SHAPE ABUTMENT ;
    PORT
      LAYER metal2 ;
      RECT 82.615 0.000 82.685 0.210 ;
    END
  END rw0_rd_out[173]
  PIN rw0_rd_out[174]
    DIRECTION OUTPUT ;
    USE SIGNAL ;
    SHAPE ABUTMENT ;
    PORT
      LAYER metal2 ;
      RECT 82.805 0.000 82.875 0.210 ;
    END
  END rw0_rd_out[174]
  PIN rw0_rd_out[175]
    DIRECTION OUTPUT ;
    USE SIGNAL ;
    SHAPE ABUTMENT ;
    PORT
      LAYER metal2 ;
      RECT 82.995 0.000 83.065 0.210 ;
    END
  END rw0_rd_out[175]
  PIN rw0_rd_out[176]
    DIRECTION OUTPUT ;
    USE SIGNAL ;
    SHAPE ABUTMENT ;
    PORT
      LAYER metal2 ;
      RECT 83.185 0.000 83.255 0.210 ;
    END
  END rw0_rd_out[176]
  PIN rw0_rd_out[177]
    DIRECTION OUTPUT ;
    USE SIGNAL ;
    SHAPE ABUTMENT ;
    PORT
      LAYER metal2 ;
      RECT 83.375 0.000 83.445 0.210 ;
    END
  END rw0_rd_out[177]
  PIN rw0_rd_out[178]
    DIRECTION OUTPUT ;
    USE SIGNAL ;
    SHAPE ABUTMENT ;
    PORT
      LAYER metal2 ;
      RECT 83.565 0.000 83.635 0.210 ;
    END
  END rw0_rd_out[178]
  PIN rw0_rd_out[179]
    DIRECTION OUTPUT ;
    USE SIGNAL ;
    SHAPE ABUTMENT ;
    PORT
      LAYER metal2 ;
      RECT 83.755 0.000 83.825 0.210 ;
    END
  END rw0_rd_out[179]
  PIN rw0_rd_out[180]
    DIRECTION OUTPUT ;
    USE SIGNAL ;
    SHAPE ABUTMENT ;
    PORT
      LAYER metal2 ;
      RECT 83.945 0.000 84.015 0.210 ;
    END
  END rw0_rd_out[180]
  PIN rw0_rd_out[181]
    DIRECTION OUTPUT ;
    USE SIGNAL ;
    SHAPE ABUTMENT ;
    PORT
      LAYER metal2 ;
      RECT 84.135 0.000 84.205 0.210 ;
    END
  END rw0_rd_out[181]
  PIN rw0_rd_out[182]
    DIRECTION OUTPUT ;
    USE SIGNAL ;
    SHAPE ABUTMENT ;
    PORT
      LAYER metal2 ;
      RECT 84.325 0.000 84.395 0.210 ;
    END
  END rw0_rd_out[182]
  PIN rw0_rd_out[183]
    DIRECTION OUTPUT ;
    USE SIGNAL ;
    SHAPE ABUTMENT ;
    PORT
      LAYER metal2 ;
      RECT 84.515 0.000 84.585 0.210 ;
    END
  END rw0_rd_out[183]
  PIN rw0_rd_out[184]
    DIRECTION OUTPUT ;
    USE SIGNAL ;
    SHAPE ABUTMENT ;
    PORT
      LAYER metal2 ;
      RECT 84.705 0.000 84.775 0.210 ;
    END
  END rw0_rd_out[184]
  PIN rw0_rd_out[185]
    DIRECTION OUTPUT ;
    USE SIGNAL ;
    SHAPE ABUTMENT ;
    PORT
      LAYER metal2 ;
      RECT 84.895 0.000 84.965 0.210 ;
    END
  END rw0_rd_out[185]
  PIN rw0_rd_out[186]
    DIRECTION OUTPUT ;
    USE SIGNAL ;
    SHAPE ABUTMENT ;
    PORT
      LAYER metal2 ;
      RECT 85.085 0.000 85.155 0.210 ;
    END
  END rw0_rd_out[186]
  PIN rw0_rd_out[187]
    DIRECTION OUTPUT ;
    USE SIGNAL ;
    SHAPE ABUTMENT ;
    PORT
      LAYER metal2 ;
      RECT 85.275 0.000 85.345 0.210 ;
    END
  END rw0_rd_out[187]
  PIN rw0_rd_out[188]
    DIRECTION OUTPUT ;
    USE SIGNAL ;
    SHAPE ABUTMENT ;
    PORT
      LAYER metal2 ;
      RECT 85.465 0.000 85.535 0.210 ;
    END
  END rw0_rd_out[188]
  PIN rw0_rd_out[189]
    DIRECTION OUTPUT ;
    USE SIGNAL ;
    SHAPE ABUTMENT ;
    PORT
      LAYER metal2 ;
      RECT 85.655 0.000 85.725 0.210 ;
    END
  END rw0_rd_out[189]
  PIN rw0_rd_out[190]
    DIRECTION OUTPUT ;
    USE SIGNAL ;
    SHAPE ABUTMENT ;
    PORT
      LAYER metal2 ;
      RECT 85.845 0.000 85.915 0.210 ;
    END
  END rw0_rd_out[190]
  PIN rw0_rd_out[191]
    DIRECTION OUTPUT ;
    USE SIGNAL ;
    SHAPE ABUTMENT ;
    PORT
      LAYER metal2 ;
      RECT 86.035 0.000 86.105 0.210 ;
    END
  END rw0_rd_out[191]
  PIN rw0_rd_out[192]
    DIRECTION OUTPUT ;
    USE SIGNAL ;
    SHAPE ABUTMENT ;
    PORT
      LAYER metal2 ;
      RECT 86.225 0.000 86.295 0.210 ;
    END
  END rw0_rd_out[192]
  PIN rw0_rd_out[193]
    DIRECTION OUTPUT ;
    USE SIGNAL ;
    SHAPE ABUTMENT ;
    PORT
      LAYER metal2 ;
      RECT 86.415 0.000 86.485 0.210 ;
    END
  END rw0_rd_out[193]
  PIN rw0_rd_out[194]
    DIRECTION OUTPUT ;
    USE SIGNAL ;
    SHAPE ABUTMENT ;
    PORT
      LAYER metal2 ;
      RECT 86.605 0.000 86.675 0.210 ;
    END
  END rw0_rd_out[194]
  PIN rw0_rd_out[195]
    DIRECTION OUTPUT ;
    USE SIGNAL ;
    SHAPE ABUTMENT ;
    PORT
      LAYER metal2 ;
      RECT 86.795 0.000 86.865 0.210 ;
    END
  END rw0_rd_out[195]
  PIN rw0_rd_out[196]
    DIRECTION OUTPUT ;
    USE SIGNAL ;
    SHAPE ABUTMENT ;
    PORT
      LAYER metal2 ;
      RECT 86.985 0.000 87.055 0.210 ;
    END
  END rw0_rd_out[196]
  PIN rw0_rd_out[197]
    DIRECTION OUTPUT ;
    USE SIGNAL ;
    SHAPE ABUTMENT ;
    PORT
      LAYER metal2 ;
      RECT 87.175 0.000 87.245 0.210 ;
    END
  END rw0_rd_out[197]
  PIN rw0_rd_out[198]
    DIRECTION OUTPUT ;
    USE SIGNAL ;
    SHAPE ABUTMENT ;
    PORT
      LAYER metal2 ;
      RECT 87.365 0.000 87.435 0.210 ;
    END
  END rw0_rd_out[198]
  PIN rw0_rd_out[199]
    DIRECTION OUTPUT ;
    USE SIGNAL ;
    SHAPE ABUTMENT ;
    PORT
      LAYER metal2 ;
      RECT 87.555 0.000 87.625 0.210 ;
    END
  END rw0_rd_out[199]
  PIN rw0_rd_out[200]
    DIRECTION OUTPUT ;
    USE SIGNAL ;
    SHAPE ABUTMENT ;
    PORT
      LAYER metal2 ;
      RECT 87.745 0.000 87.815 0.210 ;
    END
  END rw0_rd_out[200]
  PIN rw0_rd_out[201]
    DIRECTION OUTPUT ;
    USE SIGNAL ;
    SHAPE ABUTMENT ;
    PORT
      LAYER metal2 ;
      RECT 87.935 0.000 88.005 0.210 ;
    END
  END rw0_rd_out[201]
  PIN rw0_rd_out[202]
    DIRECTION OUTPUT ;
    USE SIGNAL ;
    SHAPE ABUTMENT ;
    PORT
      LAYER metal2 ;
      RECT 88.125 0.000 88.195 0.210 ;
    END
  END rw0_rd_out[202]
  PIN rw0_rd_out[203]
    DIRECTION OUTPUT ;
    USE SIGNAL ;
    SHAPE ABUTMENT ;
    PORT
      LAYER metal2 ;
      RECT 88.315 0.000 88.385 0.210 ;
    END
  END rw0_rd_out[203]
  PIN rw0_rd_out[204]
    DIRECTION OUTPUT ;
    USE SIGNAL ;
    SHAPE ABUTMENT ;
    PORT
      LAYER metal2 ;
      RECT 88.505 0.000 88.575 0.210 ;
    END
  END rw0_rd_out[204]
  PIN rw0_rd_out[205]
    DIRECTION OUTPUT ;
    USE SIGNAL ;
    SHAPE ABUTMENT ;
    PORT
      LAYER metal2 ;
      RECT 88.695 0.000 88.765 0.210 ;
    END
  END rw0_rd_out[205]
  PIN rw0_rd_out[206]
    DIRECTION OUTPUT ;
    USE SIGNAL ;
    SHAPE ABUTMENT ;
    PORT
      LAYER metal2 ;
      RECT 88.885 0.000 88.955 0.210 ;
    END
  END rw0_rd_out[206]
  PIN rw0_rd_out[207]
    DIRECTION OUTPUT ;
    USE SIGNAL ;
    SHAPE ABUTMENT ;
    PORT
      LAYER metal2 ;
      RECT 89.075 0.000 89.145 0.210 ;
    END
  END rw0_rd_out[207]
  PIN rw0_rd_out[208]
    DIRECTION OUTPUT ;
    USE SIGNAL ;
    SHAPE ABUTMENT ;
    PORT
      LAYER metal2 ;
      RECT 89.265 0.000 89.335 0.210 ;
    END
  END rw0_rd_out[208]
  PIN rw0_rd_out[209]
    DIRECTION OUTPUT ;
    USE SIGNAL ;
    SHAPE ABUTMENT ;
    PORT
      LAYER metal2 ;
      RECT 89.455 0.000 89.525 0.210 ;
    END
  END rw0_rd_out[209]
  PIN rw0_rd_out[210]
    DIRECTION OUTPUT ;
    USE SIGNAL ;
    SHAPE ABUTMENT ;
    PORT
      LAYER metal2 ;
      RECT 89.645 0.000 89.715 0.210 ;
    END
  END rw0_rd_out[210]
  PIN rw0_rd_out[211]
    DIRECTION OUTPUT ;
    USE SIGNAL ;
    SHAPE ABUTMENT ;
    PORT
      LAYER metal2 ;
      RECT 89.835 0.000 89.905 0.210 ;
    END
  END rw0_rd_out[211]
  PIN rw0_rd_out[212]
    DIRECTION OUTPUT ;
    USE SIGNAL ;
    SHAPE ABUTMENT ;
    PORT
      LAYER metal2 ;
      RECT 90.025 0.000 90.095 0.210 ;
    END
  END rw0_rd_out[212]
  PIN rw0_rd_out[213]
    DIRECTION OUTPUT ;
    USE SIGNAL ;
    SHAPE ABUTMENT ;
    PORT
      LAYER metal2 ;
      RECT 90.215 0.000 90.285 0.210 ;
    END
  END rw0_rd_out[213]
  PIN rw0_rd_out[214]
    DIRECTION OUTPUT ;
    USE SIGNAL ;
    SHAPE ABUTMENT ;
    PORT
      LAYER metal2 ;
      RECT 90.405 0.000 90.475 0.210 ;
    END
  END rw0_rd_out[214]
  PIN rw0_rd_out[215]
    DIRECTION OUTPUT ;
    USE SIGNAL ;
    SHAPE ABUTMENT ;
    PORT
      LAYER metal2 ;
      RECT 90.595 0.000 90.665 0.210 ;
    END
  END rw0_rd_out[215]
  PIN rw0_rd_out[216]
    DIRECTION OUTPUT ;
    USE SIGNAL ;
    SHAPE ABUTMENT ;
    PORT
      LAYER metal2 ;
      RECT 90.785 0.000 90.855 0.210 ;
    END
  END rw0_rd_out[216]
  PIN rw0_rd_out[217]
    DIRECTION OUTPUT ;
    USE SIGNAL ;
    SHAPE ABUTMENT ;
    PORT
      LAYER metal2 ;
      RECT 90.975 0.000 91.045 0.210 ;
    END
  END rw0_rd_out[217]
  PIN rw0_rd_out[218]
    DIRECTION OUTPUT ;
    USE SIGNAL ;
    SHAPE ABUTMENT ;
    PORT
      LAYER metal2 ;
      RECT 91.165 0.000 91.235 0.210 ;
    END
  END rw0_rd_out[218]
  PIN rw0_rd_out[219]
    DIRECTION OUTPUT ;
    USE SIGNAL ;
    SHAPE ABUTMENT ;
    PORT
      LAYER metal2 ;
      RECT 91.355 0.000 91.425 0.210 ;
    END
  END rw0_rd_out[219]
  PIN rw0_rd_out[220]
    DIRECTION OUTPUT ;
    USE SIGNAL ;
    SHAPE ABUTMENT ;
    PORT
      LAYER metal2 ;
      RECT 91.545 0.000 91.615 0.210 ;
    END
  END rw0_rd_out[220]
  PIN rw0_rd_out[221]
    DIRECTION OUTPUT ;
    USE SIGNAL ;
    SHAPE ABUTMENT ;
    PORT
      LAYER metal2 ;
      RECT 91.735 0.000 91.805 0.210 ;
    END
  END rw0_rd_out[221]
  PIN rw0_rd_out[222]
    DIRECTION OUTPUT ;
    USE SIGNAL ;
    SHAPE ABUTMENT ;
    PORT
      LAYER metal2 ;
      RECT 91.925 0.000 91.995 0.210 ;
    END
  END rw0_rd_out[222]
  PIN rw0_rd_out[223]
    DIRECTION OUTPUT ;
    USE SIGNAL ;
    SHAPE ABUTMENT ;
    PORT
      LAYER metal2 ;
      RECT 92.115 0.000 92.185 0.210 ;
    END
  END rw0_rd_out[223]
  PIN rw0_rd_out[224]
    DIRECTION OUTPUT ;
    USE SIGNAL ;
    SHAPE ABUTMENT ;
    PORT
      LAYER metal2 ;
      RECT 92.305 0.000 92.375 0.210 ;
    END
  END rw0_rd_out[224]
  PIN rw0_rd_out[225]
    DIRECTION OUTPUT ;
    USE SIGNAL ;
    SHAPE ABUTMENT ;
    PORT
      LAYER metal2 ;
      RECT 92.495 0.000 92.565 0.210 ;
    END
  END rw0_rd_out[225]
  PIN rw0_rd_out[226]
    DIRECTION OUTPUT ;
    USE SIGNAL ;
    SHAPE ABUTMENT ;
    PORT
      LAYER metal2 ;
      RECT 92.685 0.000 92.755 0.210 ;
    END
  END rw0_rd_out[226]
  PIN rw0_rd_out[227]
    DIRECTION OUTPUT ;
    USE SIGNAL ;
    SHAPE ABUTMENT ;
    PORT
      LAYER metal2 ;
      RECT 92.875 0.000 92.945 0.210 ;
    END
  END rw0_rd_out[227]
  PIN rw0_rd_out[228]
    DIRECTION OUTPUT ;
    USE SIGNAL ;
    SHAPE ABUTMENT ;
    PORT
      LAYER metal2 ;
      RECT 93.065 0.000 93.135 0.210 ;
    END
  END rw0_rd_out[228]
  PIN rw0_rd_out[229]
    DIRECTION OUTPUT ;
    USE SIGNAL ;
    SHAPE ABUTMENT ;
    PORT
      LAYER metal2 ;
      RECT 93.255 0.000 93.325 0.210 ;
    END
  END rw0_rd_out[229]
  PIN rw0_rd_out[230]
    DIRECTION OUTPUT ;
    USE SIGNAL ;
    SHAPE ABUTMENT ;
    PORT
      LAYER metal2 ;
      RECT 93.445 0.000 93.515 0.210 ;
    END
  END rw0_rd_out[230]
  PIN rw0_rd_out[231]
    DIRECTION OUTPUT ;
    USE SIGNAL ;
    SHAPE ABUTMENT ;
    PORT
      LAYER metal2 ;
      RECT 93.635 0.000 93.705 0.210 ;
    END
  END rw0_rd_out[231]
  PIN rw0_rd_out[232]
    DIRECTION OUTPUT ;
    USE SIGNAL ;
    SHAPE ABUTMENT ;
    PORT
      LAYER metal2 ;
      RECT 93.825 0.000 93.895 0.210 ;
    END
  END rw0_rd_out[232]
  PIN rw0_rd_out[233]
    DIRECTION OUTPUT ;
    USE SIGNAL ;
    SHAPE ABUTMENT ;
    PORT
      LAYER metal2 ;
      RECT 94.015 0.000 94.085 0.210 ;
    END
  END rw0_rd_out[233]
  PIN rw0_rd_out[234]
    DIRECTION OUTPUT ;
    USE SIGNAL ;
    SHAPE ABUTMENT ;
    PORT
      LAYER metal2 ;
      RECT 94.205 0.000 94.275 0.210 ;
    END
  END rw0_rd_out[234]
  PIN rw0_rd_out[235]
    DIRECTION OUTPUT ;
    USE SIGNAL ;
    SHAPE ABUTMENT ;
    PORT
      LAYER metal2 ;
      RECT 94.395 0.000 94.465 0.210 ;
    END
  END rw0_rd_out[235]
  PIN rw0_rd_out[236]
    DIRECTION OUTPUT ;
    USE SIGNAL ;
    SHAPE ABUTMENT ;
    PORT
      LAYER metal2 ;
      RECT 94.585 0.000 94.655 0.210 ;
    END
  END rw0_rd_out[236]
  PIN rw0_rd_out[237]
    DIRECTION OUTPUT ;
    USE SIGNAL ;
    SHAPE ABUTMENT ;
    PORT
      LAYER metal2 ;
      RECT 94.775 0.000 94.845 0.210 ;
    END
  END rw0_rd_out[237]
  PIN rw0_rd_out[238]
    DIRECTION OUTPUT ;
    USE SIGNAL ;
    SHAPE ABUTMENT ;
    PORT
      LAYER metal2 ;
      RECT 94.965 0.000 95.035 0.210 ;
    END
  END rw0_rd_out[238]
  PIN rw0_rd_out[239]
    DIRECTION OUTPUT ;
    USE SIGNAL ;
    SHAPE ABUTMENT ;
    PORT
      LAYER metal2 ;
      RECT 95.155 0.000 95.225 0.210 ;
    END
  END rw0_rd_out[239]
  PIN rw0_rd_out[240]
    DIRECTION OUTPUT ;
    USE SIGNAL ;
    SHAPE ABUTMENT ;
    PORT
      LAYER metal2 ;
      RECT 95.345 0.000 95.415 0.210 ;
    END
  END rw0_rd_out[240]
  PIN rw0_rd_out[241]
    DIRECTION OUTPUT ;
    USE SIGNAL ;
    SHAPE ABUTMENT ;
    PORT
      LAYER metal2 ;
      RECT 95.535 0.000 95.605 0.210 ;
    END
  END rw0_rd_out[241]
  PIN rw0_rd_out[242]
    DIRECTION OUTPUT ;
    USE SIGNAL ;
    SHAPE ABUTMENT ;
    PORT
      LAYER metal2 ;
      RECT 95.725 0.000 95.795 0.210 ;
    END
  END rw0_rd_out[242]
  PIN rw0_rd_out[243]
    DIRECTION OUTPUT ;
    USE SIGNAL ;
    SHAPE ABUTMENT ;
    PORT
      LAYER metal2 ;
      RECT 95.915 0.000 95.985 0.210 ;
    END
  END rw0_rd_out[243]
  PIN rw0_rd_out[244]
    DIRECTION OUTPUT ;
    USE SIGNAL ;
    SHAPE ABUTMENT ;
    PORT
      LAYER metal2 ;
      RECT 96.105 0.000 96.175 0.210 ;
    END
  END rw0_rd_out[244]
  PIN rw0_rd_out[245]
    DIRECTION OUTPUT ;
    USE SIGNAL ;
    SHAPE ABUTMENT ;
    PORT
      LAYER metal2 ;
      RECT 96.295 0.000 96.365 0.210 ;
    END
  END rw0_rd_out[245]
  PIN rw0_rd_out[246]
    DIRECTION OUTPUT ;
    USE SIGNAL ;
    SHAPE ABUTMENT ;
    PORT
      LAYER metal2 ;
      RECT 96.485 0.000 96.555 0.210 ;
    END
  END rw0_rd_out[246]
  PIN rw0_rd_out[247]
    DIRECTION OUTPUT ;
    USE SIGNAL ;
    SHAPE ABUTMENT ;
    PORT
      LAYER metal2 ;
      RECT 96.675 0.000 96.745 0.210 ;
    END
  END rw0_rd_out[247]
  PIN rw0_rd_out[248]
    DIRECTION OUTPUT ;
    USE SIGNAL ;
    SHAPE ABUTMENT ;
    PORT
      LAYER metal2 ;
      RECT 96.865 0.000 96.935 0.210 ;
    END
  END rw0_rd_out[248]
  PIN rw0_rd_out[249]
    DIRECTION OUTPUT ;
    USE SIGNAL ;
    SHAPE ABUTMENT ;
    PORT
      LAYER metal2 ;
      RECT 97.055 0.000 97.125 0.210 ;
    END
  END rw0_rd_out[249]
  PIN rw0_rd_out[250]
    DIRECTION OUTPUT ;
    USE SIGNAL ;
    SHAPE ABUTMENT ;
    PORT
      LAYER metal2 ;
      RECT 97.245 0.000 97.315 0.210 ;
    END
  END rw0_rd_out[250]
  PIN rw0_rd_out[251]
    DIRECTION OUTPUT ;
    USE SIGNAL ;
    SHAPE ABUTMENT ;
    PORT
      LAYER metal2 ;
      RECT 97.435 0.000 97.505 0.210 ;
    END
  END rw0_rd_out[251]
  PIN rw0_rd_out[252]
    DIRECTION OUTPUT ;
    USE SIGNAL ;
    SHAPE ABUTMENT ;
    PORT
      LAYER metal2 ;
      RECT 97.625 0.000 97.695 0.210 ;
    END
  END rw0_rd_out[252]
  PIN rw0_rd_out[253]
    DIRECTION OUTPUT ;
    USE SIGNAL ;
    SHAPE ABUTMENT ;
    PORT
      LAYER metal2 ;
      RECT 97.815 0.000 97.885 0.210 ;
    END
  END rw0_rd_out[253]
  PIN rw0_rd_out[254]
    DIRECTION OUTPUT ;
    USE SIGNAL ;
    SHAPE ABUTMENT ;
    PORT
      LAYER metal2 ;
      RECT 98.005 0.000 98.075 0.210 ;
    END
  END rw0_rd_out[254]
  PIN rw0_rd_out[255]
    DIRECTION OUTPUT ;
    USE SIGNAL ;
    SHAPE ABUTMENT ;
    PORT
      LAYER metal2 ;
      RECT 98.195 0.000 98.265 0.210 ;
    END
  END rw0_rd_out[255]
  PIN rw0_rd_out[256]
    DIRECTION OUTPUT ;
    USE SIGNAL ;
    SHAPE ABUTMENT ;
    PORT
      LAYER metal2 ;
      RECT 1.105 332.990 1.175 333.200 ;
    END
  END rw0_rd_out[256]
  PIN rw0_rd_out[257]
    DIRECTION OUTPUT ;
    USE SIGNAL ;
    SHAPE ABUTMENT ;
    PORT
      LAYER metal2 ;
      RECT 1.675 332.990 1.745 333.200 ;
    END
  END rw0_rd_out[257]
  PIN rw0_rd_out[258]
    DIRECTION OUTPUT ;
    USE SIGNAL ;
    SHAPE ABUTMENT ;
    PORT
      LAYER metal2 ;
      RECT 2.245 332.990 2.315 333.200 ;
    END
  END rw0_rd_out[258]
  PIN rw0_rd_out[259]
    DIRECTION OUTPUT ;
    USE SIGNAL ;
    SHAPE ABUTMENT ;
    PORT
      LAYER metal2 ;
      RECT 2.815 332.990 2.885 333.200 ;
    END
  END rw0_rd_out[259]
  PIN rw0_rd_out[260]
    DIRECTION OUTPUT ;
    USE SIGNAL ;
    SHAPE ABUTMENT ;
    PORT
      LAYER metal2 ;
      RECT 3.385 332.990 3.455 333.200 ;
    END
  END rw0_rd_out[260]
  PIN rw0_rd_out[261]
    DIRECTION OUTPUT ;
    USE SIGNAL ;
    SHAPE ABUTMENT ;
    PORT
      LAYER metal2 ;
      RECT 3.955 332.990 4.025 333.200 ;
    END
  END rw0_rd_out[261]
  PIN rw0_rd_out[262]
    DIRECTION OUTPUT ;
    USE SIGNAL ;
    SHAPE ABUTMENT ;
    PORT
      LAYER metal2 ;
      RECT 4.525 332.990 4.595 333.200 ;
    END
  END rw0_rd_out[262]
  PIN rw0_rd_out[263]
    DIRECTION OUTPUT ;
    USE SIGNAL ;
    SHAPE ABUTMENT ;
    PORT
      LAYER metal2 ;
      RECT 5.095 332.990 5.165 333.200 ;
    END
  END rw0_rd_out[263]
  PIN rw0_rd_out[264]
    DIRECTION OUTPUT ;
    USE SIGNAL ;
    SHAPE ABUTMENT ;
    PORT
      LAYER metal2 ;
      RECT 5.665 332.990 5.735 333.200 ;
    END
  END rw0_rd_out[264]
  PIN rw0_rd_out[265]
    DIRECTION OUTPUT ;
    USE SIGNAL ;
    SHAPE ABUTMENT ;
    PORT
      LAYER metal2 ;
      RECT 6.235 332.990 6.305 333.200 ;
    END
  END rw0_rd_out[265]
  PIN rw0_rd_out[266]
    DIRECTION OUTPUT ;
    USE SIGNAL ;
    SHAPE ABUTMENT ;
    PORT
      LAYER metal2 ;
      RECT 6.805 332.990 6.875 333.200 ;
    END
  END rw0_rd_out[266]
  PIN rw0_rd_out[267]
    DIRECTION OUTPUT ;
    USE SIGNAL ;
    SHAPE ABUTMENT ;
    PORT
      LAYER metal2 ;
      RECT 7.375 332.990 7.445 333.200 ;
    END
  END rw0_rd_out[267]
  PIN rw0_rd_out[268]
    DIRECTION OUTPUT ;
    USE SIGNAL ;
    SHAPE ABUTMENT ;
    PORT
      LAYER metal2 ;
      RECT 7.945 332.990 8.015 333.200 ;
    END
  END rw0_rd_out[268]
  PIN rw0_rd_out[269]
    DIRECTION OUTPUT ;
    USE SIGNAL ;
    SHAPE ABUTMENT ;
    PORT
      LAYER metal2 ;
      RECT 8.515 332.990 8.585 333.200 ;
    END
  END rw0_rd_out[269]
  PIN rw0_rd_out[270]
    DIRECTION OUTPUT ;
    USE SIGNAL ;
    SHAPE ABUTMENT ;
    PORT
      LAYER metal2 ;
      RECT 9.085 332.990 9.155 333.200 ;
    END
  END rw0_rd_out[270]
  PIN rw0_rd_out[271]
    DIRECTION OUTPUT ;
    USE SIGNAL ;
    SHAPE ABUTMENT ;
    PORT
      LAYER metal2 ;
      RECT 9.655 332.990 9.725 333.200 ;
    END
  END rw0_rd_out[271]
  PIN rw0_rd_out[272]
    DIRECTION OUTPUT ;
    USE SIGNAL ;
    SHAPE ABUTMENT ;
    PORT
      LAYER metal2 ;
      RECT 10.225 332.990 10.295 333.200 ;
    END
  END rw0_rd_out[272]
  PIN rw0_rd_out[273]
    DIRECTION OUTPUT ;
    USE SIGNAL ;
    SHAPE ABUTMENT ;
    PORT
      LAYER metal2 ;
      RECT 10.795 332.990 10.865 333.200 ;
    END
  END rw0_rd_out[273]
  PIN rw0_rd_out[274]
    DIRECTION OUTPUT ;
    USE SIGNAL ;
    SHAPE ABUTMENT ;
    PORT
      LAYER metal2 ;
      RECT 11.365 332.990 11.435 333.200 ;
    END
  END rw0_rd_out[274]
  PIN rw0_rd_out[275]
    DIRECTION OUTPUT ;
    USE SIGNAL ;
    SHAPE ABUTMENT ;
    PORT
      LAYER metal2 ;
      RECT 11.935 332.990 12.005 333.200 ;
    END
  END rw0_rd_out[275]
  PIN rw0_rd_out[276]
    DIRECTION OUTPUT ;
    USE SIGNAL ;
    SHAPE ABUTMENT ;
    PORT
      LAYER metal2 ;
      RECT 12.505 332.990 12.575 333.200 ;
    END
  END rw0_rd_out[276]
  PIN rw0_rd_out[277]
    DIRECTION OUTPUT ;
    USE SIGNAL ;
    SHAPE ABUTMENT ;
    PORT
      LAYER metal2 ;
      RECT 13.075 332.990 13.145 333.200 ;
    END
  END rw0_rd_out[277]
  PIN rw0_rd_out[278]
    DIRECTION OUTPUT ;
    USE SIGNAL ;
    SHAPE ABUTMENT ;
    PORT
      LAYER metal2 ;
      RECT 13.645 332.990 13.715 333.200 ;
    END
  END rw0_rd_out[278]
  PIN rw0_rd_out[279]
    DIRECTION OUTPUT ;
    USE SIGNAL ;
    SHAPE ABUTMENT ;
    PORT
      LAYER metal2 ;
      RECT 14.215 332.990 14.285 333.200 ;
    END
  END rw0_rd_out[279]
  PIN rw0_rd_out[280]
    DIRECTION OUTPUT ;
    USE SIGNAL ;
    SHAPE ABUTMENT ;
    PORT
      LAYER metal2 ;
      RECT 14.785 332.990 14.855 333.200 ;
    END
  END rw0_rd_out[280]
  PIN rw0_rd_out[281]
    DIRECTION OUTPUT ;
    USE SIGNAL ;
    SHAPE ABUTMENT ;
    PORT
      LAYER metal2 ;
      RECT 15.355 332.990 15.425 333.200 ;
    END
  END rw0_rd_out[281]
  PIN rw0_rd_out[282]
    DIRECTION OUTPUT ;
    USE SIGNAL ;
    SHAPE ABUTMENT ;
    PORT
      LAYER metal2 ;
      RECT 15.925 332.990 15.995 333.200 ;
    END
  END rw0_rd_out[282]
  PIN rw0_rd_out[283]
    DIRECTION OUTPUT ;
    USE SIGNAL ;
    SHAPE ABUTMENT ;
    PORT
      LAYER metal2 ;
      RECT 16.495 332.990 16.565 333.200 ;
    END
  END rw0_rd_out[283]
  PIN rw0_rd_out[284]
    DIRECTION OUTPUT ;
    USE SIGNAL ;
    SHAPE ABUTMENT ;
    PORT
      LAYER metal2 ;
      RECT 17.065 332.990 17.135 333.200 ;
    END
  END rw0_rd_out[284]
  PIN rw0_rd_out[285]
    DIRECTION OUTPUT ;
    USE SIGNAL ;
    SHAPE ABUTMENT ;
    PORT
      LAYER metal2 ;
      RECT 17.635 332.990 17.705 333.200 ;
    END
  END rw0_rd_out[285]
  PIN rw0_rd_out[286]
    DIRECTION OUTPUT ;
    USE SIGNAL ;
    SHAPE ABUTMENT ;
    PORT
      LAYER metal2 ;
      RECT 18.205 332.990 18.275 333.200 ;
    END
  END rw0_rd_out[286]
  PIN rw0_rd_out[287]
    DIRECTION OUTPUT ;
    USE SIGNAL ;
    SHAPE ABUTMENT ;
    PORT
      LAYER metal2 ;
      RECT 18.775 332.990 18.845 333.200 ;
    END
  END rw0_rd_out[287]
  PIN rw0_rd_out[288]
    DIRECTION OUTPUT ;
    USE SIGNAL ;
    SHAPE ABUTMENT ;
    PORT
      LAYER metal2 ;
      RECT 19.345 332.990 19.415 333.200 ;
    END
  END rw0_rd_out[288]
  PIN rw0_rd_out[289]
    DIRECTION OUTPUT ;
    USE SIGNAL ;
    SHAPE ABUTMENT ;
    PORT
      LAYER metal2 ;
      RECT 19.915 332.990 19.985 333.200 ;
    END
  END rw0_rd_out[289]
  PIN rw0_rd_out[290]
    DIRECTION OUTPUT ;
    USE SIGNAL ;
    SHAPE ABUTMENT ;
    PORT
      LAYER metal2 ;
      RECT 20.485 332.990 20.555 333.200 ;
    END
  END rw0_rd_out[290]
  PIN rw0_rd_out[291]
    DIRECTION OUTPUT ;
    USE SIGNAL ;
    SHAPE ABUTMENT ;
    PORT
      LAYER metal2 ;
      RECT 21.055 332.990 21.125 333.200 ;
    END
  END rw0_rd_out[291]
  PIN rw0_rd_out[292]
    DIRECTION OUTPUT ;
    USE SIGNAL ;
    SHAPE ABUTMENT ;
    PORT
      LAYER metal2 ;
      RECT 21.625 332.990 21.695 333.200 ;
    END
  END rw0_rd_out[292]
  PIN rw0_rd_out[293]
    DIRECTION OUTPUT ;
    USE SIGNAL ;
    SHAPE ABUTMENT ;
    PORT
      LAYER metal2 ;
      RECT 22.195 332.990 22.265 333.200 ;
    END
  END rw0_rd_out[293]
  PIN rw0_rd_out[294]
    DIRECTION OUTPUT ;
    USE SIGNAL ;
    SHAPE ABUTMENT ;
    PORT
      LAYER metal2 ;
      RECT 22.765 332.990 22.835 333.200 ;
    END
  END rw0_rd_out[294]
  PIN rw0_rd_out[295]
    DIRECTION OUTPUT ;
    USE SIGNAL ;
    SHAPE ABUTMENT ;
    PORT
      LAYER metal2 ;
      RECT 23.335 332.990 23.405 333.200 ;
    END
  END rw0_rd_out[295]
  PIN rw0_rd_out[296]
    DIRECTION OUTPUT ;
    USE SIGNAL ;
    SHAPE ABUTMENT ;
    PORT
      LAYER metal2 ;
      RECT 23.905 332.990 23.975 333.200 ;
    END
  END rw0_rd_out[296]
  PIN rw0_rd_out[297]
    DIRECTION OUTPUT ;
    USE SIGNAL ;
    SHAPE ABUTMENT ;
    PORT
      LAYER metal2 ;
      RECT 24.475 332.990 24.545 333.200 ;
    END
  END rw0_rd_out[297]
  PIN rw0_rd_out[298]
    DIRECTION OUTPUT ;
    USE SIGNAL ;
    SHAPE ABUTMENT ;
    PORT
      LAYER metal2 ;
      RECT 25.045 332.990 25.115 333.200 ;
    END
  END rw0_rd_out[298]
  PIN rw0_rd_out[299]
    DIRECTION OUTPUT ;
    USE SIGNAL ;
    SHAPE ABUTMENT ;
    PORT
      LAYER metal2 ;
      RECT 25.615 332.990 25.685 333.200 ;
    END
  END rw0_rd_out[299]
  PIN rw0_rd_out[300]
    DIRECTION OUTPUT ;
    USE SIGNAL ;
    SHAPE ABUTMENT ;
    PORT
      LAYER metal2 ;
      RECT 26.185 332.990 26.255 333.200 ;
    END
  END rw0_rd_out[300]
  PIN rw0_rd_out[301]
    DIRECTION OUTPUT ;
    USE SIGNAL ;
    SHAPE ABUTMENT ;
    PORT
      LAYER metal2 ;
      RECT 26.755 332.990 26.825 333.200 ;
    END
  END rw0_rd_out[301]
  PIN rw0_rd_out[302]
    DIRECTION OUTPUT ;
    USE SIGNAL ;
    SHAPE ABUTMENT ;
    PORT
      LAYER metal2 ;
      RECT 27.325 332.990 27.395 333.200 ;
    END
  END rw0_rd_out[302]
  PIN rw0_rd_out[303]
    DIRECTION OUTPUT ;
    USE SIGNAL ;
    SHAPE ABUTMENT ;
    PORT
      LAYER metal2 ;
      RECT 27.895 332.990 27.965 333.200 ;
    END
  END rw0_rd_out[303]
  PIN rw0_rd_out[304]
    DIRECTION OUTPUT ;
    USE SIGNAL ;
    SHAPE ABUTMENT ;
    PORT
      LAYER metal2 ;
      RECT 28.465 332.990 28.535 333.200 ;
    END
  END rw0_rd_out[304]
  PIN rw0_rd_out[305]
    DIRECTION OUTPUT ;
    USE SIGNAL ;
    SHAPE ABUTMENT ;
    PORT
      LAYER metal2 ;
      RECT 29.035 332.990 29.105 333.200 ;
    END
  END rw0_rd_out[305]
  PIN rw0_rd_out[306]
    DIRECTION OUTPUT ;
    USE SIGNAL ;
    SHAPE ABUTMENT ;
    PORT
      LAYER metal2 ;
      RECT 29.605 332.990 29.675 333.200 ;
    END
  END rw0_rd_out[306]
  PIN rw0_rd_out[307]
    DIRECTION OUTPUT ;
    USE SIGNAL ;
    SHAPE ABUTMENT ;
    PORT
      LAYER metal2 ;
      RECT 30.175 332.990 30.245 333.200 ;
    END
  END rw0_rd_out[307]
  PIN rw0_rd_out[308]
    DIRECTION OUTPUT ;
    USE SIGNAL ;
    SHAPE ABUTMENT ;
    PORT
      LAYER metal2 ;
      RECT 30.745 332.990 30.815 333.200 ;
    END
  END rw0_rd_out[308]
  PIN rw0_rd_out[309]
    DIRECTION OUTPUT ;
    USE SIGNAL ;
    SHAPE ABUTMENT ;
    PORT
      LAYER metal2 ;
      RECT 31.315 332.990 31.385 333.200 ;
    END
  END rw0_rd_out[309]
  PIN rw0_rd_out[310]
    DIRECTION OUTPUT ;
    USE SIGNAL ;
    SHAPE ABUTMENT ;
    PORT
      LAYER metal2 ;
      RECT 31.885 332.990 31.955 333.200 ;
    END
  END rw0_rd_out[310]
  PIN rw0_rd_out[311]
    DIRECTION OUTPUT ;
    USE SIGNAL ;
    SHAPE ABUTMENT ;
    PORT
      LAYER metal2 ;
      RECT 32.455 332.990 32.525 333.200 ;
    END
  END rw0_rd_out[311]
  PIN rw0_rd_out[312]
    DIRECTION OUTPUT ;
    USE SIGNAL ;
    SHAPE ABUTMENT ;
    PORT
      LAYER metal2 ;
      RECT 33.025 332.990 33.095 333.200 ;
    END
  END rw0_rd_out[312]
  PIN rw0_rd_out[313]
    DIRECTION OUTPUT ;
    USE SIGNAL ;
    SHAPE ABUTMENT ;
    PORT
      LAYER metal2 ;
      RECT 33.595 332.990 33.665 333.200 ;
    END
  END rw0_rd_out[313]
  PIN rw0_rd_out[314]
    DIRECTION OUTPUT ;
    USE SIGNAL ;
    SHAPE ABUTMENT ;
    PORT
      LAYER metal2 ;
      RECT 34.165 332.990 34.235 333.200 ;
    END
  END rw0_rd_out[314]
  PIN rw0_rd_out[315]
    DIRECTION OUTPUT ;
    USE SIGNAL ;
    SHAPE ABUTMENT ;
    PORT
      LAYER metal2 ;
      RECT 34.735 332.990 34.805 333.200 ;
    END
  END rw0_rd_out[315]
  PIN rw0_rd_out[316]
    DIRECTION OUTPUT ;
    USE SIGNAL ;
    SHAPE ABUTMENT ;
    PORT
      LAYER metal2 ;
      RECT 35.305 332.990 35.375 333.200 ;
    END
  END rw0_rd_out[316]
  PIN rw0_rd_out[317]
    DIRECTION OUTPUT ;
    USE SIGNAL ;
    SHAPE ABUTMENT ;
    PORT
      LAYER metal2 ;
      RECT 35.875 332.990 35.945 333.200 ;
    END
  END rw0_rd_out[317]
  PIN rw0_rd_out[318]
    DIRECTION OUTPUT ;
    USE SIGNAL ;
    SHAPE ABUTMENT ;
    PORT
      LAYER metal2 ;
      RECT 36.445 332.990 36.515 333.200 ;
    END
  END rw0_rd_out[318]
  PIN rw0_rd_out[319]
    DIRECTION OUTPUT ;
    USE SIGNAL ;
    SHAPE ABUTMENT ;
    PORT
      LAYER metal2 ;
      RECT 37.015 332.990 37.085 333.200 ;
    END
  END rw0_rd_out[319]
  PIN rw0_rd_out[320]
    DIRECTION OUTPUT ;
    USE SIGNAL ;
    SHAPE ABUTMENT ;
    PORT
      LAYER metal2 ;
      RECT 37.585 332.990 37.655 333.200 ;
    END
  END rw0_rd_out[320]
  PIN rw0_rd_out[321]
    DIRECTION OUTPUT ;
    USE SIGNAL ;
    SHAPE ABUTMENT ;
    PORT
      LAYER metal2 ;
      RECT 38.155 332.990 38.225 333.200 ;
    END
  END rw0_rd_out[321]
  PIN rw0_rd_out[322]
    DIRECTION OUTPUT ;
    USE SIGNAL ;
    SHAPE ABUTMENT ;
    PORT
      LAYER metal2 ;
      RECT 38.725 332.990 38.795 333.200 ;
    END
  END rw0_rd_out[322]
  PIN rw0_rd_out[323]
    DIRECTION OUTPUT ;
    USE SIGNAL ;
    SHAPE ABUTMENT ;
    PORT
      LAYER metal2 ;
      RECT 39.295 332.990 39.365 333.200 ;
    END
  END rw0_rd_out[323]
  PIN rw0_rd_out[324]
    DIRECTION OUTPUT ;
    USE SIGNAL ;
    SHAPE ABUTMENT ;
    PORT
      LAYER metal2 ;
      RECT 39.865 332.990 39.935 333.200 ;
    END
  END rw0_rd_out[324]
  PIN rw0_rd_out[325]
    DIRECTION OUTPUT ;
    USE SIGNAL ;
    SHAPE ABUTMENT ;
    PORT
      LAYER metal2 ;
      RECT 40.435 332.990 40.505 333.200 ;
    END
  END rw0_rd_out[325]
  PIN rw0_rd_out[326]
    DIRECTION OUTPUT ;
    USE SIGNAL ;
    SHAPE ABUTMENT ;
    PORT
      LAYER metal2 ;
      RECT 41.005 332.990 41.075 333.200 ;
    END
  END rw0_rd_out[326]
  PIN rw0_rd_out[327]
    DIRECTION OUTPUT ;
    USE SIGNAL ;
    SHAPE ABUTMENT ;
    PORT
      LAYER metal2 ;
      RECT 41.575 332.990 41.645 333.200 ;
    END
  END rw0_rd_out[327]
  PIN rw0_rd_out[328]
    DIRECTION OUTPUT ;
    USE SIGNAL ;
    SHAPE ABUTMENT ;
    PORT
      LAYER metal2 ;
      RECT 42.145 332.990 42.215 333.200 ;
    END
  END rw0_rd_out[328]
  PIN rw0_rd_out[329]
    DIRECTION OUTPUT ;
    USE SIGNAL ;
    SHAPE ABUTMENT ;
    PORT
      LAYER metal2 ;
      RECT 42.715 332.990 42.785 333.200 ;
    END
  END rw0_rd_out[329]
  PIN rw0_rd_out[330]
    DIRECTION OUTPUT ;
    USE SIGNAL ;
    SHAPE ABUTMENT ;
    PORT
      LAYER metal2 ;
      RECT 43.285 332.990 43.355 333.200 ;
    END
  END rw0_rd_out[330]
  PIN rw0_rd_out[331]
    DIRECTION OUTPUT ;
    USE SIGNAL ;
    SHAPE ABUTMENT ;
    PORT
      LAYER metal2 ;
      RECT 43.855 332.990 43.925 333.200 ;
    END
  END rw0_rd_out[331]
  PIN rw0_rd_out[332]
    DIRECTION OUTPUT ;
    USE SIGNAL ;
    SHAPE ABUTMENT ;
    PORT
      LAYER metal2 ;
      RECT 44.425 332.990 44.495 333.200 ;
    END
  END rw0_rd_out[332]
  PIN rw0_rd_out[333]
    DIRECTION OUTPUT ;
    USE SIGNAL ;
    SHAPE ABUTMENT ;
    PORT
      LAYER metal2 ;
      RECT 44.995 332.990 45.065 333.200 ;
    END
  END rw0_rd_out[333]
  PIN rw0_rd_out[334]
    DIRECTION OUTPUT ;
    USE SIGNAL ;
    SHAPE ABUTMENT ;
    PORT
      LAYER metal2 ;
      RECT 45.565 332.990 45.635 333.200 ;
    END
  END rw0_rd_out[334]
  PIN rw0_rd_out[335]
    DIRECTION OUTPUT ;
    USE SIGNAL ;
    SHAPE ABUTMENT ;
    PORT
      LAYER metal2 ;
      RECT 46.135 332.990 46.205 333.200 ;
    END
  END rw0_rd_out[335]
  PIN rw0_rd_out[336]
    DIRECTION OUTPUT ;
    USE SIGNAL ;
    SHAPE ABUTMENT ;
    PORT
      LAYER metal2 ;
      RECT 46.705 332.990 46.775 333.200 ;
    END
  END rw0_rd_out[336]
  PIN rw0_rd_out[337]
    DIRECTION OUTPUT ;
    USE SIGNAL ;
    SHAPE ABUTMENT ;
    PORT
      LAYER metal2 ;
      RECT 47.275 332.990 47.345 333.200 ;
    END
  END rw0_rd_out[337]
  PIN rw0_rd_out[338]
    DIRECTION OUTPUT ;
    USE SIGNAL ;
    SHAPE ABUTMENT ;
    PORT
      LAYER metal2 ;
      RECT 47.845 332.990 47.915 333.200 ;
    END
  END rw0_rd_out[338]
  PIN rw0_rd_out[339]
    DIRECTION OUTPUT ;
    USE SIGNAL ;
    SHAPE ABUTMENT ;
    PORT
      LAYER metal2 ;
      RECT 48.415 332.990 48.485 333.200 ;
    END
  END rw0_rd_out[339]
  PIN rw0_rd_out[340]
    DIRECTION OUTPUT ;
    USE SIGNAL ;
    SHAPE ABUTMENT ;
    PORT
      LAYER metal2 ;
      RECT 48.985 332.990 49.055 333.200 ;
    END
  END rw0_rd_out[340]
  PIN rw0_rd_out[341]
    DIRECTION OUTPUT ;
    USE SIGNAL ;
    SHAPE ABUTMENT ;
    PORT
      LAYER metal2 ;
      RECT 49.555 332.990 49.625 333.200 ;
    END
  END rw0_rd_out[341]
  PIN rw0_rd_out[342]
    DIRECTION OUTPUT ;
    USE SIGNAL ;
    SHAPE ABUTMENT ;
    PORT
      LAYER metal2 ;
      RECT 50.125 332.990 50.195 333.200 ;
    END
  END rw0_rd_out[342]
  PIN rw0_rd_out[343]
    DIRECTION OUTPUT ;
    USE SIGNAL ;
    SHAPE ABUTMENT ;
    PORT
      LAYER metal2 ;
      RECT 50.695 332.990 50.765 333.200 ;
    END
  END rw0_rd_out[343]
  PIN rw0_rd_out[344]
    DIRECTION OUTPUT ;
    USE SIGNAL ;
    SHAPE ABUTMENT ;
    PORT
      LAYER metal2 ;
      RECT 51.265 332.990 51.335 333.200 ;
    END
  END rw0_rd_out[344]
  PIN rw0_rd_out[345]
    DIRECTION OUTPUT ;
    USE SIGNAL ;
    SHAPE ABUTMENT ;
    PORT
      LAYER metal2 ;
      RECT 51.835 332.990 51.905 333.200 ;
    END
  END rw0_rd_out[345]
  PIN rw0_rd_out[346]
    DIRECTION OUTPUT ;
    USE SIGNAL ;
    SHAPE ABUTMENT ;
    PORT
      LAYER metal2 ;
      RECT 52.405 332.990 52.475 333.200 ;
    END
  END rw0_rd_out[346]
  PIN rw0_rd_out[347]
    DIRECTION OUTPUT ;
    USE SIGNAL ;
    SHAPE ABUTMENT ;
    PORT
      LAYER metal2 ;
      RECT 52.975 332.990 53.045 333.200 ;
    END
  END rw0_rd_out[347]
  PIN rw0_rd_out[348]
    DIRECTION OUTPUT ;
    USE SIGNAL ;
    SHAPE ABUTMENT ;
    PORT
      LAYER metal2 ;
      RECT 53.545 332.990 53.615 333.200 ;
    END
  END rw0_rd_out[348]
  PIN rw0_rd_out[349]
    DIRECTION OUTPUT ;
    USE SIGNAL ;
    SHAPE ABUTMENT ;
    PORT
      LAYER metal2 ;
      RECT 54.115 332.990 54.185 333.200 ;
    END
  END rw0_rd_out[349]
  PIN rw0_rd_out[350]
    DIRECTION OUTPUT ;
    USE SIGNAL ;
    SHAPE ABUTMENT ;
    PORT
      LAYER metal2 ;
      RECT 54.685 332.990 54.755 333.200 ;
    END
  END rw0_rd_out[350]
  PIN rw0_rd_out[351]
    DIRECTION OUTPUT ;
    USE SIGNAL ;
    SHAPE ABUTMENT ;
    PORT
      LAYER metal2 ;
      RECT 55.255 332.990 55.325 333.200 ;
    END
  END rw0_rd_out[351]
  PIN rw0_rd_out[352]
    DIRECTION OUTPUT ;
    USE SIGNAL ;
    SHAPE ABUTMENT ;
    PORT
      LAYER metal2 ;
      RECT 55.825 332.990 55.895 333.200 ;
    END
  END rw0_rd_out[352]
  PIN rw0_rd_out[353]
    DIRECTION OUTPUT ;
    USE SIGNAL ;
    SHAPE ABUTMENT ;
    PORT
      LAYER metal2 ;
      RECT 56.395 332.990 56.465 333.200 ;
    END
  END rw0_rd_out[353]
  PIN rw0_rd_out[354]
    DIRECTION OUTPUT ;
    USE SIGNAL ;
    SHAPE ABUTMENT ;
    PORT
      LAYER metal2 ;
      RECT 56.965 332.990 57.035 333.200 ;
    END
  END rw0_rd_out[354]
  PIN rw0_rd_out[355]
    DIRECTION OUTPUT ;
    USE SIGNAL ;
    SHAPE ABUTMENT ;
    PORT
      LAYER metal2 ;
      RECT 57.535 332.990 57.605 333.200 ;
    END
  END rw0_rd_out[355]
  PIN rw0_rd_out[356]
    DIRECTION OUTPUT ;
    USE SIGNAL ;
    SHAPE ABUTMENT ;
    PORT
      LAYER metal2 ;
      RECT 58.105 332.990 58.175 333.200 ;
    END
  END rw0_rd_out[356]
  PIN rw0_rd_out[357]
    DIRECTION OUTPUT ;
    USE SIGNAL ;
    SHAPE ABUTMENT ;
    PORT
      LAYER metal2 ;
      RECT 58.675 332.990 58.745 333.200 ;
    END
  END rw0_rd_out[357]
  PIN rw0_rd_out[358]
    DIRECTION OUTPUT ;
    USE SIGNAL ;
    SHAPE ABUTMENT ;
    PORT
      LAYER metal2 ;
      RECT 59.245 332.990 59.315 333.200 ;
    END
  END rw0_rd_out[358]
  PIN rw0_rd_out[359]
    DIRECTION OUTPUT ;
    USE SIGNAL ;
    SHAPE ABUTMENT ;
    PORT
      LAYER metal2 ;
      RECT 59.815 332.990 59.885 333.200 ;
    END
  END rw0_rd_out[359]
  PIN rw0_rd_out[360]
    DIRECTION OUTPUT ;
    USE SIGNAL ;
    SHAPE ABUTMENT ;
    PORT
      LAYER metal2 ;
      RECT 60.385 332.990 60.455 333.200 ;
    END
  END rw0_rd_out[360]
  PIN rw0_rd_out[361]
    DIRECTION OUTPUT ;
    USE SIGNAL ;
    SHAPE ABUTMENT ;
    PORT
      LAYER metal2 ;
      RECT 60.955 332.990 61.025 333.200 ;
    END
  END rw0_rd_out[361]
  PIN rw0_rd_out[362]
    DIRECTION OUTPUT ;
    USE SIGNAL ;
    SHAPE ABUTMENT ;
    PORT
      LAYER metal2 ;
      RECT 61.525 332.990 61.595 333.200 ;
    END
  END rw0_rd_out[362]
  PIN rw0_rd_out[363]
    DIRECTION OUTPUT ;
    USE SIGNAL ;
    SHAPE ABUTMENT ;
    PORT
      LAYER metal2 ;
      RECT 62.095 332.990 62.165 333.200 ;
    END
  END rw0_rd_out[363]
  PIN rw0_rd_out[364]
    DIRECTION OUTPUT ;
    USE SIGNAL ;
    SHAPE ABUTMENT ;
    PORT
      LAYER metal2 ;
      RECT 62.665 332.990 62.735 333.200 ;
    END
  END rw0_rd_out[364]
  PIN rw0_rd_out[365]
    DIRECTION OUTPUT ;
    USE SIGNAL ;
    SHAPE ABUTMENT ;
    PORT
      LAYER metal2 ;
      RECT 63.235 332.990 63.305 333.200 ;
    END
  END rw0_rd_out[365]
  PIN rw0_rd_out[366]
    DIRECTION OUTPUT ;
    USE SIGNAL ;
    SHAPE ABUTMENT ;
    PORT
      LAYER metal2 ;
      RECT 63.805 332.990 63.875 333.200 ;
    END
  END rw0_rd_out[366]
  PIN rw0_rd_out[367]
    DIRECTION OUTPUT ;
    USE SIGNAL ;
    SHAPE ABUTMENT ;
    PORT
      LAYER metal2 ;
      RECT 64.375 332.990 64.445 333.200 ;
    END
  END rw0_rd_out[367]
  PIN rw0_rd_out[368]
    DIRECTION OUTPUT ;
    USE SIGNAL ;
    SHAPE ABUTMENT ;
    PORT
      LAYER metal2 ;
      RECT 64.945 332.990 65.015 333.200 ;
    END
  END rw0_rd_out[368]
  PIN rw0_rd_out[369]
    DIRECTION OUTPUT ;
    USE SIGNAL ;
    SHAPE ABUTMENT ;
    PORT
      LAYER metal2 ;
      RECT 65.515 332.990 65.585 333.200 ;
    END
  END rw0_rd_out[369]
  PIN rw0_rd_out[370]
    DIRECTION OUTPUT ;
    USE SIGNAL ;
    SHAPE ABUTMENT ;
    PORT
      LAYER metal2 ;
      RECT 66.085 332.990 66.155 333.200 ;
    END
  END rw0_rd_out[370]
  PIN rw0_rd_out[371]
    DIRECTION OUTPUT ;
    USE SIGNAL ;
    SHAPE ABUTMENT ;
    PORT
      LAYER metal2 ;
      RECT 66.655 332.990 66.725 333.200 ;
    END
  END rw0_rd_out[371]
  PIN rw0_rd_out[372]
    DIRECTION OUTPUT ;
    USE SIGNAL ;
    SHAPE ABUTMENT ;
    PORT
      LAYER metal2 ;
      RECT 67.225 332.990 67.295 333.200 ;
    END
  END rw0_rd_out[372]
  PIN rw0_rd_out[373]
    DIRECTION OUTPUT ;
    USE SIGNAL ;
    SHAPE ABUTMENT ;
    PORT
      LAYER metal2 ;
      RECT 67.795 332.990 67.865 333.200 ;
    END
  END rw0_rd_out[373]
  PIN rw0_rd_out[374]
    DIRECTION OUTPUT ;
    USE SIGNAL ;
    SHAPE ABUTMENT ;
    PORT
      LAYER metal2 ;
      RECT 68.365 332.990 68.435 333.200 ;
    END
  END rw0_rd_out[374]
  PIN rw0_rd_out[375]
    DIRECTION OUTPUT ;
    USE SIGNAL ;
    SHAPE ABUTMENT ;
    PORT
      LAYER metal2 ;
      RECT 68.935 332.990 69.005 333.200 ;
    END
  END rw0_rd_out[375]
  PIN rw0_rd_out[376]
    DIRECTION OUTPUT ;
    USE SIGNAL ;
    SHAPE ABUTMENT ;
    PORT
      LAYER metal2 ;
      RECT 69.505 332.990 69.575 333.200 ;
    END
  END rw0_rd_out[376]
  PIN rw0_rd_out[377]
    DIRECTION OUTPUT ;
    USE SIGNAL ;
    SHAPE ABUTMENT ;
    PORT
      LAYER metal2 ;
      RECT 70.075 332.990 70.145 333.200 ;
    END
  END rw0_rd_out[377]
  PIN rw0_rd_out[378]
    DIRECTION OUTPUT ;
    USE SIGNAL ;
    SHAPE ABUTMENT ;
    PORT
      LAYER metal2 ;
      RECT 70.645 332.990 70.715 333.200 ;
    END
  END rw0_rd_out[378]
  PIN rw0_rd_out[379]
    DIRECTION OUTPUT ;
    USE SIGNAL ;
    SHAPE ABUTMENT ;
    PORT
      LAYER metal2 ;
      RECT 71.215 332.990 71.285 333.200 ;
    END
  END rw0_rd_out[379]
  PIN rw0_rd_out[380]
    DIRECTION OUTPUT ;
    USE SIGNAL ;
    SHAPE ABUTMENT ;
    PORT
      LAYER metal2 ;
      RECT 71.785 332.990 71.855 333.200 ;
    END
  END rw0_rd_out[380]
  PIN rw0_rd_out[381]
    DIRECTION OUTPUT ;
    USE SIGNAL ;
    SHAPE ABUTMENT ;
    PORT
      LAYER metal2 ;
      RECT 72.355 332.990 72.425 333.200 ;
    END
  END rw0_rd_out[381]
  PIN rw0_rd_out[382]
    DIRECTION OUTPUT ;
    USE SIGNAL ;
    SHAPE ABUTMENT ;
    PORT
      LAYER metal2 ;
      RECT 72.925 332.990 72.995 333.200 ;
    END
  END rw0_rd_out[382]
  PIN rw0_rd_out[383]
    DIRECTION OUTPUT ;
    USE SIGNAL ;
    SHAPE ABUTMENT ;
    PORT
      LAYER metal2 ;
      RECT 73.495 332.990 73.565 333.200 ;
    END
  END rw0_rd_out[383]
  PIN rw0_rd_out[384]
    DIRECTION OUTPUT ;
    USE SIGNAL ;
    SHAPE ABUTMENT ;
    PORT
      LAYER metal2 ;
      RECT 74.065 332.990 74.135 333.200 ;
    END
  END rw0_rd_out[384]
  PIN rw0_rd_out[385]
    DIRECTION OUTPUT ;
    USE SIGNAL ;
    SHAPE ABUTMENT ;
    PORT
      LAYER metal2 ;
      RECT 74.635 332.990 74.705 333.200 ;
    END
  END rw0_rd_out[385]
  PIN rw0_rd_out[386]
    DIRECTION OUTPUT ;
    USE SIGNAL ;
    SHAPE ABUTMENT ;
    PORT
      LAYER metal2 ;
      RECT 75.205 332.990 75.275 333.200 ;
    END
  END rw0_rd_out[386]
  PIN rw0_rd_out[387]
    DIRECTION OUTPUT ;
    USE SIGNAL ;
    SHAPE ABUTMENT ;
    PORT
      LAYER metal2 ;
      RECT 75.775 332.990 75.845 333.200 ;
    END
  END rw0_rd_out[387]
  PIN rw0_rd_out[388]
    DIRECTION OUTPUT ;
    USE SIGNAL ;
    SHAPE ABUTMENT ;
    PORT
      LAYER metal2 ;
      RECT 76.345 332.990 76.415 333.200 ;
    END
  END rw0_rd_out[388]
  PIN rw0_rd_out[389]
    DIRECTION OUTPUT ;
    USE SIGNAL ;
    SHAPE ABUTMENT ;
    PORT
      LAYER metal2 ;
      RECT 76.915 332.990 76.985 333.200 ;
    END
  END rw0_rd_out[389]
  PIN rw0_rd_out[390]
    DIRECTION OUTPUT ;
    USE SIGNAL ;
    SHAPE ABUTMENT ;
    PORT
      LAYER metal2 ;
      RECT 77.485 332.990 77.555 333.200 ;
    END
  END rw0_rd_out[390]
  PIN rw0_rd_out[391]
    DIRECTION OUTPUT ;
    USE SIGNAL ;
    SHAPE ABUTMENT ;
    PORT
      LAYER metal2 ;
      RECT 78.055 332.990 78.125 333.200 ;
    END
  END rw0_rd_out[391]
  PIN rw0_rd_out[392]
    DIRECTION OUTPUT ;
    USE SIGNAL ;
    SHAPE ABUTMENT ;
    PORT
      LAYER metal2 ;
      RECT 78.625 332.990 78.695 333.200 ;
    END
  END rw0_rd_out[392]
  PIN rw0_rd_out[393]
    DIRECTION OUTPUT ;
    USE SIGNAL ;
    SHAPE ABUTMENT ;
    PORT
      LAYER metal2 ;
      RECT 79.195 332.990 79.265 333.200 ;
    END
  END rw0_rd_out[393]
  PIN rw0_rd_out[394]
    DIRECTION OUTPUT ;
    USE SIGNAL ;
    SHAPE ABUTMENT ;
    PORT
      LAYER metal2 ;
      RECT 79.765 332.990 79.835 333.200 ;
    END
  END rw0_rd_out[394]
  PIN rw0_rd_out[395]
    DIRECTION OUTPUT ;
    USE SIGNAL ;
    SHAPE ABUTMENT ;
    PORT
      LAYER metal2 ;
      RECT 80.335 332.990 80.405 333.200 ;
    END
  END rw0_rd_out[395]
  PIN rw0_rd_out[396]
    DIRECTION OUTPUT ;
    USE SIGNAL ;
    SHAPE ABUTMENT ;
    PORT
      LAYER metal2 ;
      RECT 80.905 332.990 80.975 333.200 ;
    END
  END rw0_rd_out[396]
  PIN rw0_rd_out[397]
    DIRECTION OUTPUT ;
    USE SIGNAL ;
    SHAPE ABUTMENT ;
    PORT
      LAYER metal2 ;
      RECT 81.475 332.990 81.545 333.200 ;
    END
  END rw0_rd_out[397]
  PIN rw0_rd_out[398]
    DIRECTION OUTPUT ;
    USE SIGNAL ;
    SHAPE ABUTMENT ;
    PORT
      LAYER metal2 ;
      RECT 82.045 332.990 82.115 333.200 ;
    END
  END rw0_rd_out[398]
  PIN rw0_rd_out[399]
    DIRECTION OUTPUT ;
    USE SIGNAL ;
    SHAPE ABUTMENT ;
    PORT
      LAYER metal2 ;
      RECT 82.615 332.990 82.685 333.200 ;
    END
  END rw0_rd_out[399]
  PIN rw0_rd_out[400]
    DIRECTION OUTPUT ;
    USE SIGNAL ;
    SHAPE ABUTMENT ;
    PORT
      LAYER metal2 ;
      RECT 83.185 332.990 83.255 333.200 ;
    END
  END rw0_rd_out[400]
  PIN rw0_rd_out[401]
    DIRECTION OUTPUT ;
    USE SIGNAL ;
    SHAPE ABUTMENT ;
    PORT
      LAYER metal2 ;
      RECT 83.755 332.990 83.825 333.200 ;
    END
  END rw0_rd_out[401]
  PIN rw0_rd_out[402]
    DIRECTION OUTPUT ;
    USE SIGNAL ;
    SHAPE ABUTMENT ;
    PORT
      LAYER metal2 ;
      RECT 84.325 332.990 84.395 333.200 ;
    END
  END rw0_rd_out[402]
  PIN rw0_rd_out[403]
    DIRECTION OUTPUT ;
    USE SIGNAL ;
    SHAPE ABUTMENT ;
    PORT
      LAYER metal2 ;
      RECT 84.895 332.990 84.965 333.200 ;
    END
  END rw0_rd_out[403]
  PIN rw0_rd_out[404]
    DIRECTION OUTPUT ;
    USE SIGNAL ;
    SHAPE ABUTMENT ;
    PORT
      LAYER metal2 ;
      RECT 85.465 332.990 85.535 333.200 ;
    END
  END rw0_rd_out[404]
  PIN rw0_rd_out[405]
    DIRECTION OUTPUT ;
    USE SIGNAL ;
    SHAPE ABUTMENT ;
    PORT
      LAYER metal2 ;
      RECT 86.035 332.990 86.105 333.200 ;
    END
  END rw0_rd_out[405]
  PIN rw0_rd_out[406]
    DIRECTION OUTPUT ;
    USE SIGNAL ;
    SHAPE ABUTMENT ;
    PORT
      LAYER metal2 ;
      RECT 86.605 332.990 86.675 333.200 ;
    END
  END rw0_rd_out[406]
  PIN rw0_rd_out[407]
    DIRECTION OUTPUT ;
    USE SIGNAL ;
    SHAPE ABUTMENT ;
    PORT
      LAYER metal2 ;
      RECT 87.175 332.990 87.245 333.200 ;
    END
  END rw0_rd_out[407]
  PIN rw0_rd_out[408]
    DIRECTION OUTPUT ;
    USE SIGNAL ;
    SHAPE ABUTMENT ;
    PORT
      LAYER metal2 ;
      RECT 87.745 332.990 87.815 333.200 ;
    END
  END rw0_rd_out[408]
  PIN rw0_rd_out[409]
    DIRECTION OUTPUT ;
    USE SIGNAL ;
    SHAPE ABUTMENT ;
    PORT
      LAYER metal2 ;
      RECT 88.315 332.990 88.385 333.200 ;
    END
  END rw0_rd_out[409]
  PIN rw0_rd_out[410]
    DIRECTION OUTPUT ;
    USE SIGNAL ;
    SHAPE ABUTMENT ;
    PORT
      LAYER metal2 ;
      RECT 88.885 332.990 88.955 333.200 ;
    END
  END rw0_rd_out[410]
  PIN rw0_rd_out[411]
    DIRECTION OUTPUT ;
    USE SIGNAL ;
    SHAPE ABUTMENT ;
    PORT
      LAYER metal2 ;
      RECT 89.455 332.990 89.525 333.200 ;
    END
  END rw0_rd_out[411]
  PIN rw0_rd_out[412]
    DIRECTION OUTPUT ;
    USE SIGNAL ;
    SHAPE ABUTMENT ;
    PORT
      LAYER metal2 ;
      RECT 90.025 332.990 90.095 333.200 ;
    END
  END rw0_rd_out[412]
  PIN rw0_rd_out[413]
    DIRECTION OUTPUT ;
    USE SIGNAL ;
    SHAPE ABUTMENT ;
    PORT
      LAYER metal2 ;
      RECT 90.595 332.990 90.665 333.200 ;
    END
  END rw0_rd_out[413]
  PIN rw0_rd_out[414]
    DIRECTION OUTPUT ;
    USE SIGNAL ;
    SHAPE ABUTMENT ;
    PORT
      LAYER metal2 ;
      RECT 91.165 332.990 91.235 333.200 ;
    END
  END rw0_rd_out[414]
  PIN rw0_rd_out[415]
    DIRECTION OUTPUT ;
    USE SIGNAL ;
    SHAPE ABUTMENT ;
    PORT
      LAYER metal2 ;
      RECT 91.735 332.990 91.805 333.200 ;
    END
  END rw0_rd_out[415]
  PIN rw0_rd_out[416]
    DIRECTION OUTPUT ;
    USE SIGNAL ;
    SHAPE ABUTMENT ;
    PORT
      LAYER metal2 ;
      RECT 92.305 332.990 92.375 333.200 ;
    END
  END rw0_rd_out[416]
  PIN rw0_rd_out[417]
    DIRECTION OUTPUT ;
    USE SIGNAL ;
    SHAPE ABUTMENT ;
    PORT
      LAYER metal2 ;
      RECT 92.875 332.990 92.945 333.200 ;
    END
  END rw0_rd_out[417]
  PIN rw0_rd_out[418]
    DIRECTION OUTPUT ;
    USE SIGNAL ;
    SHAPE ABUTMENT ;
    PORT
      LAYER metal2 ;
      RECT 93.445 332.990 93.515 333.200 ;
    END
  END rw0_rd_out[418]
  PIN rw0_rd_out[419]
    DIRECTION OUTPUT ;
    USE SIGNAL ;
    SHAPE ABUTMENT ;
    PORT
      LAYER metal2 ;
      RECT 94.015 332.990 94.085 333.200 ;
    END
  END rw0_rd_out[419]
  PIN rw0_rd_out[420]
    DIRECTION OUTPUT ;
    USE SIGNAL ;
    SHAPE ABUTMENT ;
    PORT
      LAYER metal2 ;
      RECT 94.585 332.990 94.655 333.200 ;
    END
  END rw0_rd_out[420]
  PIN rw0_rd_out[421]
    DIRECTION OUTPUT ;
    USE SIGNAL ;
    SHAPE ABUTMENT ;
    PORT
      LAYER metal2 ;
      RECT 95.155 332.990 95.225 333.200 ;
    END
  END rw0_rd_out[421]
  PIN rw0_rd_out[422]
    DIRECTION OUTPUT ;
    USE SIGNAL ;
    SHAPE ABUTMENT ;
    PORT
      LAYER metal2 ;
      RECT 95.725 332.990 95.795 333.200 ;
    END
  END rw0_rd_out[422]
  PIN rw0_rd_out[423]
    DIRECTION OUTPUT ;
    USE SIGNAL ;
    SHAPE ABUTMENT ;
    PORT
      LAYER metal2 ;
      RECT 96.295 332.990 96.365 333.200 ;
    END
  END rw0_rd_out[423]
  PIN rw0_rd_out[424]
    DIRECTION OUTPUT ;
    USE SIGNAL ;
    SHAPE ABUTMENT ;
    PORT
      LAYER metal2 ;
      RECT 96.865 332.990 96.935 333.200 ;
    END
  END rw0_rd_out[424]
  PIN rw0_rd_out[425]
    DIRECTION OUTPUT ;
    USE SIGNAL ;
    SHAPE ABUTMENT ;
    PORT
      LAYER metal2 ;
      RECT 97.435 332.990 97.505 333.200 ;
    END
  END rw0_rd_out[425]
  PIN rw0_rd_out[426]
    DIRECTION OUTPUT ;
    USE SIGNAL ;
    SHAPE ABUTMENT ;
    PORT
      LAYER metal2 ;
      RECT 98.005 332.990 98.075 333.200 ;
    END
  END rw0_rd_out[426]
  PIN rw0_rd_out[427]
    DIRECTION OUTPUT ;
    USE SIGNAL ;
    SHAPE ABUTMENT ;
    PORT
      LAYER metal2 ;
      RECT 98.575 332.990 98.645 333.200 ;
    END
  END rw0_rd_out[427]
  PIN rw0_rd_out[428]
    DIRECTION OUTPUT ;
    USE SIGNAL ;
    SHAPE ABUTMENT ;
    PORT
      LAYER metal2 ;
      RECT 99.145 332.990 99.215 333.200 ;
    END
  END rw0_rd_out[428]
  PIN rw0_rd_out[429]
    DIRECTION OUTPUT ;
    USE SIGNAL ;
    SHAPE ABUTMENT ;
    PORT
      LAYER metal2 ;
      RECT 99.715 332.990 99.785 333.200 ;
    END
  END rw0_rd_out[429]
  PIN rw0_rd_out[430]
    DIRECTION OUTPUT ;
    USE SIGNAL ;
    SHAPE ABUTMENT ;
    PORT
      LAYER metal2 ;
      RECT 100.285 332.990 100.355 333.200 ;
    END
  END rw0_rd_out[430]
  PIN rw0_rd_out[431]
    DIRECTION OUTPUT ;
    USE SIGNAL ;
    SHAPE ABUTMENT ;
    PORT
      LAYER metal2 ;
      RECT 100.855 332.990 100.925 333.200 ;
    END
  END rw0_rd_out[431]
  PIN rw0_rd_out[432]
    DIRECTION OUTPUT ;
    USE SIGNAL ;
    SHAPE ABUTMENT ;
    PORT
      LAYER metal2 ;
      RECT 101.425 332.990 101.495 333.200 ;
    END
  END rw0_rd_out[432]
  PIN rw0_rd_out[433]
    DIRECTION OUTPUT ;
    USE SIGNAL ;
    SHAPE ABUTMENT ;
    PORT
      LAYER metal2 ;
      RECT 101.995 332.990 102.065 333.200 ;
    END
  END rw0_rd_out[433]
  PIN rw0_rd_out[434]
    DIRECTION OUTPUT ;
    USE SIGNAL ;
    SHAPE ABUTMENT ;
    PORT
      LAYER metal2 ;
      RECT 102.565 332.990 102.635 333.200 ;
    END
  END rw0_rd_out[434]
  PIN rw0_rd_out[435]
    DIRECTION OUTPUT ;
    USE SIGNAL ;
    SHAPE ABUTMENT ;
    PORT
      LAYER metal2 ;
      RECT 103.135 332.990 103.205 333.200 ;
    END
  END rw0_rd_out[435]
  PIN rw0_rd_out[436]
    DIRECTION OUTPUT ;
    USE SIGNAL ;
    SHAPE ABUTMENT ;
    PORT
      LAYER metal2 ;
      RECT 103.705 332.990 103.775 333.200 ;
    END
  END rw0_rd_out[436]
  PIN rw0_rd_out[437]
    DIRECTION OUTPUT ;
    USE SIGNAL ;
    SHAPE ABUTMENT ;
    PORT
      LAYER metal2 ;
      RECT 104.275 332.990 104.345 333.200 ;
    END
  END rw0_rd_out[437]
  PIN rw0_rd_out[438]
    DIRECTION OUTPUT ;
    USE SIGNAL ;
    SHAPE ABUTMENT ;
    PORT
      LAYER metal2 ;
      RECT 104.845 332.990 104.915 333.200 ;
    END
  END rw0_rd_out[438]
  PIN rw0_rd_out[439]
    DIRECTION OUTPUT ;
    USE SIGNAL ;
    SHAPE ABUTMENT ;
    PORT
      LAYER metal2 ;
      RECT 105.415 332.990 105.485 333.200 ;
    END
  END rw0_rd_out[439]
  PIN rw0_rd_out[440]
    DIRECTION OUTPUT ;
    USE SIGNAL ;
    SHAPE ABUTMENT ;
    PORT
      LAYER metal2 ;
      RECT 105.985 332.990 106.055 333.200 ;
    END
  END rw0_rd_out[440]
  PIN rw0_rd_out[441]
    DIRECTION OUTPUT ;
    USE SIGNAL ;
    SHAPE ABUTMENT ;
    PORT
      LAYER metal2 ;
      RECT 106.555 332.990 106.625 333.200 ;
    END
  END rw0_rd_out[441]
  PIN rw0_rd_out[442]
    DIRECTION OUTPUT ;
    USE SIGNAL ;
    SHAPE ABUTMENT ;
    PORT
      LAYER metal2 ;
      RECT 107.125 332.990 107.195 333.200 ;
    END
  END rw0_rd_out[442]
  PIN rw0_rd_out[443]
    DIRECTION OUTPUT ;
    USE SIGNAL ;
    SHAPE ABUTMENT ;
    PORT
      LAYER metal2 ;
      RECT 107.695 332.990 107.765 333.200 ;
    END
  END rw0_rd_out[443]
  PIN rw0_rd_out[444]
    DIRECTION OUTPUT ;
    USE SIGNAL ;
    SHAPE ABUTMENT ;
    PORT
      LAYER metal2 ;
      RECT 108.265 332.990 108.335 333.200 ;
    END
  END rw0_rd_out[444]
  PIN rw0_rd_out[445]
    DIRECTION OUTPUT ;
    USE SIGNAL ;
    SHAPE ABUTMENT ;
    PORT
      LAYER metal2 ;
      RECT 108.835 332.990 108.905 333.200 ;
    END
  END rw0_rd_out[445]
  PIN rw0_rd_out[446]
    DIRECTION OUTPUT ;
    USE SIGNAL ;
    SHAPE ABUTMENT ;
    PORT
      LAYER metal2 ;
      RECT 109.405 332.990 109.475 333.200 ;
    END
  END rw0_rd_out[446]
  PIN rw0_rd_out[447]
    DIRECTION OUTPUT ;
    USE SIGNAL ;
    SHAPE ABUTMENT ;
    PORT
      LAYER metal2 ;
      RECT 109.975 332.990 110.045 333.200 ;
    END
  END rw0_rd_out[447]
  PIN rw0_rd_out[448]
    DIRECTION OUTPUT ;
    USE SIGNAL ;
    SHAPE ABUTMENT ;
    PORT
      LAYER metal2 ;
      RECT 110.545 332.990 110.615 333.200 ;
    END
  END rw0_rd_out[448]
  PIN rw0_rd_out[449]
    DIRECTION OUTPUT ;
    USE SIGNAL ;
    SHAPE ABUTMENT ;
    PORT
      LAYER metal2 ;
      RECT 111.115 332.990 111.185 333.200 ;
    END
  END rw0_rd_out[449]
  PIN rw0_rd_out[450]
    DIRECTION OUTPUT ;
    USE SIGNAL ;
    SHAPE ABUTMENT ;
    PORT
      LAYER metal2 ;
      RECT 111.685 332.990 111.755 333.200 ;
    END
  END rw0_rd_out[450]
  PIN rw0_rd_out[451]
    DIRECTION OUTPUT ;
    USE SIGNAL ;
    SHAPE ABUTMENT ;
    PORT
      LAYER metal2 ;
      RECT 112.255 332.990 112.325 333.200 ;
    END
  END rw0_rd_out[451]
  PIN rw0_rd_out[452]
    DIRECTION OUTPUT ;
    USE SIGNAL ;
    SHAPE ABUTMENT ;
    PORT
      LAYER metal2 ;
      RECT 112.825 332.990 112.895 333.200 ;
    END
  END rw0_rd_out[452]
  PIN rw0_rd_out[453]
    DIRECTION OUTPUT ;
    USE SIGNAL ;
    SHAPE ABUTMENT ;
    PORT
      LAYER metal2 ;
      RECT 113.395 332.990 113.465 333.200 ;
    END
  END rw0_rd_out[453]
  PIN rw0_rd_out[454]
    DIRECTION OUTPUT ;
    USE SIGNAL ;
    SHAPE ABUTMENT ;
    PORT
      LAYER metal2 ;
      RECT 113.965 332.990 114.035 333.200 ;
    END
  END rw0_rd_out[454]
  PIN rw0_rd_out[455]
    DIRECTION OUTPUT ;
    USE SIGNAL ;
    SHAPE ABUTMENT ;
    PORT
      LAYER metal2 ;
      RECT 114.535 332.990 114.605 333.200 ;
    END
  END rw0_rd_out[455]
  PIN rw0_rd_out[456]
    DIRECTION OUTPUT ;
    USE SIGNAL ;
    SHAPE ABUTMENT ;
    PORT
      LAYER metal2 ;
      RECT 115.105 332.990 115.175 333.200 ;
    END
  END rw0_rd_out[456]
  PIN rw0_rd_out[457]
    DIRECTION OUTPUT ;
    USE SIGNAL ;
    SHAPE ABUTMENT ;
    PORT
      LAYER metal2 ;
      RECT 115.675 332.990 115.745 333.200 ;
    END
  END rw0_rd_out[457]
  PIN rw0_rd_out[458]
    DIRECTION OUTPUT ;
    USE SIGNAL ;
    SHAPE ABUTMENT ;
    PORT
      LAYER metal2 ;
      RECT 116.245 332.990 116.315 333.200 ;
    END
  END rw0_rd_out[458]
  PIN rw0_rd_out[459]
    DIRECTION OUTPUT ;
    USE SIGNAL ;
    SHAPE ABUTMENT ;
    PORT
      LAYER metal2 ;
      RECT 116.815 332.990 116.885 333.200 ;
    END
  END rw0_rd_out[459]
  PIN rw0_rd_out[460]
    DIRECTION OUTPUT ;
    USE SIGNAL ;
    SHAPE ABUTMENT ;
    PORT
      LAYER metal2 ;
      RECT 117.385 332.990 117.455 333.200 ;
    END
  END rw0_rd_out[460]
  PIN rw0_rd_out[461]
    DIRECTION OUTPUT ;
    USE SIGNAL ;
    SHAPE ABUTMENT ;
    PORT
      LAYER metal2 ;
      RECT 117.955 332.990 118.025 333.200 ;
    END
  END rw0_rd_out[461]
  PIN rw0_rd_out[462]
    DIRECTION OUTPUT ;
    USE SIGNAL ;
    SHAPE ABUTMENT ;
    PORT
      LAYER metal2 ;
      RECT 118.525 332.990 118.595 333.200 ;
    END
  END rw0_rd_out[462]
  PIN rw0_rd_out[463]
    DIRECTION OUTPUT ;
    USE SIGNAL ;
    SHAPE ABUTMENT ;
    PORT
      LAYER metal2 ;
      RECT 119.095 332.990 119.165 333.200 ;
    END
  END rw0_rd_out[463]
  PIN rw0_rd_out[464]
    DIRECTION OUTPUT ;
    USE SIGNAL ;
    SHAPE ABUTMENT ;
    PORT
      LAYER metal2 ;
      RECT 119.665 332.990 119.735 333.200 ;
    END
  END rw0_rd_out[464]
  PIN rw0_rd_out[465]
    DIRECTION OUTPUT ;
    USE SIGNAL ;
    SHAPE ABUTMENT ;
    PORT
      LAYER metal2 ;
      RECT 120.235 332.990 120.305 333.200 ;
    END
  END rw0_rd_out[465]
  PIN rw0_rd_out[466]
    DIRECTION OUTPUT ;
    USE SIGNAL ;
    SHAPE ABUTMENT ;
    PORT
      LAYER metal2 ;
      RECT 120.805 332.990 120.875 333.200 ;
    END
  END rw0_rd_out[466]
  PIN rw0_rd_out[467]
    DIRECTION OUTPUT ;
    USE SIGNAL ;
    SHAPE ABUTMENT ;
    PORT
      LAYER metal2 ;
      RECT 121.375 332.990 121.445 333.200 ;
    END
  END rw0_rd_out[467]
  PIN rw0_rd_out[468]
    DIRECTION OUTPUT ;
    USE SIGNAL ;
    SHAPE ABUTMENT ;
    PORT
      LAYER metal2 ;
      RECT 121.945 332.990 122.015 333.200 ;
    END
  END rw0_rd_out[468]
  PIN rw0_rd_out[469]
    DIRECTION OUTPUT ;
    USE SIGNAL ;
    SHAPE ABUTMENT ;
    PORT
      LAYER metal2 ;
      RECT 122.515 332.990 122.585 333.200 ;
    END
  END rw0_rd_out[469]
  PIN rw0_rd_out[470]
    DIRECTION OUTPUT ;
    USE SIGNAL ;
    SHAPE ABUTMENT ;
    PORT
      LAYER metal2 ;
      RECT 123.085 332.990 123.155 333.200 ;
    END
  END rw0_rd_out[470]
  PIN rw0_rd_out[471]
    DIRECTION OUTPUT ;
    USE SIGNAL ;
    SHAPE ABUTMENT ;
    PORT
      LAYER metal2 ;
      RECT 123.655 332.990 123.725 333.200 ;
    END
  END rw0_rd_out[471]
  PIN rw0_rd_out[472]
    DIRECTION OUTPUT ;
    USE SIGNAL ;
    SHAPE ABUTMENT ;
    PORT
      LAYER metal2 ;
      RECT 124.225 332.990 124.295 333.200 ;
    END
  END rw0_rd_out[472]
  PIN rw0_rd_out[473]
    DIRECTION OUTPUT ;
    USE SIGNAL ;
    SHAPE ABUTMENT ;
    PORT
      LAYER metal2 ;
      RECT 124.795 332.990 124.865 333.200 ;
    END
  END rw0_rd_out[473]
  PIN rw0_rd_out[474]
    DIRECTION OUTPUT ;
    USE SIGNAL ;
    SHAPE ABUTMENT ;
    PORT
      LAYER metal2 ;
      RECT 125.365 332.990 125.435 333.200 ;
    END
  END rw0_rd_out[474]
  PIN rw0_rd_out[475]
    DIRECTION OUTPUT ;
    USE SIGNAL ;
    SHAPE ABUTMENT ;
    PORT
      LAYER metal2 ;
      RECT 125.935 332.990 126.005 333.200 ;
    END
  END rw0_rd_out[475]
  PIN rw0_rd_out[476]
    DIRECTION OUTPUT ;
    USE SIGNAL ;
    SHAPE ABUTMENT ;
    PORT
      LAYER metal2 ;
      RECT 126.505 332.990 126.575 333.200 ;
    END
  END rw0_rd_out[476]
  PIN rw0_rd_out[477]
    DIRECTION OUTPUT ;
    USE SIGNAL ;
    SHAPE ABUTMENT ;
    PORT
      LAYER metal2 ;
      RECT 127.075 332.990 127.145 333.200 ;
    END
  END rw0_rd_out[477]
  PIN rw0_rd_out[478]
    DIRECTION OUTPUT ;
    USE SIGNAL ;
    SHAPE ABUTMENT ;
    PORT
      LAYER metal2 ;
      RECT 127.645 332.990 127.715 333.200 ;
    END
  END rw0_rd_out[478]
  PIN rw0_rd_out[479]
    DIRECTION OUTPUT ;
    USE SIGNAL ;
    SHAPE ABUTMENT ;
    PORT
      LAYER metal2 ;
      RECT 128.215 332.990 128.285 333.200 ;
    END
  END rw0_rd_out[479]
  PIN rw0_rd_out[480]
    DIRECTION OUTPUT ;
    USE SIGNAL ;
    SHAPE ABUTMENT ;
    PORT
      LAYER metal2 ;
      RECT 128.785 332.990 128.855 333.200 ;
    END
  END rw0_rd_out[480]
  PIN rw0_rd_out[481]
    DIRECTION OUTPUT ;
    USE SIGNAL ;
    SHAPE ABUTMENT ;
    PORT
      LAYER metal2 ;
      RECT 129.355 332.990 129.425 333.200 ;
    END
  END rw0_rd_out[481]
  PIN rw0_rd_out[482]
    DIRECTION OUTPUT ;
    USE SIGNAL ;
    SHAPE ABUTMENT ;
    PORT
      LAYER metal2 ;
      RECT 129.925 332.990 129.995 333.200 ;
    END
  END rw0_rd_out[482]
  PIN rw0_rd_out[483]
    DIRECTION OUTPUT ;
    USE SIGNAL ;
    SHAPE ABUTMENT ;
    PORT
      LAYER metal2 ;
      RECT 130.495 332.990 130.565 333.200 ;
    END
  END rw0_rd_out[483]
  PIN rw0_rd_out[484]
    DIRECTION OUTPUT ;
    USE SIGNAL ;
    SHAPE ABUTMENT ;
    PORT
      LAYER metal2 ;
      RECT 131.065 332.990 131.135 333.200 ;
    END
  END rw0_rd_out[484]
  PIN rw0_rd_out[485]
    DIRECTION OUTPUT ;
    USE SIGNAL ;
    SHAPE ABUTMENT ;
    PORT
      LAYER metal2 ;
      RECT 131.635 332.990 131.705 333.200 ;
    END
  END rw0_rd_out[485]
  PIN rw0_rd_out[486]
    DIRECTION OUTPUT ;
    USE SIGNAL ;
    SHAPE ABUTMENT ;
    PORT
      LAYER metal2 ;
      RECT 132.205 332.990 132.275 333.200 ;
    END
  END rw0_rd_out[486]
  PIN rw0_rd_out[487]
    DIRECTION OUTPUT ;
    USE SIGNAL ;
    SHAPE ABUTMENT ;
    PORT
      LAYER metal2 ;
      RECT 132.775 332.990 132.845 333.200 ;
    END
  END rw0_rd_out[487]
  PIN rw0_rd_out[488]
    DIRECTION OUTPUT ;
    USE SIGNAL ;
    SHAPE ABUTMENT ;
    PORT
      LAYER metal2 ;
      RECT 133.345 332.990 133.415 333.200 ;
    END
  END rw0_rd_out[488]
  PIN rw0_rd_out[489]
    DIRECTION OUTPUT ;
    USE SIGNAL ;
    SHAPE ABUTMENT ;
    PORT
      LAYER metal2 ;
      RECT 133.915 332.990 133.985 333.200 ;
    END
  END rw0_rd_out[489]
  PIN rw0_rd_out[490]
    DIRECTION OUTPUT ;
    USE SIGNAL ;
    SHAPE ABUTMENT ;
    PORT
      LAYER metal2 ;
      RECT 134.485 332.990 134.555 333.200 ;
    END
  END rw0_rd_out[490]
  PIN rw0_rd_out[491]
    DIRECTION OUTPUT ;
    USE SIGNAL ;
    SHAPE ABUTMENT ;
    PORT
      LAYER metal2 ;
      RECT 135.055 332.990 135.125 333.200 ;
    END
  END rw0_rd_out[491]
  PIN rw0_rd_out[492]
    DIRECTION OUTPUT ;
    USE SIGNAL ;
    SHAPE ABUTMENT ;
    PORT
      LAYER metal2 ;
      RECT 135.625 332.990 135.695 333.200 ;
    END
  END rw0_rd_out[492]
  PIN rw0_rd_out[493]
    DIRECTION OUTPUT ;
    USE SIGNAL ;
    SHAPE ABUTMENT ;
    PORT
      LAYER metal2 ;
      RECT 136.195 332.990 136.265 333.200 ;
    END
  END rw0_rd_out[493]
  PIN rw0_rd_out[494]
    DIRECTION OUTPUT ;
    USE SIGNAL ;
    SHAPE ABUTMENT ;
    PORT
      LAYER metal2 ;
      RECT 136.765 332.990 136.835 333.200 ;
    END
  END rw0_rd_out[494]
  PIN rw0_rd_out[495]
    DIRECTION OUTPUT ;
    USE SIGNAL ;
    SHAPE ABUTMENT ;
    PORT
      LAYER metal2 ;
      RECT 137.335 332.990 137.405 333.200 ;
    END
  END rw0_rd_out[495]
  PIN rw0_rd_out[496]
    DIRECTION OUTPUT ;
    USE SIGNAL ;
    SHAPE ABUTMENT ;
    PORT
      LAYER metal2 ;
      RECT 137.905 332.990 137.975 333.200 ;
    END
  END rw0_rd_out[496]
  PIN rw0_rd_out[497]
    DIRECTION OUTPUT ;
    USE SIGNAL ;
    SHAPE ABUTMENT ;
    PORT
      LAYER metal2 ;
      RECT 138.475 332.990 138.545 333.200 ;
    END
  END rw0_rd_out[497]
  PIN rw0_rd_out[498]
    DIRECTION OUTPUT ;
    USE SIGNAL ;
    SHAPE ABUTMENT ;
    PORT
      LAYER metal2 ;
      RECT 139.045 332.990 139.115 333.200 ;
    END
  END rw0_rd_out[498]
  PIN rw0_rd_out[499]
    DIRECTION OUTPUT ;
    USE SIGNAL ;
    SHAPE ABUTMENT ;
    PORT
      LAYER metal2 ;
      RECT 139.615 332.990 139.685 333.200 ;
    END
  END rw0_rd_out[499]
  PIN rw0_rd_out[500]
    DIRECTION OUTPUT ;
    USE SIGNAL ;
    SHAPE ABUTMENT ;
    PORT
      LAYER metal2 ;
      RECT 140.185 332.990 140.255 333.200 ;
    END
  END rw0_rd_out[500]
  PIN rw0_rd_out[501]
    DIRECTION OUTPUT ;
    USE SIGNAL ;
    SHAPE ABUTMENT ;
    PORT
      LAYER metal2 ;
      RECT 140.755 332.990 140.825 333.200 ;
    END
  END rw0_rd_out[501]
  PIN rw0_rd_out[502]
    DIRECTION OUTPUT ;
    USE SIGNAL ;
    SHAPE ABUTMENT ;
    PORT
      LAYER metal2 ;
      RECT 141.325 332.990 141.395 333.200 ;
    END
  END rw0_rd_out[502]
  PIN rw0_rd_out[503]
    DIRECTION OUTPUT ;
    USE SIGNAL ;
    SHAPE ABUTMENT ;
    PORT
      LAYER metal2 ;
      RECT 141.895 332.990 141.965 333.200 ;
    END
  END rw0_rd_out[503]
  PIN rw0_rd_out[504]
    DIRECTION OUTPUT ;
    USE SIGNAL ;
    SHAPE ABUTMENT ;
    PORT
      LAYER metal2 ;
      RECT 142.465 332.990 142.535 333.200 ;
    END
  END rw0_rd_out[504]
  PIN rw0_rd_out[505]
    DIRECTION OUTPUT ;
    USE SIGNAL ;
    SHAPE ABUTMENT ;
    PORT
      LAYER metal2 ;
      RECT 143.035 332.990 143.105 333.200 ;
    END
  END rw0_rd_out[505]
  PIN rw0_rd_out[506]
    DIRECTION OUTPUT ;
    USE SIGNAL ;
    SHAPE ABUTMENT ;
    PORT
      LAYER metal2 ;
      RECT 143.605 332.990 143.675 333.200 ;
    END
  END rw0_rd_out[506]
  PIN rw0_rd_out[507]
    DIRECTION OUTPUT ;
    USE SIGNAL ;
    SHAPE ABUTMENT ;
    PORT
      LAYER metal2 ;
      RECT 144.175 332.990 144.245 333.200 ;
    END
  END rw0_rd_out[507]
  PIN rw0_rd_out[508]
    DIRECTION OUTPUT ;
    USE SIGNAL ;
    SHAPE ABUTMENT ;
    PORT
      LAYER metal2 ;
      RECT 144.745 332.990 144.815 333.200 ;
    END
  END rw0_rd_out[508]
  PIN rw0_rd_out[509]
    DIRECTION OUTPUT ;
    USE SIGNAL ;
    SHAPE ABUTMENT ;
    PORT
      LAYER metal2 ;
      RECT 145.315 332.990 145.385 333.200 ;
    END
  END rw0_rd_out[509]
  PIN rw0_rd_out[510]
    DIRECTION OUTPUT ;
    USE SIGNAL ;
    SHAPE ABUTMENT ;
    PORT
      LAYER metal2 ;
      RECT 145.885 332.990 145.955 333.200 ;
    END
  END rw0_rd_out[510]
  PIN rw0_rd_out[511]
    DIRECTION OUTPUT ;
    USE SIGNAL ;
    SHAPE ABUTMENT ;
    PORT
      LAYER metal2 ;
      RECT 146.455 332.990 146.525 333.200 ;
    END
  END rw0_rd_out[511]
  PIN rw0_addr_in[0]
    DIRECTION INPUT ;
    USE SIGNAL ;
    SHAPE ABUTMENT ;
    PORT
      LAYER metal3 ;
      RECT 0.000 323.365 0.210 323.435 ;
    END
  END rw0_addr_in[0]
  PIN rw0_addr_in[1]
    DIRECTION INPUT ;
    USE SIGNAL ;
    SHAPE ABUTMENT ;
    PORT
      LAYER metal3 ;
      RECT 0.000 325.885 0.210 325.955 ;
    END
  END rw0_addr_in[1]
  PIN rw0_addr_in[2]
    DIRECTION INPUT ;
    USE SIGNAL ;
    SHAPE ABUTMENT ;
    PORT
      LAYER metal3 ;
      RECT 0.000 328.405 0.210 328.475 ;
    END
  END rw0_addr_in[2]
  PIN rw0_addr_in[3]
    DIRECTION INPUT ;
    USE SIGNAL ;
    SHAPE ABUTMENT ;
    PORT
      LAYER metal3 ;
      RECT 165.660 323.365 165.870 323.435 ;
    END
  END rw0_addr_in[3]
  PIN rw0_addr_in[4]
    DIRECTION INPUT ;
    USE SIGNAL ;
    SHAPE ABUTMENT ;
    PORT
      LAYER metal3 ;
      RECT 165.660 325.885 165.870 325.955 ;
    END
  END rw0_addr_in[4]
  PIN rw0_addr_in[5]
    DIRECTION INPUT ;
    USE SIGNAL ;
    SHAPE ABUTMENT ;
    PORT
      LAYER metal3 ;
      RECT 165.660 328.405 165.870 328.475 ;
    END
  END rw0_addr_in[5]
  PIN rw0_we_in
    DIRECTION INPUT ;
    USE SIGNAL ;
    SHAPE ABUTMENT ;
    PORT
      LAYER metal2 ;
      RECT 147.025 332.990 147.095 333.200 ;
    END
  END rw0_we_in
  PIN rw0_ce_in
    DIRECTION INPUT ;
    USE SIGNAL ;
    SHAPE ABUTMENT ;
    PORT
      LAYER metal2 ;
      RECT 147.595 332.990 147.665 333.200 ;
    END
  END rw0_ce_in
  PIN rw0_clk
    DIRECTION INPUT ;
    USE SIGNAL ;
    SHAPE ABUTMENT ;
    PORT
      LAYER metal2 ;
      RECT 148.165 332.990 148.235 333.200 ;
    END
  END rw0_clk
  PIN VSS
    DIRECTION INOUT ;
    USE GROUND ;
    PORT
      LAYER metal4 ;
      RECT 1.000 0.840 1.280 332.360 ;
      RECT 3.240 0.840 3.520 332.360 ;
      RECT 5.480 0.840 5.760 332.360 ;
      RECT 7.720 0.840 8.000 332.360 ;
      RECT 9.960 0.840 10.240 332.360 ;
      RECT 12.200 0.840 12.480 332.360 ;
      RECT 14.440 0.840 14.720 332.360 ;
      RECT 16.680 0.840 16.960 332.360 ;
      RECT 18.920 0.840 19.200 332.360 ;
      RECT 21.160 0.840 21.440 332.360 ;
      RECT 23.400 0.840 23.680 332.360 ;
      RECT 25.640 0.840 25.920 332.360 ;
      RECT 27.880 0.840 28.160 332.360 ;
      RECT 30.120 0.840 30.400 332.360 ;
      RECT 32.360 0.840 32.640 332.360 ;
      RECT 34.600 0.840 34.880 332.360 ;
      RECT 36.840 0.840 37.120 332.360 ;
      RECT 39.080 0.840 39.360 332.360 ;
      RECT 41.320 0.840 41.600 332.360 ;
      RECT 43.560 0.840 43.840 332.360 ;
      RECT 45.800 0.840 46.080 332.360 ;
      RECT 48.040 0.840 48.320 332.360 ;
      RECT 50.280 0.840 50.560 332.360 ;
      RECT 52.520 0.840 52.800 332.360 ;
      RECT 54.760 0.840 55.040 332.360 ;
      RECT 57.000 0.840 57.280 332.360 ;
      RECT 59.240 0.840 59.520 332.360 ;
      RECT 61.480 0.840 61.760 332.360 ;
      RECT 63.720 0.840 64.000 332.360 ;
      RECT 65.960 0.840 66.240 332.360 ;
      RECT 68.200 0.840 68.480 332.360 ;
      RECT 70.440 0.840 70.720 332.360 ;
      RECT 72.680 0.840 72.960 332.360 ;
      RECT 74.920 0.840 75.200 332.360 ;
      RECT 77.160 0.840 77.440 332.360 ;
      RECT 79.400 0.840 79.680 332.360 ;
      RECT 81.640 0.840 81.920 332.360 ;
      RECT 83.880 0.840 84.160 332.360 ;
      RECT 86.120 0.840 86.400 332.360 ;
      RECT 88.360 0.840 88.640 332.360 ;
      RECT 90.600 0.840 90.880 332.360 ;
      RECT 92.840 0.840 93.120 332.360 ;
      RECT 95.080 0.840 95.360 332.360 ;
      RECT 97.320 0.840 97.600 332.360 ;
      RECT 99.560 0.840 99.840 332.360 ;
      RECT 101.800 0.840 102.080 332.360 ;
      RECT 104.040 0.840 104.320 332.360 ;
      RECT 106.280 0.840 106.560 332.360 ;
      RECT 108.520 0.840 108.800 332.360 ;
      RECT 110.760 0.840 111.040 332.360 ;
      RECT 113.000 0.840 113.280 332.360 ;
      RECT 115.240 0.840 115.520 332.360 ;
      RECT 117.480 0.840 117.760 332.360 ;
      RECT 119.720 0.840 120.000 332.360 ;
      RECT 121.960 0.840 122.240 332.360 ;
      RECT 124.200 0.840 124.480 332.360 ;
      RECT 126.440 0.840 126.720 332.360 ;
      RECT 128.680 0.840 128.960 332.360 ;
      RECT 130.920 0.840 131.200 332.360 ;
      RECT 133.160 0.840 133.440 332.360 ;
      RECT 135.400 0.840 135.680 332.360 ;
      RECT 137.640 0.840 137.920 332.360 ;
      RECT 139.880 0.840 140.160 332.360 ;
      RECT 142.120 0.840 142.400 332.360 ;
      RECT 144.360 0.840 144.640 332.360 ;
      RECT 146.600 0.840 146.880 332.360 ;
      RECT 148.840 0.840 149.120 332.360 ;
      RECT 151.080 0.840 151.360 332.360 ;
      RECT 153.320 0.840 153.600 332.360 ;
      RECT 155.560 0.840 155.840 332.360 ;
      RECT 157.800 0.840 158.080 332.360 ;
      RECT 160.040 0.840 160.320 332.360 ;
      RECT 162.280 0.840 162.560 332.360 ;
      RECT 164.520 0.840 164.800 332.360 ;
    END
  END VSS
  PIN VDD
    DIRECTION INOUT ;
    USE POWER ;
    PORT
      LAYER metal4 ;
      RECT 2.120 0.840 2.400 332.360 ;
      RECT 4.360 0.840 4.640 332.360 ;
      RECT 6.600 0.840 6.880 332.360 ;
      RECT 8.840 0.840 9.120 332.360 ;
      RECT 11.080 0.840 11.360 332.360 ;
      RECT 13.320 0.840 13.600 332.360 ;
      RECT 15.560 0.840 15.840 332.360 ;
      RECT 17.800 0.840 18.080 332.360 ;
      RECT 20.040 0.840 20.320 332.360 ;
      RECT 22.280 0.840 22.560 332.360 ;
      RECT 24.520 0.840 24.800 332.360 ;
      RECT 26.760 0.840 27.040 332.360 ;
      RECT 29.000 0.840 29.280 332.360 ;
      RECT 31.240 0.840 31.520 332.360 ;
      RECT 33.480 0.840 33.760 332.360 ;
      RECT 35.720 0.840 36.000 332.360 ;
      RECT 37.960 0.840 38.240 332.360 ;
      RECT 40.200 0.840 40.480 332.360 ;
      RECT 42.440 0.840 42.720 332.360 ;
      RECT 44.680 0.840 44.960 332.360 ;
      RECT 46.920 0.840 47.200 332.360 ;
      RECT 49.160 0.840 49.440 332.360 ;
      RECT 51.400 0.840 51.680 332.360 ;
      RECT 53.640 0.840 53.920 332.360 ;
      RECT 55.880 0.840 56.160 332.360 ;
      RECT 58.120 0.840 58.400 332.360 ;
      RECT 60.360 0.840 60.640 332.360 ;
      RECT 62.600 0.840 62.880 332.360 ;
      RECT 64.840 0.840 65.120 332.360 ;
      RECT 67.080 0.840 67.360 332.360 ;
      RECT 69.320 0.840 69.600 332.360 ;
      RECT 71.560 0.840 71.840 332.360 ;
      RECT 73.800 0.840 74.080 332.360 ;
      RECT 76.040 0.840 76.320 332.360 ;
      RECT 78.280 0.840 78.560 332.360 ;
      RECT 80.520 0.840 80.800 332.360 ;
      RECT 82.760 0.840 83.040 332.360 ;
      RECT 85.000 0.840 85.280 332.360 ;
      RECT 87.240 0.840 87.520 332.360 ;
      RECT 89.480 0.840 89.760 332.360 ;
      RECT 91.720 0.840 92.000 332.360 ;
      RECT 93.960 0.840 94.240 332.360 ;
      RECT 96.200 0.840 96.480 332.360 ;
      RECT 98.440 0.840 98.720 332.360 ;
      RECT 100.680 0.840 100.960 332.360 ;
      RECT 102.920 0.840 103.200 332.360 ;
      RECT 105.160 0.840 105.440 332.360 ;
      RECT 107.400 0.840 107.680 332.360 ;
      RECT 109.640 0.840 109.920 332.360 ;
      RECT 111.880 0.840 112.160 332.360 ;
      RECT 114.120 0.840 114.400 332.360 ;
      RECT 116.360 0.840 116.640 332.360 ;
      RECT 118.600 0.840 118.880 332.360 ;
      RECT 120.840 0.840 121.120 332.360 ;
      RECT 123.080 0.840 123.360 332.360 ;
      RECT 125.320 0.840 125.600 332.360 ;
      RECT 127.560 0.840 127.840 332.360 ;
      RECT 129.800 0.840 130.080 332.360 ;
      RECT 132.040 0.840 132.320 332.360 ;
      RECT 134.280 0.840 134.560 332.360 ;
      RECT 136.520 0.840 136.800 332.360 ;
      RECT 138.760 0.840 139.040 332.360 ;
      RECT 141.000 0.840 141.280 332.360 ;
      RECT 143.240 0.840 143.520 332.360 ;
      RECT 145.480 0.840 145.760 332.360 ;
      RECT 147.720 0.840 148.000 332.360 ;
      RECT 149.960 0.840 150.240 332.360 ;
      RECT 152.200 0.840 152.480 332.360 ;
      RECT 154.440 0.840 154.720 332.360 ;
      RECT 156.680 0.840 156.960 332.360 ;
      RECT 158.920 0.840 159.200 332.360 ;
      RECT 161.160 0.840 161.440 332.360 ;
      RECT 163.400 0.840 163.680 332.360 ;
    END
  END VDD
  OBS
    LAYER metal1 ;
    RECT 0 0 165.870 333.200 ;
    LAYER metal2 ;
    RECT 0 0 165.870 333.200 ;
    LAYER metal3 ;
    RECT 0 0 165.870 333.200 ;
    LAYER metal4 ;
    RECT 0 0 165.870 333.200 ;
    LAYER OVERLAP ;
    RECT 0 0 165.870 333.200 ;
  END
END fakeram_64x512

END LIBRARY
